VERSION 5.7 ;
BUSBITCHARS "[]" ;
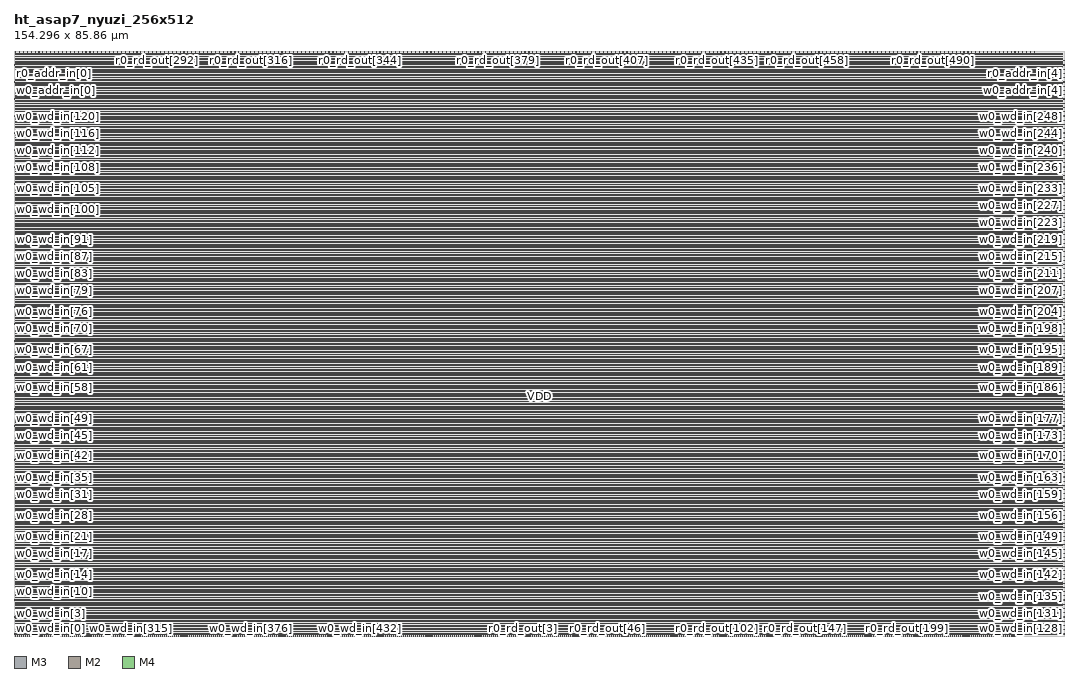
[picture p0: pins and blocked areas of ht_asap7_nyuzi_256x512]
MACRO ht_asap7_nyuzi_256x512
  FOREIGN ht_asap7_nyuzi_256x512 0 0 ;
  SYMMETRY X Y R90 ;
  SIZE 154.296 BY 85.860 ;
  CLASS BLOCK ;
  PIN w0_wd_in[0]
    DIRECTION INPUT ;
    USE SIGNAL ;
    SHAPE ABUTMENT ;
    PORT
      LAYER M3 ;
      RECT 0.000 0.276 0.072 0.300 ;
    END
  END w0_wd_in[0]
  PIN w0_wd_in[1]
    DIRECTION INPUT ;
    USE SIGNAL ;
    SHAPE ABUTMENT ;
    PORT
      LAYER M3 ;
      RECT 0.000 0.900 0.072 0.924 ;
    END
  END w0_wd_in[1]
  PIN w0_wd_in[2]
    DIRECTION INPUT ;
    USE SIGNAL ;
    SHAPE ABUTMENT ;
    PORT
      LAYER M3 ;
      RECT 0.000 1.524 0.072 1.548 ;
    END
  END w0_wd_in[2]
  PIN w0_wd_in[3]
    DIRECTION INPUT ;
    USE SIGNAL ;
    SHAPE ABUTMENT ;
    PORT
      LAYER M3 ;
      RECT 0.000 2.148 0.072 2.172 ;
    END
  END w0_wd_in[3]
  PIN w0_wd_in[4]
    DIRECTION INPUT ;
    USE SIGNAL ;
    SHAPE ABUTMENT ;
    PORT
      LAYER M3 ;
      RECT 0.000 2.772 0.072 2.796 ;
    END
  END w0_wd_in[4]
  PIN w0_wd_in[5]
    DIRECTION INPUT ;
    USE SIGNAL ;
    SHAPE ABUTMENT ;
    PORT
      LAYER M3 ;
      RECT 0.000 3.396 0.072 3.420 ;
    END
  END w0_wd_in[5]
  PIN w0_wd_in[6]
    DIRECTION INPUT ;
    USE SIGNAL ;
    SHAPE ABUTMENT ;
    PORT
      LAYER M3 ;
      RECT 0.000 4.020 0.072 4.044 ;
    END
  END w0_wd_in[6]
  PIN w0_wd_in[7]
    DIRECTION INPUT ;
    USE SIGNAL ;
    SHAPE ABUTMENT ;
    PORT
      LAYER M3 ;
      RECT 0.000 4.644 0.072 4.668 ;
    END
  END w0_wd_in[7]
  PIN w0_wd_in[8]
    DIRECTION INPUT ;
    USE SIGNAL ;
    SHAPE ABUTMENT ;
    PORT
      LAYER M3 ;
      RECT 0.000 5.268 0.072 5.292 ;
    END
  END w0_wd_in[8]
  PIN w0_wd_in[9]
    DIRECTION INPUT ;
    USE SIGNAL ;
    SHAPE ABUTMENT ;
    PORT
      LAYER M3 ;
      RECT 0.000 5.892 0.072 5.916 ;
    END
  END w0_wd_in[9]
  PIN w0_wd_in[10]
    DIRECTION INPUT ;
    USE SIGNAL ;
    SHAPE ABUTMENT ;
    PORT
      LAYER M3 ;
      RECT 0.000 6.516 0.072 6.540 ;
    END
  END w0_wd_in[10]
  PIN w0_wd_in[11]
    DIRECTION INPUT ;
    USE SIGNAL ;
    SHAPE ABUTMENT ;
    PORT
      LAYER M3 ;
      RECT 0.000 7.140 0.072 7.164 ;
    END
  END w0_wd_in[11]
  PIN w0_wd_in[12]
    DIRECTION INPUT ;
    USE SIGNAL ;
    SHAPE ABUTMENT ;
    PORT
      LAYER M3 ;
      RECT 0.000 7.764 0.072 7.788 ;
    END
  END w0_wd_in[12]
  PIN w0_wd_in[13]
    DIRECTION INPUT ;
    USE SIGNAL ;
    SHAPE ABUTMENT ;
    PORT
      LAYER M3 ;
      RECT 0.000 8.388 0.072 8.412 ;
    END
  END w0_wd_in[13]
  PIN w0_wd_in[14]
    DIRECTION INPUT ;
    USE SIGNAL ;
    SHAPE ABUTMENT ;
    PORT
      LAYER M3 ;
      RECT 0.000 9.012 0.072 9.036 ;
    END
  END w0_wd_in[14]
  PIN w0_wd_in[15]
    DIRECTION INPUT ;
    USE SIGNAL ;
    SHAPE ABUTMENT ;
    PORT
      LAYER M3 ;
      RECT 0.000 9.636 0.072 9.660 ;
    END
  END w0_wd_in[15]
  PIN w0_wd_in[16]
    DIRECTION INPUT ;
    USE SIGNAL ;
    SHAPE ABUTMENT ;
    PORT
      LAYER M3 ;
      RECT 0.000 10.260 0.072 10.284 ;
    END
  END w0_wd_in[16]
  PIN w0_wd_in[17]
    DIRECTION INPUT ;
    USE SIGNAL ;
    SHAPE ABUTMENT ;
    PORT
      LAYER M3 ;
      RECT 0.000 10.884 0.072 10.908 ;
    END
  END w0_wd_in[17]
  PIN w0_wd_in[18]
    DIRECTION INPUT ;
    USE SIGNAL ;
    SHAPE ABUTMENT ;
    PORT
      LAYER M3 ;
      RECT 0.000 11.508 0.072 11.532 ;
    END
  END w0_wd_in[18]
  PIN w0_wd_in[19]
    DIRECTION INPUT ;
    USE SIGNAL ;
    SHAPE ABUTMENT ;
    PORT
      LAYER M3 ;
      RECT 0.000 12.132 0.072 12.156 ;
    END
  END w0_wd_in[19]
  PIN w0_wd_in[20]
    DIRECTION INPUT ;
    USE SIGNAL ;
    SHAPE ABUTMENT ;
    PORT
      LAYER M3 ;
      RECT 0.000 12.756 0.072 12.780 ;
    END
  END w0_wd_in[20]
  PIN w0_wd_in[21]
    DIRECTION INPUT ;
    USE SIGNAL ;
    SHAPE ABUTMENT ;
    PORT
      LAYER M3 ;
      RECT 0.000 13.380 0.072 13.404 ;
    END
  END w0_wd_in[21]
  PIN w0_wd_in[22]
    DIRECTION INPUT ;
    USE SIGNAL ;
    SHAPE ABUTMENT ;
    PORT
      LAYER M3 ;
      RECT 0.000 14.004 0.072 14.028 ;
    END
  END w0_wd_in[22]
  PIN w0_wd_in[23]
    DIRECTION INPUT ;
    USE SIGNAL ;
    SHAPE ABUTMENT ;
    PORT
      LAYER M3 ;
      RECT 0.000 14.628 0.072 14.652 ;
    END
  END w0_wd_in[23]
  PIN w0_wd_in[24]
    DIRECTION INPUT ;
    USE SIGNAL ;
    SHAPE ABUTMENT ;
    PORT
      LAYER M3 ;
      RECT 0.000 15.252 0.072 15.276 ;
    END
  END w0_wd_in[24]
  PIN w0_wd_in[25]
    DIRECTION INPUT ;
    USE SIGNAL ;
    SHAPE ABUTMENT ;
    PORT
      LAYER M3 ;
      RECT 0.000 15.876 0.072 15.900 ;
    END
  END w0_wd_in[25]
  PIN w0_wd_in[26]
    DIRECTION INPUT ;
    USE SIGNAL ;
    SHAPE ABUTMENT ;
    PORT
      LAYER M3 ;
      RECT 0.000 16.500 0.072 16.524 ;
    END
  END w0_wd_in[26]
  PIN w0_wd_in[27]
    DIRECTION INPUT ;
    USE SIGNAL ;
    SHAPE ABUTMENT ;
    PORT
      LAYER M3 ;
      RECT 0.000 17.124 0.072 17.148 ;
    END
  END w0_wd_in[27]
  PIN w0_wd_in[28]
    DIRECTION INPUT ;
    USE SIGNAL ;
    SHAPE ABUTMENT ;
    PORT
      LAYER M3 ;
      RECT 0.000 17.748 0.072 17.772 ;
    END
  END w0_wd_in[28]
  PIN w0_wd_in[29]
    DIRECTION INPUT ;
    USE SIGNAL ;
    SHAPE ABUTMENT ;
    PORT
      LAYER M3 ;
      RECT 0.000 18.372 0.072 18.396 ;
    END
  END w0_wd_in[29]
  PIN w0_wd_in[30]
    DIRECTION INPUT ;
    USE SIGNAL ;
    SHAPE ABUTMENT ;
    PORT
      LAYER M3 ;
      RECT 0.000 18.996 0.072 19.020 ;
    END
  END w0_wd_in[30]
  PIN w0_wd_in[31]
    DIRECTION INPUT ;
    USE SIGNAL ;
    SHAPE ABUTMENT ;
    PORT
      LAYER M3 ;
      RECT 0.000 19.620 0.072 19.644 ;
    END
  END w0_wd_in[31]
  PIN w0_wd_in[32]
    DIRECTION INPUT ;
    USE SIGNAL ;
    SHAPE ABUTMENT ;
    PORT
      LAYER M3 ;
      RECT 0.000 20.244 0.072 20.268 ;
    END
  END w0_wd_in[32]
  PIN w0_wd_in[33]
    DIRECTION INPUT ;
    USE SIGNAL ;
    SHAPE ABUTMENT ;
    PORT
      LAYER M3 ;
      RECT 0.000 20.868 0.072 20.892 ;
    END
  END w0_wd_in[33]
  PIN w0_wd_in[34]
    DIRECTION INPUT ;
    USE SIGNAL ;
    SHAPE ABUTMENT ;
    PORT
      LAYER M3 ;
      RECT 0.000 21.492 0.072 21.516 ;
    END
  END w0_wd_in[34]
  PIN w0_wd_in[35]
    DIRECTION INPUT ;
    USE SIGNAL ;
    SHAPE ABUTMENT ;
    PORT
      LAYER M3 ;
      RECT 0.000 22.116 0.072 22.140 ;
    END
  END w0_wd_in[35]
  PIN w0_wd_in[36]
    DIRECTION INPUT ;
    USE SIGNAL ;
    SHAPE ABUTMENT ;
    PORT
      LAYER M3 ;
      RECT 0.000 22.740 0.072 22.764 ;
    END
  END w0_wd_in[36]
  PIN w0_wd_in[37]
    DIRECTION INPUT ;
    USE SIGNAL ;
    SHAPE ABUTMENT ;
    PORT
      LAYER M3 ;
      RECT 0.000 23.364 0.072 23.388 ;
    END
  END w0_wd_in[37]
  PIN w0_wd_in[38]
    DIRECTION INPUT ;
    USE SIGNAL ;
    SHAPE ABUTMENT ;
    PORT
      LAYER M3 ;
      RECT 0.000 23.988 0.072 24.012 ;
    END
  END w0_wd_in[38]
  PIN w0_wd_in[39]
    DIRECTION INPUT ;
    USE SIGNAL ;
    SHAPE ABUTMENT ;
    PORT
      LAYER M3 ;
      RECT 0.000 24.612 0.072 24.636 ;
    END
  END w0_wd_in[39]
  PIN w0_wd_in[40]
    DIRECTION INPUT ;
    USE SIGNAL ;
    SHAPE ABUTMENT ;
    PORT
      LAYER M3 ;
      RECT 0.000 25.236 0.072 25.260 ;
    END
  END w0_wd_in[40]
  PIN w0_wd_in[41]
    DIRECTION INPUT ;
    USE SIGNAL ;
    SHAPE ABUTMENT ;
    PORT
      LAYER M3 ;
      RECT 0.000 25.860 0.072 25.884 ;
    END
  END w0_wd_in[41]
  PIN w0_wd_in[42]
    DIRECTION INPUT ;
    USE SIGNAL ;
    SHAPE ABUTMENT ;
    PORT
      LAYER M3 ;
      RECT 0.000 26.484 0.072 26.508 ;
    END
  END w0_wd_in[42]
  PIN w0_wd_in[43]
    DIRECTION INPUT ;
    USE SIGNAL ;
    SHAPE ABUTMENT ;
    PORT
      LAYER M3 ;
      RECT 0.000 27.108 0.072 27.132 ;
    END
  END w0_wd_in[43]
  PIN w0_wd_in[44]
    DIRECTION INPUT ;
    USE SIGNAL ;
    SHAPE ABUTMENT ;
    PORT
      LAYER M3 ;
      RECT 0.000 27.732 0.072 27.756 ;
    END
  END w0_wd_in[44]
  PIN w0_wd_in[45]
    DIRECTION INPUT ;
    USE SIGNAL ;
    SHAPE ABUTMENT ;
    PORT
      LAYER M3 ;
      RECT 0.000 28.356 0.072 28.380 ;
    END
  END w0_wd_in[45]
  PIN w0_wd_in[46]
    DIRECTION INPUT ;
    USE SIGNAL ;
    SHAPE ABUTMENT ;
    PORT
      LAYER M3 ;
      RECT 0.000 28.980 0.072 29.004 ;
    END
  END w0_wd_in[46]
  PIN w0_wd_in[47]
    DIRECTION INPUT ;
    USE SIGNAL ;
    SHAPE ABUTMENT ;
    PORT
      LAYER M3 ;
      RECT 0.000 29.604 0.072 29.628 ;
    END
  END w0_wd_in[47]
  PIN w0_wd_in[48]
    DIRECTION INPUT ;
    USE SIGNAL ;
    SHAPE ABUTMENT ;
    PORT
      LAYER M3 ;
      RECT 0.000 30.228 0.072 30.252 ;
    END
  END w0_wd_in[48]
  PIN w0_wd_in[49]
    DIRECTION INPUT ;
    USE SIGNAL ;
    SHAPE ABUTMENT ;
    PORT
      LAYER M3 ;
      RECT 0.000 30.852 0.072 30.876 ;
    END
  END w0_wd_in[49]
  PIN w0_wd_in[50]
    DIRECTION INPUT ;
    USE SIGNAL ;
    SHAPE ABUTMENT ;
    PORT
      LAYER M3 ;
      RECT 0.000 31.476 0.072 31.500 ;
    END
  END w0_wd_in[50]
  PIN w0_wd_in[51]
    DIRECTION INPUT ;
    USE SIGNAL ;
    SHAPE ABUTMENT ;
    PORT
      LAYER M3 ;
      RECT 0.000 32.100 0.072 32.124 ;
    END
  END w0_wd_in[51]
  PIN w0_wd_in[52]
    DIRECTION INPUT ;
    USE SIGNAL ;
    SHAPE ABUTMENT ;
    PORT
      LAYER M3 ;
      RECT 0.000 32.724 0.072 32.748 ;
    END
  END w0_wd_in[52]
  PIN w0_wd_in[53]
    DIRECTION INPUT ;
    USE SIGNAL ;
    SHAPE ABUTMENT ;
    PORT
      LAYER M3 ;
      RECT 0.000 33.348 0.072 33.372 ;
    END
  END w0_wd_in[53]
  PIN w0_wd_in[54]
    DIRECTION INPUT ;
    USE SIGNAL ;
    SHAPE ABUTMENT ;
    PORT
      LAYER M3 ;
      RECT 0.000 33.972 0.072 33.996 ;
    END
  END w0_wd_in[54]
  PIN w0_wd_in[55]
    DIRECTION INPUT ;
    USE SIGNAL ;
    SHAPE ABUTMENT ;
    PORT
      LAYER M3 ;
      RECT 0.000 34.596 0.072 34.620 ;
    END
  END w0_wd_in[55]
  PIN w0_wd_in[56]
    DIRECTION INPUT ;
    USE SIGNAL ;
    SHAPE ABUTMENT ;
    PORT
      LAYER M3 ;
      RECT 0.000 35.220 0.072 35.244 ;
    END
  END w0_wd_in[56]
  PIN w0_wd_in[57]
    DIRECTION INPUT ;
    USE SIGNAL ;
    SHAPE ABUTMENT ;
    PORT
      LAYER M3 ;
      RECT 0.000 35.844 0.072 35.868 ;
    END
  END w0_wd_in[57]
  PIN w0_wd_in[58]
    DIRECTION INPUT ;
    USE SIGNAL ;
    SHAPE ABUTMENT ;
    PORT
      LAYER M3 ;
      RECT 0.000 36.468 0.072 36.492 ;
    END
  END w0_wd_in[58]
  PIN w0_wd_in[59]
    DIRECTION INPUT ;
    USE SIGNAL ;
    SHAPE ABUTMENT ;
    PORT
      LAYER M3 ;
      RECT 0.000 37.092 0.072 37.116 ;
    END
  END w0_wd_in[59]
  PIN w0_wd_in[60]
    DIRECTION INPUT ;
    USE SIGNAL ;
    SHAPE ABUTMENT ;
    PORT
      LAYER M3 ;
      RECT 0.000 37.716 0.072 37.740 ;
    END
  END w0_wd_in[60]
  PIN w0_wd_in[61]
    DIRECTION INPUT ;
    USE SIGNAL ;
    SHAPE ABUTMENT ;
    PORT
      LAYER M3 ;
      RECT 0.000 38.340 0.072 38.364 ;
    END
  END w0_wd_in[61]
  PIN w0_wd_in[62]
    DIRECTION INPUT ;
    USE SIGNAL ;
    SHAPE ABUTMENT ;
    PORT
      LAYER M3 ;
      RECT 0.000 38.964 0.072 38.988 ;
    END
  END w0_wd_in[62]
  PIN w0_wd_in[63]
    DIRECTION INPUT ;
    USE SIGNAL ;
    SHAPE ABUTMENT ;
    PORT
      LAYER M3 ;
      RECT 0.000 39.588 0.072 39.612 ;
    END
  END w0_wd_in[63]
  PIN w0_wd_in[64]
    DIRECTION INPUT ;
    USE SIGNAL ;
    SHAPE ABUTMENT ;
    PORT
      LAYER M3 ;
      RECT 0.000 40.212 0.072 40.236 ;
    END
  END w0_wd_in[64]
  PIN w0_wd_in[65]
    DIRECTION INPUT ;
    USE SIGNAL ;
    SHAPE ABUTMENT ;
    PORT
      LAYER M3 ;
      RECT 0.000 40.836 0.072 40.860 ;
    END
  END w0_wd_in[65]
  PIN w0_wd_in[66]
    DIRECTION INPUT ;
    USE SIGNAL ;
    SHAPE ABUTMENT ;
    PORT
      LAYER M3 ;
      RECT 0.000 41.460 0.072 41.484 ;
    END
  END w0_wd_in[66]
  PIN w0_wd_in[67]
    DIRECTION INPUT ;
    USE SIGNAL ;
    SHAPE ABUTMENT ;
    PORT
      LAYER M3 ;
      RECT 0.000 42.084 0.072 42.108 ;
    END
  END w0_wd_in[67]
  PIN w0_wd_in[68]
    DIRECTION INPUT ;
    USE SIGNAL ;
    SHAPE ABUTMENT ;
    PORT
      LAYER M3 ;
      RECT 0.000 42.708 0.072 42.732 ;
    END
  END w0_wd_in[68]
  PIN w0_wd_in[69]
    DIRECTION INPUT ;
    USE SIGNAL ;
    SHAPE ABUTMENT ;
    PORT
      LAYER M3 ;
      RECT 0.000 43.332 0.072 43.356 ;
    END
  END w0_wd_in[69]
  PIN w0_wd_in[70]
    DIRECTION INPUT ;
    USE SIGNAL ;
    SHAPE ABUTMENT ;
    PORT
      LAYER M3 ;
      RECT 0.000 43.956 0.072 43.980 ;
    END
  END w0_wd_in[70]
  PIN w0_wd_in[71]
    DIRECTION INPUT ;
    USE SIGNAL ;
    SHAPE ABUTMENT ;
    PORT
      LAYER M3 ;
      RECT 0.000 44.580 0.072 44.604 ;
    END
  END w0_wd_in[71]
  PIN w0_wd_in[72]
    DIRECTION INPUT ;
    USE SIGNAL ;
    SHAPE ABUTMENT ;
    PORT
      LAYER M3 ;
      RECT 0.000 45.204 0.072 45.228 ;
    END
  END w0_wd_in[72]
  PIN w0_wd_in[73]
    DIRECTION INPUT ;
    USE SIGNAL ;
    SHAPE ABUTMENT ;
    PORT
      LAYER M3 ;
      RECT 0.000 45.828 0.072 45.852 ;
    END
  END w0_wd_in[73]
  PIN w0_wd_in[74]
    DIRECTION INPUT ;
    USE SIGNAL ;
    SHAPE ABUTMENT ;
    PORT
      LAYER M3 ;
      RECT 0.000 46.452 0.072 46.476 ;
    END
  END w0_wd_in[74]
  PIN w0_wd_in[75]
    DIRECTION INPUT ;
    USE SIGNAL ;
    SHAPE ABUTMENT ;
    PORT
      LAYER M3 ;
      RECT 0.000 47.076 0.072 47.100 ;
    END
  END w0_wd_in[75]
  PIN w0_wd_in[76]
    DIRECTION INPUT ;
    USE SIGNAL ;
    SHAPE ABUTMENT ;
    PORT
      LAYER M3 ;
      RECT 0.000 47.700 0.072 47.724 ;
    END
  END w0_wd_in[76]
  PIN w0_wd_in[77]
    DIRECTION INPUT ;
    USE SIGNAL ;
    SHAPE ABUTMENT ;
    PORT
      LAYER M3 ;
      RECT 0.000 48.324 0.072 48.348 ;
    END
  END w0_wd_in[77]
  PIN w0_wd_in[78]
    DIRECTION INPUT ;
    USE SIGNAL ;
    SHAPE ABUTMENT ;
    PORT
      LAYER M3 ;
      RECT 0.000 48.948 0.072 48.972 ;
    END
  END w0_wd_in[78]
  PIN w0_wd_in[79]
    DIRECTION INPUT ;
    USE SIGNAL ;
    SHAPE ABUTMENT ;
    PORT
      LAYER M3 ;
      RECT 0.000 49.572 0.072 49.596 ;
    END
  END w0_wd_in[79]
  PIN w0_wd_in[80]
    DIRECTION INPUT ;
    USE SIGNAL ;
    SHAPE ABUTMENT ;
    PORT
      LAYER M3 ;
      RECT 0.000 50.196 0.072 50.220 ;
    END
  END w0_wd_in[80]
  PIN w0_wd_in[81]
    DIRECTION INPUT ;
    USE SIGNAL ;
    SHAPE ABUTMENT ;
    PORT
      LAYER M3 ;
      RECT 0.000 50.820 0.072 50.844 ;
    END
  END w0_wd_in[81]
  PIN w0_wd_in[82]
    DIRECTION INPUT ;
    USE SIGNAL ;
    SHAPE ABUTMENT ;
    PORT
      LAYER M3 ;
      RECT 0.000 51.444 0.072 51.468 ;
    END
  END w0_wd_in[82]
  PIN w0_wd_in[83]
    DIRECTION INPUT ;
    USE SIGNAL ;
    SHAPE ABUTMENT ;
    PORT
      LAYER M3 ;
      RECT 0.000 52.068 0.072 52.092 ;
    END
  END w0_wd_in[83]
  PIN w0_wd_in[84]
    DIRECTION INPUT ;
    USE SIGNAL ;
    SHAPE ABUTMENT ;
    PORT
      LAYER M3 ;
      RECT 0.000 52.692 0.072 52.716 ;
    END
  END w0_wd_in[84]
  PIN w0_wd_in[85]
    DIRECTION INPUT ;
    USE SIGNAL ;
    SHAPE ABUTMENT ;
    PORT
      LAYER M3 ;
      RECT 0.000 53.316 0.072 53.340 ;
    END
  END w0_wd_in[85]
  PIN w0_wd_in[86]
    DIRECTION INPUT ;
    USE SIGNAL ;
    SHAPE ABUTMENT ;
    PORT
      LAYER M3 ;
      RECT 0.000 53.940 0.072 53.964 ;
    END
  END w0_wd_in[86]
  PIN w0_wd_in[87]
    DIRECTION INPUT ;
    USE SIGNAL ;
    SHAPE ABUTMENT ;
    PORT
      LAYER M3 ;
      RECT 0.000 54.564 0.072 54.588 ;
    END
  END w0_wd_in[87]
  PIN w0_wd_in[88]
    DIRECTION INPUT ;
    USE SIGNAL ;
    SHAPE ABUTMENT ;
    PORT
      LAYER M3 ;
      RECT 0.000 55.188 0.072 55.212 ;
    END
  END w0_wd_in[88]
  PIN w0_wd_in[89]
    DIRECTION INPUT ;
    USE SIGNAL ;
    SHAPE ABUTMENT ;
    PORT
      LAYER M3 ;
      RECT 0.000 55.812 0.072 55.836 ;
    END
  END w0_wd_in[89]
  PIN w0_wd_in[90]
    DIRECTION INPUT ;
    USE SIGNAL ;
    SHAPE ABUTMENT ;
    PORT
      LAYER M3 ;
      RECT 0.000 56.436 0.072 56.460 ;
    END
  END w0_wd_in[90]
  PIN w0_wd_in[91]
    DIRECTION INPUT ;
    USE SIGNAL ;
    SHAPE ABUTMENT ;
    PORT
      LAYER M3 ;
      RECT 0.000 57.060 0.072 57.084 ;
    END
  END w0_wd_in[91]
  PIN w0_wd_in[92]
    DIRECTION INPUT ;
    USE SIGNAL ;
    SHAPE ABUTMENT ;
    PORT
      LAYER M3 ;
      RECT 0.000 57.684 0.072 57.708 ;
    END
  END w0_wd_in[92]
  PIN w0_wd_in[93]
    DIRECTION INPUT ;
    USE SIGNAL ;
    SHAPE ABUTMENT ;
    PORT
      LAYER M3 ;
      RECT 0.000 58.308 0.072 58.332 ;
    END
  END w0_wd_in[93]
  PIN w0_wd_in[94]
    DIRECTION INPUT ;
    USE SIGNAL ;
    SHAPE ABUTMENT ;
    PORT
      LAYER M3 ;
      RECT 0.000 58.932 0.072 58.956 ;
    END
  END w0_wd_in[94]
  PIN w0_wd_in[95]
    DIRECTION INPUT ;
    USE SIGNAL ;
    SHAPE ABUTMENT ;
    PORT
      LAYER M3 ;
      RECT 0.000 59.556 0.072 59.580 ;
    END
  END w0_wd_in[95]
  PIN w0_wd_in[96]
    DIRECTION INPUT ;
    USE SIGNAL ;
    SHAPE ABUTMENT ;
    PORT
      LAYER M3 ;
      RECT 0.000 60.180 0.072 60.204 ;
    END
  END w0_wd_in[96]
  PIN w0_wd_in[97]
    DIRECTION INPUT ;
    USE SIGNAL ;
    SHAPE ABUTMENT ;
    PORT
      LAYER M3 ;
      RECT 0.000 60.804 0.072 60.828 ;
    END
  END w0_wd_in[97]
  PIN w0_wd_in[98]
    DIRECTION INPUT ;
    USE SIGNAL ;
    SHAPE ABUTMENT ;
    PORT
      LAYER M3 ;
      RECT 0.000 61.428 0.072 61.452 ;
    END
  END w0_wd_in[98]
  PIN w0_wd_in[99]
    DIRECTION INPUT ;
    USE SIGNAL ;
    SHAPE ABUTMENT ;
    PORT
      LAYER M3 ;
      RECT 0.000 62.052 0.072 62.076 ;
    END
  END w0_wd_in[99]
  PIN w0_wd_in[100]
    DIRECTION INPUT ;
    USE SIGNAL ;
    SHAPE ABUTMENT ;
    PORT
      LAYER M3 ;
      RECT 0.000 62.676 0.072 62.700 ;
    END
  END w0_wd_in[100]
  PIN w0_wd_in[101]
    DIRECTION INPUT ;
    USE SIGNAL ;
    SHAPE ABUTMENT ;
    PORT
      LAYER M3 ;
      RECT 0.000 63.300 0.072 63.324 ;
    END
  END w0_wd_in[101]
  PIN w0_wd_in[102]
    DIRECTION INPUT ;
    USE SIGNAL ;
    SHAPE ABUTMENT ;
    PORT
      LAYER M3 ;
      RECT 0.000 63.924 0.072 63.948 ;
    END
  END w0_wd_in[102]
  PIN w0_wd_in[103]
    DIRECTION INPUT ;
    USE SIGNAL ;
    SHAPE ABUTMENT ;
    PORT
      LAYER M3 ;
      RECT 0.000 64.548 0.072 64.572 ;
    END
  END w0_wd_in[103]
  PIN w0_wd_in[104]
    DIRECTION INPUT ;
    USE SIGNAL ;
    SHAPE ABUTMENT ;
    PORT
      LAYER M3 ;
      RECT 0.000 65.172 0.072 65.196 ;
    END
  END w0_wd_in[104]
  PIN w0_wd_in[105]
    DIRECTION INPUT ;
    USE SIGNAL ;
    SHAPE ABUTMENT ;
    PORT
      LAYER M3 ;
      RECT 0.000 65.796 0.072 65.820 ;
    END
  END w0_wd_in[105]
  PIN w0_wd_in[106]
    DIRECTION INPUT ;
    USE SIGNAL ;
    SHAPE ABUTMENT ;
    PORT
      LAYER M3 ;
      RECT 0.000 66.420 0.072 66.444 ;
    END
  END w0_wd_in[106]
  PIN w0_wd_in[107]
    DIRECTION INPUT ;
    USE SIGNAL ;
    SHAPE ABUTMENT ;
    PORT
      LAYER M3 ;
      RECT 0.000 67.044 0.072 67.068 ;
    END
  END w0_wd_in[107]
  PIN w0_wd_in[108]
    DIRECTION INPUT ;
    USE SIGNAL ;
    SHAPE ABUTMENT ;
    PORT
      LAYER M3 ;
      RECT 0.000 67.668 0.072 67.692 ;
    END
  END w0_wd_in[108]
  PIN w0_wd_in[109]
    DIRECTION INPUT ;
    USE SIGNAL ;
    SHAPE ABUTMENT ;
    PORT
      LAYER M3 ;
      RECT 0.000 68.292 0.072 68.316 ;
    END
  END w0_wd_in[109]
  PIN w0_wd_in[110]
    DIRECTION INPUT ;
    USE SIGNAL ;
    SHAPE ABUTMENT ;
    PORT
      LAYER M3 ;
      RECT 0.000 68.916 0.072 68.940 ;
    END
  END w0_wd_in[110]
  PIN w0_wd_in[111]
    DIRECTION INPUT ;
    USE SIGNAL ;
    SHAPE ABUTMENT ;
    PORT
      LAYER M3 ;
      RECT 0.000 69.540 0.072 69.564 ;
    END
  END w0_wd_in[111]
  PIN w0_wd_in[112]
    DIRECTION INPUT ;
    USE SIGNAL ;
    SHAPE ABUTMENT ;
    PORT
      LAYER M3 ;
      RECT 0.000 70.164 0.072 70.188 ;
    END
  END w0_wd_in[112]
  PIN w0_wd_in[113]
    DIRECTION INPUT ;
    USE SIGNAL ;
    SHAPE ABUTMENT ;
    PORT
      LAYER M3 ;
      RECT 0.000 70.788 0.072 70.812 ;
    END
  END w0_wd_in[113]
  PIN w0_wd_in[114]
    DIRECTION INPUT ;
    USE SIGNAL ;
    SHAPE ABUTMENT ;
    PORT
      LAYER M3 ;
      RECT 0.000 71.412 0.072 71.436 ;
    END
  END w0_wd_in[114]
  PIN w0_wd_in[115]
    DIRECTION INPUT ;
    USE SIGNAL ;
    SHAPE ABUTMENT ;
    PORT
      LAYER M3 ;
      RECT 0.000 72.036 0.072 72.060 ;
    END
  END w0_wd_in[115]
  PIN w0_wd_in[116]
    DIRECTION INPUT ;
    USE SIGNAL ;
    SHAPE ABUTMENT ;
    PORT
      LAYER M3 ;
      RECT 0.000 72.660 0.072 72.684 ;
    END
  END w0_wd_in[116]
  PIN w0_wd_in[117]
    DIRECTION INPUT ;
    USE SIGNAL ;
    SHAPE ABUTMENT ;
    PORT
      LAYER M3 ;
      RECT 0.000 73.284 0.072 73.308 ;
    END
  END w0_wd_in[117]
  PIN w0_wd_in[118]
    DIRECTION INPUT ;
    USE SIGNAL ;
    SHAPE ABUTMENT ;
    PORT
      LAYER M3 ;
      RECT 0.000 73.908 0.072 73.932 ;
    END
  END w0_wd_in[118]
  PIN w0_wd_in[119]
    DIRECTION INPUT ;
    USE SIGNAL ;
    SHAPE ABUTMENT ;
    PORT
      LAYER M3 ;
      RECT 0.000 74.532 0.072 74.556 ;
    END
  END w0_wd_in[119]
  PIN w0_wd_in[120]
    DIRECTION INPUT ;
    USE SIGNAL ;
    SHAPE ABUTMENT ;
    PORT
      LAYER M3 ;
      RECT 0.000 75.156 0.072 75.180 ;
    END
  END w0_wd_in[120]
  PIN w0_wd_in[121]
    DIRECTION INPUT ;
    USE SIGNAL ;
    SHAPE ABUTMENT ;
    PORT
      LAYER M3 ;
      RECT 0.000 75.780 0.072 75.804 ;
    END
  END w0_wd_in[121]
  PIN w0_wd_in[122]
    DIRECTION INPUT ;
    USE SIGNAL ;
    SHAPE ABUTMENT ;
    PORT
      LAYER M3 ;
      RECT 0.000 76.404 0.072 76.428 ;
    END
  END w0_wd_in[122]
  PIN w0_wd_in[123]
    DIRECTION INPUT ;
    USE SIGNAL ;
    SHAPE ABUTMENT ;
    PORT
      LAYER M3 ;
      RECT 0.000 77.028 0.072 77.052 ;
    END
  END w0_wd_in[123]
  PIN w0_wd_in[124]
    DIRECTION INPUT ;
    USE SIGNAL ;
    SHAPE ABUTMENT ;
    PORT
      LAYER M3 ;
      RECT 0.000 77.652 0.072 77.676 ;
    END
  END w0_wd_in[124]
  PIN w0_wd_in[125]
    DIRECTION INPUT ;
    USE SIGNAL ;
    SHAPE ABUTMENT ;
    PORT
      LAYER M3 ;
      RECT 0.000 78.276 0.072 78.300 ;
    END
  END w0_wd_in[125]
  PIN w0_wd_in[126]
    DIRECTION INPUT ;
    USE SIGNAL ;
    SHAPE ABUTMENT ;
    PORT
      LAYER M3 ;
      RECT 0.000 78.900 0.072 78.924 ;
    END
  END w0_wd_in[126]
  PIN w0_wd_in[127]
    DIRECTION INPUT ;
    USE SIGNAL ;
    SHAPE ABUTMENT ;
    PORT
      LAYER M3 ;
      RECT 0.000 79.524 0.072 79.548 ;
    END
  END w0_wd_in[127]
  PIN w0_wd_in[128]
    DIRECTION INPUT ;
    USE SIGNAL ;
    SHAPE ABUTMENT ;
    PORT
      LAYER M3 ;
      RECT 154.224 0.276 154.296 0.300 ;
    END
  END w0_wd_in[128]
  PIN w0_wd_in[129]
    DIRECTION INPUT ;
    USE SIGNAL ;
    SHAPE ABUTMENT ;
    PORT
      LAYER M3 ;
      RECT 154.224 0.900 154.296 0.924 ;
    END
  END w0_wd_in[129]
  PIN w0_wd_in[130]
    DIRECTION INPUT ;
    USE SIGNAL ;
    SHAPE ABUTMENT ;
    PORT
      LAYER M3 ;
      RECT 154.224 1.524 154.296 1.548 ;
    END
  END w0_wd_in[130]
  PIN w0_wd_in[131]
    DIRECTION INPUT ;
    USE SIGNAL ;
    SHAPE ABUTMENT ;
    PORT
      LAYER M3 ;
      RECT 154.224 2.148 154.296 2.172 ;
    END
  END w0_wd_in[131]
  PIN w0_wd_in[132]
    DIRECTION INPUT ;
    USE SIGNAL ;
    SHAPE ABUTMENT ;
    PORT
      LAYER M3 ;
      RECT 154.224 2.772 154.296 2.796 ;
    END
  END w0_wd_in[132]
  PIN w0_wd_in[133]
    DIRECTION INPUT ;
    USE SIGNAL ;
    SHAPE ABUTMENT ;
    PORT
      LAYER M3 ;
      RECT 154.224 3.396 154.296 3.420 ;
    END
  END w0_wd_in[133]
  PIN w0_wd_in[134]
    DIRECTION INPUT ;
    USE SIGNAL ;
    SHAPE ABUTMENT ;
    PORT
      LAYER M3 ;
      RECT 154.224 4.020 154.296 4.044 ;
    END
  END w0_wd_in[134]
  PIN w0_wd_in[135]
    DIRECTION INPUT ;
    USE SIGNAL ;
    SHAPE ABUTMENT ;
    PORT
      LAYER M3 ;
      RECT 154.224 4.644 154.296 4.668 ;
    END
  END w0_wd_in[135]
  PIN w0_wd_in[136]
    DIRECTION INPUT ;
    USE SIGNAL ;
    SHAPE ABUTMENT ;
    PORT
      LAYER M3 ;
      RECT 154.224 5.268 154.296 5.292 ;
    END
  END w0_wd_in[136]
  PIN w0_wd_in[137]
    DIRECTION INPUT ;
    USE SIGNAL ;
    SHAPE ABUTMENT ;
    PORT
      LAYER M3 ;
      RECT 154.224 5.892 154.296 5.916 ;
    END
  END w0_wd_in[137]
  PIN w0_wd_in[138]
    DIRECTION INPUT ;
    USE SIGNAL ;
    SHAPE ABUTMENT ;
    PORT
      LAYER M3 ;
      RECT 154.224 6.516 154.296 6.540 ;
    END
  END w0_wd_in[138]
  PIN w0_wd_in[139]
    DIRECTION INPUT ;
    USE SIGNAL ;
    SHAPE ABUTMENT ;
    PORT
      LAYER M3 ;
      RECT 154.224 7.140 154.296 7.164 ;
    END
  END w0_wd_in[139]
  PIN w0_wd_in[140]
    DIRECTION INPUT ;
    USE SIGNAL ;
    SHAPE ABUTMENT ;
    PORT
      LAYER M3 ;
      RECT 154.224 7.764 154.296 7.788 ;
    END
  END w0_wd_in[140]
  PIN w0_wd_in[141]
    DIRECTION INPUT ;
    USE SIGNAL ;
    SHAPE ABUTMENT ;
    PORT
      LAYER M3 ;
      RECT 154.224 8.388 154.296 8.412 ;
    END
  END w0_wd_in[141]
  PIN w0_wd_in[142]
    DIRECTION INPUT ;
    USE SIGNAL ;
    SHAPE ABUTMENT ;
    PORT
      LAYER M3 ;
      RECT 154.224 9.012 154.296 9.036 ;
    END
  END w0_wd_in[142]
  PIN w0_wd_in[143]
    DIRECTION INPUT ;
    USE SIGNAL ;
    SHAPE ABUTMENT ;
    PORT
      LAYER M3 ;
      RECT 154.224 9.636 154.296 9.660 ;
    END
  END w0_wd_in[143]
  PIN w0_wd_in[144]
    DIRECTION INPUT ;
    USE SIGNAL ;
    SHAPE ABUTMENT ;
    PORT
      LAYER M3 ;
      RECT 154.224 10.260 154.296 10.284 ;
    END
  END w0_wd_in[144]
  PIN w0_wd_in[145]
    DIRECTION INPUT ;
    USE SIGNAL ;
    SHAPE ABUTMENT ;
    PORT
      LAYER M3 ;
      RECT 154.224 10.884 154.296 10.908 ;
    END
  END w0_wd_in[145]
  PIN w0_wd_in[146]
    DIRECTION INPUT ;
    USE SIGNAL ;
    SHAPE ABUTMENT ;
    PORT
      LAYER M3 ;
      RECT 154.224 11.508 154.296 11.532 ;
    END
  END w0_wd_in[146]
  PIN w0_wd_in[147]
    DIRECTION INPUT ;
    USE SIGNAL ;
    SHAPE ABUTMENT ;
    PORT
      LAYER M3 ;
      RECT 154.224 12.132 154.296 12.156 ;
    END
  END w0_wd_in[147]
  PIN w0_wd_in[148]
    DIRECTION INPUT ;
    USE SIGNAL ;
    SHAPE ABUTMENT ;
    PORT
      LAYER M3 ;
      RECT 154.224 12.756 154.296 12.780 ;
    END
  END w0_wd_in[148]
  PIN w0_wd_in[149]
    DIRECTION INPUT ;
    USE SIGNAL ;
    SHAPE ABUTMENT ;
    PORT
      LAYER M3 ;
      RECT 154.224 13.380 154.296 13.404 ;
    END
  END w0_wd_in[149]
  PIN w0_wd_in[150]
    DIRECTION INPUT ;
    USE SIGNAL ;
    SHAPE ABUTMENT ;
    PORT
      LAYER M3 ;
      RECT 154.224 14.004 154.296 14.028 ;
    END
  END w0_wd_in[150]
  PIN w0_wd_in[151]
    DIRECTION INPUT ;
    USE SIGNAL ;
    SHAPE ABUTMENT ;
    PORT
      LAYER M3 ;
      RECT 154.224 14.628 154.296 14.652 ;
    END
  END w0_wd_in[151]
  PIN w0_wd_in[152]
    DIRECTION INPUT ;
    USE SIGNAL ;
    SHAPE ABUTMENT ;
    PORT
      LAYER M3 ;
      RECT 154.224 15.252 154.296 15.276 ;
    END
  END w0_wd_in[152]
  PIN w0_wd_in[153]
    DIRECTION INPUT ;
    USE SIGNAL ;
    SHAPE ABUTMENT ;
    PORT
      LAYER M3 ;
      RECT 154.224 15.876 154.296 15.900 ;
    END
  END w0_wd_in[153]
  PIN w0_wd_in[154]
    DIRECTION INPUT ;
    USE SIGNAL ;
    SHAPE ABUTMENT ;
    PORT
      LAYER M3 ;
      RECT 154.224 16.500 154.296 16.524 ;
    END
  END w0_wd_in[154]
  PIN w0_wd_in[155]
    DIRECTION INPUT ;
    USE SIGNAL ;
    SHAPE ABUTMENT ;
    PORT
      LAYER M3 ;
      RECT 154.224 17.124 154.296 17.148 ;
    END
  END w0_wd_in[155]
  PIN w0_wd_in[156]
    DIRECTION INPUT ;
    USE SIGNAL ;
    SHAPE ABUTMENT ;
    PORT
      LAYER M3 ;
      RECT 154.224 17.748 154.296 17.772 ;
    END
  END w0_wd_in[156]
  PIN w0_wd_in[157]
    DIRECTION INPUT ;
    USE SIGNAL ;
    SHAPE ABUTMENT ;
    PORT
      LAYER M3 ;
      RECT 154.224 18.372 154.296 18.396 ;
    END
  END w0_wd_in[157]
  PIN w0_wd_in[158]
    DIRECTION INPUT ;
    USE SIGNAL ;
    SHAPE ABUTMENT ;
    PORT
      LAYER M3 ;
      RECT 154.224 18.996 154.296 19.020 ;
    END
  END w0_wd_in[158]
  PIN w0_wd_in[159]
    DIRECTION INPUT ;
    USE SIGNAL ;
    SHAPE ABUTMENT ;
    PORT
      LAYER M3 ;
      RECT 154.224 19.620 154.296 19.644 ;
    END
  END w0_wd_in[159]
  PIN w0_wd_in[160]
    DIRECTION INPUT ;
    USE SIGNAL ;
    SHAPE ABUTMENT ;
    PORT
      LAYER M3 ;
      RECT 154.224 20.244 154.296 20.268 ;
    END
  END w0_wd_in[160]
  PIN w0_wd_in[161]
    DIRECTION INPUT ;
    USE SIGNAL ;
    SHAPE ABUTMENT ;
    PORT
      LAYER M3 ;
      RECT 154.224 20.868 154.296 20.892 ;
    END
  END w0_wd_in[161]
  PIN w0_wd_in[162]
    DIRECTION INPUT ;
    USE SIGNAL ;
    SHAPE ABUTMENT ;
    PORT
      LAYER M3 ;
      RECT 154.224 21.492 154.296 21.516 ;
    END
  END w0_wd_in[162]
  PIN w0_wd_in[163]
    DIRECTION INPUT ;
    USE SIGNAL ;
    SHAPE ABUTMENT ;
    PORT
      LAYER M3 ;
      RECT 154.224 22.116 154.296 22.140 ;
    END
  END w0_wd_in[163]
  PIN w0_wd_in[164]
    DIRECTION INPUT ;
    USE SIGNAL ;
    SHAPE ABUTMENT ;
    PORT
      LAYER M3 ;
      RECT 154.224 22.740 154.296 22.764 ;
    END
  END w0_wd_in[164]
  PIN w0_wd_in[165]
    DIRECTION INPUT ;
    USE SIGNAL ;
    SHAPE ABUTMENT ;
    PORT
      LAYER M3 ;
      RECT 154.224 23.364 154.296 23.388 ;
    END
  END w0_wd_in[165]
  PIN w0_wd_in[166]
    DIRECTION INPUT ;
    USE SIGNAL ;
    SHAPE ABUTMENT ;
    PORT
      LAYER M3 ;
      RECT 154.224 23.988 154.296 24.012 ;
    END
  END w0_wd_in[166]
  PIN w0_wd_in[167]
    DIRECTION INPUT ;
    USE SIGNAL ;
    SHAPE ABUTMENT ;
    PORT
      LAYER M3 ;
      RECT 154.224 24.612 154.296 24.636 ;
    END
  END w0_wd_in[167]
  PIN w0_wd_in[168]
    DIRECTION INPUT ;
    USE SIGNAL ;
    SHAPE ABUTMENT ;
    PORT
      LAYER M3 ;
      RECT 154.224 25.236 154.296 25.260 ;
    END
  END w0_wd_in[168]
  PIN w0_wd_in[169]
    DIRECTION INPUT ;
    USE SIGNAL ;
    SHAPE ABUTMENT ;
    PORT
      LAYER M3 ;
      RECT 154.224 25.860 154.296 25.884 ;
    END
  END w0_wd_in[169]
  PIN w0_wd_in[170]
    DIRECTION INPUT ;
    USE SIGNAL ;
    SHAPE ABUTMENT ;
    PORT
      LAYER M3 ;
      RECT 154.224 26.484 154.296 26.508 ;
    END
  END w0_wd_in[170]
  PIN w0_wd_in[171]
    DIRECTION INPUT ;
    USE SIGNAL ;
    SHAPE ABUTMENT ;
    PORT
      LAYER M3 ;
      RECT 154.224 27.108 154.296 27.132 ;
    END
  END w0_wd_in[171]
  PIN w0_wd_in[172]
    DIRECTION INPUT ;
    USE SIGNAL ;
    SHAPE ABUTMENT ;
    PORT
      LAYER M3 ;
      RECT 154.224 27.732 154.296 27.756 ;
    END
  END w0_wd_in[172]
  PIN w0_wd_in[173]
    DIRECTION INPUT ;
    USE SIGNAL ;
    SHAPE ABUTMENT ;
    PORT
      LAYER M3 ;
      RECT 154.224 28.356 154.296 28.380 ;
    END
  END w0_wd_in[173]
  PIN w0_wd_in[174]
    DIRECTION INPUT ;
    USE SIGNAL ;
    SHAPE ABUTMENT ;
    PORT
      LAYER M3 ;
      RECT 154.224 28.980 154.296 29.004 ;
    END
  END w0_wd_in[174]
  PIN w0_wd_in[175]
    DIRECTION INPUT ;
    USE SIGNAL ;
    SHAPE ABUTMENT ;
    PORT
      LAYER M3 ;
      RECT 154.224 29.604 154.296 29.628 ;
    END
  END w0_wd_in[175]
  PIN w0_wd_in[176]
    DIRECTION INPUT ;
    USE SIGNAL ;
    SHAPE ABUTMENT ;
    PORT
      LAYER M3 ;
      RECT 154.224 30.228 154.296 30.252 ;
    END
  END w0_wd_in[176]
  PIN w0_wd_in[177]
    DIRECTION INPUT ;
    USE SIGNAL ;
    SHAPE ABUTMENT ;
    PORT
      LAYER M3 ;
      RECT 154.224 30.852 154.296 30.876 ;
    END
  END w0_wd_in[177]
  PIN w0_wd_in[178]
    DIRECTION INPUT ;
    USE SIGNAL ;
    SHAPE ABUTMENT ;
    PORT
      LAYER M3 ;
      RECT 154.224 31.476 154.296 31.500 ;
    END
  END w0_wd_in[178]
  PIN w0_wd_in[179]
    DIRECTION INPUT ;
    USE SIGNAL ;
    SHAPE ABUTMENT ;
    PORT
      LAYER M3 ;
      RECT 154.224 32.100 154.296 32.124 ;
    END
  END w0_wd_in[179]
  PIN w0_wd_in[180]
    DIRECTION INPUT ;
    USE SIGNAL ;
    SHAPE ABUTMENT ;
    PORT
      LAYER M3 ;
      RECT 154.224 32.724 154.296 32.748 ;
    END
  END w0_wd_in[180]
  PIN w0_wd_in[181]
    DIRECTION INPUT ;
    USE SIGNAL ;
    SHAPE ABUTMENT ;
    PORT
      LAYER M3 ;
      RECT 154.224 33.348 154.296 33.372 ;
    END
  END w0_wd_in[181]
  PIN w0_wd_in[182]
    DIRECTION INPUT ;
    USE SIGNAL ;
    SHAPE ABUTMENT ;
    PORT
      LAYER M3 ;
      RECT 154.224 33.972 154.296 33.996 ;
    END
  END w0_wd_in[182]
  PIN w0_wd_in[183]
    DIRECTION INPUT ;
    USE SIGNAL ;
    SHAPE ABUTMENT ;
    PORT
      LAYER M3 ;
      RECT 154.224 34.596 154.296 34.620 ;
    END
  END w0_wd_in[183]
  PIN w0_wd_in[184]
    DIRECTION INPUT ;
    USE SIGNAL ;
    SHAPE ABUTMENT ;
    PORT
      LAYER M3 ;
      RECT 154.224 35.220 154.296 35.244 ;
    END
  END w0_wd_in[184]
  PIN w0_wd_in[185]
    DIRECTION INPUT ;
    USE SIGNAL ;
    SHAPE ABUTMENT ;
    PORT
      LAYER M3 ;
      RECT 154.224 35.844 154.296 35.868 ;
    END
  END w0_wd_in[185]
  PIN w0_wd_in[186]
    DIRECTION INPUT ;
    USE SIGNAL ;
    SHAPE ABUTMENT ;
    PORT
      LAYER M3 ;
      RECT 154.224 36.468 154.296 36.492 ;
    END
  END w0_wd_in[186]
  PIN w0_wd_in[187]
    DIRECTION INPUT ;
    USE SIGNAL ;
    SHAPE ABUTMENT ;
    PORT
      LAYER M3 ;
      RECT 154.224 37.092 154.296 37.116 ;
    END
  END w0_wd_in[187]
  PIN w0_wd_in[188]
    DIRECTION INPUT ;
    USE SIGNAL ;
    SHAPE ABUTMENT ;
    PORT
      LAYER M3 ;
      RECT 154.224 37.716 154.296 37.740 ;
    END
  END w0_wd_in[188]
  PIN w0_wd_in[189]
    DIRECTION INPUT ;
    USE SIGNAL ;
    SHAPE ABUTMENT ;
    PORT
      LAYER M3 ;
      RECT 154.224 38.340 154.296 38.364 ;
    END
  END w0_wd_in[189]
  PIN w0_wd_in[190]
    DIRECTION INPUT ;
    USE SIGNAL ;
    SHAPE ABUTMENT ;
    PORT
      LAYER M3 ;
      RECT 154.224 38.964 154.296 38.988 ;
    END
  END w0_wd_in[190]
  PIN w0_wd_in[191]
    DIRECTION INPUT ;
    USE SIGNAL ;
    SHAPE ABUTMENT ;
    PORT
      LAYER M3 ;
      RECT 154.224 39.588 154.296 39.612 ;
    END
  END w0_wd_in[191]
  PIN w0_wd_in[192]
    DIRECTION INPUT ;
    USE SIGNAL ;
    SHAPE ABUTMENT ;
    PORT
      LAYER M3 ;
      RECT 154.224 40.212 154.296 40.236 ;
    END
  END w0_wd_in[192]
  PIN w0_wd_in[193]
    DIRECTION INPUT ;
    USE SIGNAL ;
    SHAPE ABUTMENT ;
    PORT
      LAYER M3 ;
      RECT 154.224 40.836 154.296 40.860 ;
    END
  END w0_wd_in[193]
  PIN w0_wd_in[194]
    DIRECTION INPUT ;
    USE SIGNAL ;
    SHAPE ABUTMENT ;
    PORT
      LAYER M3 ;
      RECT 154.224 41.460 154.296 41.484 ;
    END
  END w0_wd_in[194]
  PIN w0_wd_in[195]
    DIRECTION INPUT ;
    USE SIGNAL ;
    SHAPE ABUTMENT ;
    PORT
      LAYER M3 ;
      RECT 154.224 42.084 154.296 42.108 ;
    END
  END w0_wd_in[195]
  PIN w0_wd_in[196]
    DIRECTION INPUT ;
    USE SIGNAL ;
    SHAPE ABUTMENT ;
    PORT
      LAYER M3 ;
      RECT 154.224 42.708 154.296 42.732 ;
    END
  END w0_wd_in[196]
  PIN w0_wd_in[197]
    DIRECTION INPUT ;
    USE SIGNAL ;
    SHAPE ABUTMENT ;
    PORT
      LAYER M3 ;
      RECT 154.224 43.332 154.296 43.356 ;
    END
  END w0_wd_in[197]
  PIN w0_wd_in[198]
    DIRECTION INPUT ;
    USE SIGNAL ;
    SHAPE ABUTMENT ;
    PORT
      LAYER M3 ;
      RECT 154.224 43.956 154.296 43.980 ;
    END
  END w0_wd_in[198]
  PIN w0_wd_in[199]
    DIRECTION INPUT ;
    USE SIGNAL ;
    SHAPE ABUTMENT ;
    PORT
      LAYER M3 ;
      RECT 154.224 44.580 154.296 44.604 ;
    END
  END w0_wd_in[199]
  PIN w0_wd_in[200]
    DIRECTION INPUT ;
    USE SIGNAL ;
    SHAPE ABUTMENT ;
    PORT
      LAYER M3 ;
      RECT 154.224 45.204 154.296 45.228 ;
    END
  END w0_wd_in[200]
  PIN w0_wd_in[201]
    DIRECTION INPUT ;
    USE SIGNAL ;
    SHAPE ABUTMENT ;
    PORT
      LAYER M3 ;
      RECT 154.224 45.828 154.296 45.852 ;
    END
  END w0_wd_in[201]
  PIN w0_wd_in[202]
    DIRECTION INPUT ;
    USE SIGNAL ;
    SHAPE ABUTMENT ;
    PORT
      LAYER M3 ;
      RECT 154.224 46.452 154.296 46.476 ;
    END
  END w0_wd_in[202]
  PIN w0_wd_in[203]
    DIRECTION INPUT ;
    USE SIGNAL ;
    SHAPE ABUTMENT ;
    PORT
      LAYER M3 ;
      RECT 154.224 47.076 154.296 47.100 ;
    END
  END w0_wd_in[203]
  PIN w0_wd_in[204]
    DIRECTION INPUT ;
    USE SIGNAL ;
    SHAPE ABUTMENT ;
    PORT
      LAYER M3 ;
      RECT 154.224 47.700 154.296 47.724 ;
    END
  END w0_wd_in[204]
  PIN w0_wd_in[205]
    DIRECTION INPUT ;
    USE SIGNAL ;
    SHAPE ABUTMENT ;
    PORT
      LAYER M3 ;
      RECT 154.224 48.324 154.296 48.348 ;
    END
  END w0_wd_in[205]
  PIN w0_wd_in[206]
    DIRECTION INPUT ;
    USE SIGNAL ;
    SHAPE ABUTMENT ;
    PORT
      LAYER M3 ;
      RECT 154.224 48.948 154.296 48.972 ;
    END
  END w0_wd_in[206]
  PIN w0_wd_in[207]
    DIRECTION INPUT ;
    USE SIGNAL ;
    SHAPE ABUTMENT ;
    PORT
      LAYER M3 ;
      RECT 154.224 49.572 154.296 49.596 ;
    END
  END w0_wd_in[207]
  PIN w0_wd_in[208]
    DIRECTION INPUT ;
    USE SIGNAL ;
    SHAPE ABUTMENT ;
    PORT
      LAYER M3 ;
      RECT 154.224 50.196 154.296 50.220 ;
    END
  END w0_wd_in[208]
  PIN w0_wd_in[209]
    DIRECTION INPUT ;
    USE SIGNAL ;
    SHAPE ABUTMENT ;
    PORT
      LAYER M3 ;
      RECT 154.224 50.820 154.296 50.844 ;
    END
  END w0_wd_in[209]
  PIN w0_wd_in[210]
    DIRECTION INPUT ;
    USE SIGNAL ;
    SHAPE ABUTMENT ;
    PORT
      LAYER M3 ;
      RECT 154.224 51.444 154.296 51.468 ;
    END
  END w0_wd_in[210]
  PIN w0_wd_in[211]
    DIRECTION INPUT ;
    USE SIGNAL ;
    SHAPE ABUTMENT ;
    PORT
      LAYER M3 ;
      RECT 154.224 52.068 154.296 52.092 ;
    END
  END w0_wd_in[211]
  PIN w0_wd_in[212]
    DIRECTION INPUT ;
    USE SIGNAL ;
    SHAPE ABUTMENT ;
    PORT
      LAYER M3 ;
      RECT 154.224 52.692 154.296 52.716 ;
    END
  END w0_wd_in[212]
  PIN w0_wd_in[213]
    DIRECTION INPUT ;
    USE SIGNAL ;
    SHAPE ABUTMENT ;
    PORT
      LAYER M3 ;
      RECT 154.224 53.316 154.296 53.340 ;
    END
  END w0_wd_in[213]
  PIN w0_wd_in[214]
    DIRECTION INPUT ;
    USE SIGNAL ;
    SHAPE ABUTMENT ;
    PORT
      LAYER M3 ;
      RECT 154.224 53.940 154.296 53.964 ;
    END
  END w0_wd_in[214]
  PIN w0_wd_in[215]
    DIRECTION INPUT ;
    USE SIGNAL ;
    SHAPE ABUTMENT ;
    PORT
      LAYER M3 ;
      RECT 154.224 54.564 154.296 54.588 ;
    END
  END w0_wd_in[215]
  PIN w0_wd_in[216]
    DIRECTION INPUT ;
    USE SIGNAL ;
    SHAPE ABUTMENT ;
    PORT
      LAYER M3 ;
      RECT 154.224 55.188 154.296 55.212 ;
    END
  END w0_wd_in[216]
  PIN w0_wd_in[217]
    DIRECTION INPUT ;
    USE SIGNAL ;
    SHAPE ABUTMENT ;
    PORT
      LAYER M3 ;
      RECT 154.224 55.812 154.296 55.836 ;
    END
  END w0_wd_in[217]
  PIN w0_wd_in[218]
    DIRECTION INPUT ;
    USE SIGNAL ;
    SHAPE ABUTMENT ;
    PORT
      LAYER M3 ;
      RECT 154.224 56.436 154.296 56.460 ;
    END
  END w0_wd_in[218]
  PIN w0_wd_in[219]
    DIRECTION INPUT ;
    USE SIGNAL ;
    SHAPE ABUTMENT ;
    PORT
      LAYER M3 ;
      RECT 154.224 57.060 154.296 57.084 ;
    END
  END w0_wd_in[219]
  PIN w0_wd_in[220]
    DIRECTION INPUT ;
    USE SIGNAL ;
    SHAPE ABUTMENT ;
    PORT
      LAYER M3 ;
      RECT 154.224 57.684 154.296 57.708 ;
    END
  END w0_wd_in[220]
  PIN w0_wd_in[221]
    DIRECTION INPUT ;
    USE SIGNAL ;
    SHAPE ABUTMENT ;
    PORT
      LAYER M3 ;
      RECT 154.224 58.308 154.296 58.332 ;
    END
  END w0_wd_in[221]
  PIN w0_wd_in[222]
    DIRECTION INPUT ;
    USE SIGNAL ;
    SHAPE ABUTMENT ;
    PORT
      LAYER M3 ;
      RECT 154.224 58.932 154.296 58.956 ;
    END
  END w0_wd_in[222]
  PIN w0_wd_in[223]
    DIRECTION INPUT ;
    USE SIGNAL ;
    SHAPE ABUTMENT ;
    PORT
      LAYER M3 ;
      RECT 154.224 59.556 154.296 59.580 ;
    END
  END w0_wd_in[223]
  PIN w0_wd_in[224]
    DIRECTION INPUT ;
    USE SIGNAL ;
    SHAPE ABUTMENT ;
    PORT
      LAYER M3 ;
      RECT 154.224 60.180 154.296 60.204 ;
    END
  END w0_wd_in[224]
  PIN w0_wd_in[225]
    DIRECTION INPUT ;
    USE SIGNAL ;
    SHAPE ABUTMENT ;
    PORT
      LAYER M3 ;
      RECT 154.224 60.804 154.296 60.828 ;
    END
  END w0_wd_in[225]
  PIN w0_wd_in[226]
    DIRECTION INPUT ;
    USE SIGNAL ;
    SHAPE ABUTMENT ;
    PORT
      LAYER M3 ;
      RECT 154.224 61.428 154.296 61.452 ;
    END
  END w0_wd_in[226]
  PIN w0_wd_in[227]
    DIRECTION INPUT ;
    USE SIGNAL ;
    SHAPE ABUTMENT ;
    PORT
      LAYER M3 ;
      RECT 154.224 62.052 154.296 62.076 ;
    END
  END w0_wd_in[227]
  PIN w0_wd_in[228]
    DIRECTION INPUT ;
    USE SIGNAL ;
    SHAPE ABUTMENT ;
    PORT
      LAYER M3 ;
      RECT 154.224 62.676 154.296 62.700 ;
    END
  END w0_wd_in[228]
  PIN w0_wd_in[229]
    DIRECTION INPUT ;
    USE SIGNAL ;
    SHAPE ABUTMENT ;
    PORT
      LAYER M3 ;
      RECT 154.224 63.300 154.296 63.324 ;
    END
  END w0_wd_in[229]
  PIN w0_wd_in[230]
    DIRECTION INPUT ;
    USE SIGNAL ;
    SHAPE ABUTMENT ;
    PORT
      LAYER M3 ;
      RECT 154.224 63.924 154.296 63.948 ;
    END
  END w0_wd_in[230]
  PIN w0_wd_in[231]
    DIRECTION INPUT ;
    USE SIGNAL ;
    SHAPE ABUTMENT ;
    PORT
      LAYER M3 ;
      RECT 154.224 64.548 154.296 64.572 ;
    END
  END w0_wd_in[231]
  PIN w0_wd_in[232]
    DIRECTION INPUT ;
    USE SIGNAL ;
    SHAPE ABUTMENT ;
    PORT
      LAYER M3 ;
      RECT 154.224 65.172 154.296 65.196 ;
    END
  END w0_wd_in[232]
  PIN w0_wd_in[233]
    DIRECTION INPUT ;
    USE SIGNAL ;
    SHAPE ABUTMENT ;
    PORT
      LAYER M3 ;
      RECT 154.224 65.796 154.296 65.820 ;
    END
  END w0_wd_in[233]
  PIN w0_wd_in[234]
    DIRECTION INPUT ;
    USE SIGNAL ;
    SHAPE ABUTMENT ;
    PORT
      LAYER M3 ;
      RECT 154.224 66.420 154.296 66.444 ;
    END
  END w0_wd_in[234]
  PIN w0_wd_in[235]
    DIRECTION INPUT ;
    USE SIGNAL ;
    SHAPE ABUTMENT ;
    PORT
      LAYER M3 ;
      RECT 154.224 67.044 154.296 67.068 ;
    END
  END w0_wd_in[235]
  PIN w0_wd_in[236]
    DIRECTION INPUT ;
    USE SIGNAL ;
    SHAPE ABUTMENT ;
    PORT
      LAYER M3 ;
      RECT 154.224 67.668 154.296 67.692 ;
    END
  END w0_wd_in[236]
  PIN w0_wd_in[237]
    DIRECTION INPUT ;
    USE SIGNAL ;
    SHAPE ABUTMENT ;
    PORT
      LAYER M3 ;
      RECT 154.224 68.292 154.296 68.316 ;
    END
  END w0_wd_in[237]
  PIN w0_wd_in[238]
    DIRECTION INPUT ;
    USE SIGNAL ;
    SHAPE ABUTMENT ;
    PORT
      LAYER M3 ;
      RECT 154.224 68.916 154.296 68.940 ;
    END
  END w0_wd_in[238]
  PIN w0_wd_in[239]
    DIRECTION INPUT ;
    USE SIGNAL ;
    SHAPE ABUTMENT ;
    PORT
      LAYER M3 ;
      RECT 154.224 69.540 154.296 69.564 ;
    END
  END w0_wd_in[239]
  PIN w0_wd_in[240]
    DIRECTION INPUT ;
    USE SIGNAL ;
    SHAPE ABUTMENT ;
    PORT
      LAYER M3 ;
      RECT 154.224 70.164 154.296 70.188 ;
    END
  END w0_wd_in[240]
  PIN w0_wd_in[241]
    DIRECTION INPUT ;
    USE SIGNAL ;
    SHAPE ABUTMENT ;
    PORT
      LAYER M3 ;
      RECT 154.224 70.788 154.296 70.812 ;
    END
  END w0_wd_in[241]
  PIN w0_wd_in[242]
    DIRECTION INPUT ;
    USE SIGNAL ;
    SHAPE ABUTMENT ;
    PORT
      LAYER M3 ;
      RECT 154.224 71.412 154.296 71.436 ;
    END
  END w0_wd_in[242]
  PIN w0_wd_in[243]
    DIRECTION INPUT ;
    USE SIGNAL ;
    SHAPE ABUTMENT ;
    PORT
      LAYER M3 ;
      RECT 154.224 72.036 154.296 72.060 ;
    END
  END w0_wd_in[243]
  PIN w0_wd_in[244]
    DIRECTION INPUT ;
    USE SIGNAL ;
    SHAPE ABUTMENT ;
    PORT
      LAYER M3 ;
      RECT 154.224 72.660 154.296 72.684 ;
    END
  END w0_wd_in[244]
  PIN w0_wd_in[245]
    DIRECTION INPUT ;
    USE SIGNAL ;
    SHAPE ABUTMENT ;
    PORT
      LAYER M3 ;
      RECT 154.224 73.284 154.296 73.308 ;
    END
  END w0_wd_in[245]
  PIN w0_wd_in[246]
    DIRECTION INPUT ;
    USE SIGNAL ;
    SHAPE ABUTMENT ;
    PORT
      LAYER M3 ;
      RECT 154.224 73.908 154.296 73.932 ;
    END
  END w0_wd_in[246]
  PIN w0_wd_in[247]
    DIRECTION INPUT ;
    USE SIGNAL ;
    SHAPE ABUTMENT ;
    PORT
      LAYER M3 ;
      RECT 154.224 74.532 154.296 74.556 ;
    END
  END w0_wd_in[247]
  PIN w0_wd_in[248]
    DIRECTION INPUT ;
    USE SIGNAL ;
    SHAPE ABUTMENT ;
    PORT
      LAYER M3 ;
      RECT 154.224 75.156 154.296 75.180 ;
    END
  END w0_wd_in[248]
  PIN w0_wd_in[249]
    DIRECTION INPUT ;
    USE SIGNAL ;
    SHAPE ABUTMENT ;
    PORT
      LAYER M3 ;
      RECT 154.224 75.780 154.296 75.804 ;
    END
  END w0_wd_in[249]
  PIN w0_wd_in[250]
    DIRECTION INPUT ;
    USE SIGNAL ;
    SHAPE ABUTMENT ;
    PORT
      LAYER M3 ;
      RECT 154.224 76.404 154.296 76.428 ;
    END
  END w0_wd_in[250]
  PIN w0_wd_in[251]
    DIRECTION INPUT ;
    USE SIGNAL ;
    SHAPE ABUTMENT ;
    PORT
      LAYER M3 ;
      RECT 154.224 77.028 154.296 77.052 ;
    END
  END w0_wd_in[251]
  PIN w0_wd_in[252]
    DIRECTION INPUT ;
    USE SIGNAL ;
    SHAPE ABUTMENT ;
    PORT
      LAYER M3 ;
      RECT 154.224 77.652 154.296 77.676 ;
    END
  END w0_wd_in[252]
  PIN w0_wd_in[253]
    DIRECTION INPUT ;
    USE SIGNAL ;
    SHAPE ABUTMENT ;
    PORT
      LAYER M3 ;
      RECT 154.224 78.276 154.296 78.300 ;
    END
  END w0_wd_in[253]
  PIN w0_wd_in[254]
    DIRECTION INPUT ;
    USE SIGNAL ;
    SHAPE ABUTMENT ;
    PORT
      LAYER M3 ;
      RECT 154.224 78.900 154.296 78.924 ;
    END
  END w0_wd_in[254]
  PIN w0_wd_in[255]
    DIRECTION INPUT ;
    USE SIGNAL ;
    SHAPE ABUTMENT ;
    PORT
      LAYER M3 ;
      RECT 154.224 79.524 154.296 79.548 ;
    END
  END w0_wd_in[255]
  PIN w0_wd_in[256]
    DIRECTION INPUT ;
    USE SIGNAL ;
    SHAPE ABUTMENT ;
    PORT
      LAYER M2 ;
      RECT 0.207 0.000 0.225 0.270 ;
    END
  END w0_wd_in[256]
  PIN w0_wd_in[257]
    DIRECTION INPUT ;
    USE SIGNAL ;
    SHAPE ABUTMENT ;
    PORT
      LAYER M2 ;
      RECT 0.495 0.000 0.513 0.270 ;
    END
  END w0_wd_in[257]
  PIN w0_wd_in[258]
    DIRECTION INPUT ;
    USE SIGNAL ;
    SHAPE ABUTMENT ;
    PORT
      LAYER M2 ;
      RECT 0.783 0.000 0.801 0.270 ;
    END
  END w0_wd_in[258]
  PIN w0_wd_in[259]
    DIRECTION INPUT ;
    USE SIGNAL ;
    SHAPE ABUTMENT ;
    PORT
      LAYER M2 ;
      RECT 1.071 0.000 1.089 0.270 ;
    END
  END w0_wd_in[259]
  PIN w0_wd_in[260]
    DIRECTION INPUT ;
    USE SIGNAL ;
    SHAPE ABUTMENT ;
    PORT
      LAYER M2 ;
      RECT 1.359 0.000 1.377 0.270 ;
    END
  END w0_wd_in[260]
  PIN w0_wd_in[261]
    DIRECTION INPUT ;
    USE SIGNAL ;
    SHAPE ABUTMENT ;
    PORT
      LAYER M2 ;
      RECT 1.647 0.000 1.665 0.270 ;
    END
  END w0_wd_in[261]
  PIN w0_wd_in[262]
    DIRECTION INPUT ;
    USE SIGNAL ;
    SHAPE ABUTMENT ;
    PORT
      LAYER M2 ;
      RECT 1.935 0.000 1.953 0.270 ;
    END
  END w0_wd_in[262]
  PIN w0_wd_in[263]
    DIRECTION INPUT ;
    USE SIGNAL ;
    SHAPE ABUTMENT ;
    PORT
      LAYER M2 ;
      RECT 2.223 0.000 2.241 0.270 ;
    END
  END w0_wd_in[263]
  PIN w0_wd_in[264]
    DIRECTION INPUT ;
    USE SIGNAL ;
    SHAPE ABUTMENT ;
    PORT
      LAYER M2 ;
      RECT 2.511 0.000 2.529 0.270 ;
    END
  END w0_wd_in[264]
  PIN w0_wd_in[265]
    DIRECTION INPUT ;
    USE SIGNAL ;
    SHAPE ABUTMENT ;
    PORT
      LAYER M2 ;
      RECT 2.799 0.000 2.817 0.270 ;
    END
  END w0_wd_in[265]
  PIN w0_wd_in[266]
    DIRECTION INPUT ;
    USE SIGNAL ;
    SHAPE ABUTMENT ;
    PORT
      LAYER M2 ;
      RECT 3.087 0.000 3.105 0.270 ;
    END
  END w0_wd_in[266]
  PIN w0_wd_in[267]
    DIRECTION INPUT ;
    USE SIGNAL ;
    SHAPE ABUTMENT ;
    PORT
      LAYER M2 ;
      RECT 3.375 0.000 3.393 0.270 ;
    END
  END w0_wd_in[267]
  PIN w0_wd_in[268]
    DIRECTION INPUT ;
    USE SIGNAL ;
    SHAPE ABUTMENT ;
    PORT
      LAYER M2 ;
      RECT 3.663 0.000 3.681 0.270 ;
    END
  END w0_wd_in[268]
  PIN w0_wd_in[269]
    DIRECTION INPUT ;
    USE SIGNAL ;
    SHAPE ABUTMENT ;
    PORT
      LAYER M2 ;
      RECT 3.951 0.000 3.969 0.270 ;
    END
  END w0_wd_in[269]
  PIN w0_wd_in[270]
    DIRECTION INPUT ;
    USE SIGNAL ;
    SHAPE ABUTMENT ;
    PORT
      LAYER M2 ;
      RECT 4.239 0.000 4.257 0.270 ;
    END
  END w0_wd_in[270]
  PIN w0_wd_in[271]
    DIRECTION INPUT ;
    USE SIGNAL ;
    SHAPE ABUTMENT ;
    PORT
      LAYER M2 ;
      RECT 4.527 0.000 4.545 0.270 ;
    END
  END w0_wd_in[271]
  PIN w0_wd_in[272]
    DIRECTION INPUT ;
    USE SIGNAL ;
    SHAPE ABUTMENT ;
    PORT
      LAYER M2 ;
      RECT 4.815 0.000 4.833 0.270 ;
    END
  END w0_wd_in[272]
  PIN w0_wd_in[273]
    DIRECTION INPUT ;
    USE SIGNAL ;
    SHAPE ABUTMENT ;
    PORT
      LAYER M2 ;
      RECT 5.103 0.000 5.121 0.270 ;
    END
  END w0_wd_in[273]
  PIN w0_wd_in[274]
    DIRECTION INPUT ;
    USE SIGNAL ;
    SHAPE ABUTMENT ;
    PORT
      LAYER M2 ;
      RECT 5.391 0.000 5.409 0.270 ;
    END
  END w0_wd_in[274]
  PIN w0_wd_in[275]
    DIRECTION INPUT ;
    USE SIGNAL ;
    SHAPE ABUTMENT ;
    PORT
      LAYER M2 ;
      RECT 5.679 0.000 5.697 0.270 ;
    END
  END w0_wd_in[275]
  PIN w0_wd_in[276]
    DIRECTION INPUT ;
    USE SIGNAL ;
    SHAPE ABUTMENT ;
    PORT
      LAYER M2 ;
      RECT 5.967 0.000 5.985 0.270 ;
    END
  END w0_wd_in[276]
  PIN w0_wd_in[277]
    DIRECTION INPUT ;
    USE SIGNAL ;
    SHAPE ABUTMENT ;
    PORT
      LAYER M2 ;
      RECT 6.255 0.000 6.273 0.270 ;
    END
  END w0_wd_in[277]
  PIN w0_wd_in[278]
    DIRECTION INPUT ;
    USE SIGNAL ;
    SHAPE ABUTMENT ;
    PORT
      LAYER M2 ;
      RECT 6.543 0.000 6.561 0.270 ;
    END
  END w0_wd_in[278]
  PIN w0_wd_in[279]
    DIRECTION INPUT ;
    USE SIGNAL ;
    SHAPE ABUTMENT ;
    PORT
      LAYER M2 ;
      RECT 6.831 0.000 6.849 0.270 ;
    END
  END w0_wd_in[279]
  PIN w0_wd_in[280]
    DIRECTION INPUT ;
    USE SIGNAL ;
    SHAPE ABUTMENT ;
    PORT
      LAYER M2 ;
      RECT 7.119 0.000 7.137 0.270 ;
    END
  END w0_wd_in[280]
  PIN w0_wd_in[281]
    DIRECTION INPUT ;
    USE SIGNAL ;
    SHAPE ABUTMENT ;
    PORT
      LAYER M2 ;
      RECT 7.407 0.000 7.425 0.270 ;
    END
  END w0_wd_in[281]
  PIN w0_wd_in[282]
    DIRECTION INPUT ;
    USE SIGNAL ;
    SHAPE ABUTMENT ;
    PORT
      LAYER M2 ;
      RECT 7.695 0.000 7.713 0.270 ;
    END
  END w0_wd_in[282]
  PIN w0_wd_in[283]
    DIRECTION INPUT ;
    USE SIGNAL ;
    SHAPE ABUTMENT ;
    PORT
      LAYER M2 ;
      RECT 7.983 0.000 8.001 0.270 ;
    END
  END w0_wd_in[283]
  PIN w0_wd_in[284]
    DIRECTION INPUT ;
    USE SIGNAL ;
    SHAPE ABUTMENT ;
    PORT
      LAYER M2 ;
      RECT 8.271 0.000 8.289 0.270 ;
    END
  END w0_wd_in[284]
  PIN w0_wd_in[285]
    DIRECTION INPUT ;
    USE SIGNAL ;
    SHAPE ABUTMENT ;
    PORT
      LAYER M2 ;
      RECT 8.559 0.000 8.577 0.270 ;
    END
  END w0_wd_in[285]
  PIN w0_wd_in[286]
    DIRECTION INPUT ;
    USE SIGNAL ;
    SHAPE ABUTMENT ;
    PORT
      LAYER M2 ;
      RECT 8.847 0.000 8.865 0.270 ;
    END
  END w0_wd_in[286]
  PIN w0_wd_in[287]
    DIRECTION INPUT ;
    USE SIGNAL ;
    SHAPE ABUTMENT ;
    PORT
      LAYER M2 ;
      RECT 9.135 0.000 9.153 0.270 ;
    END
  END w0_wd_in[287]
  PIN w0_wd_in[288]
    DIRECTION INPUT ;
    USE SIGNAL ;
    SHAPE ABUTMENT ;
    PORT
      LAYER M2 ;
      RECT 9.423 0.000 9.441 0.270 ;
    END
  END w0_wd_in[288]
  PIN w0_wd_in[289]
    DIRECTION INPUT ;
    USE SIGNAL ;
    SHAPE ABUTMENT ;
    PORT
      LAYER M2 ;
      RECT 9.711 0.000 9.729 0.270 ;
    END
  END w0_wd_in[289]
  PIN w0_wd_in[290]
    DIRECTION INPUT ;
    USE SIGNAL ;
    SHAPE ABUTMENT ;
    PORT
      LAYER M2 ;
      RECT 9.999 0.000 10.017 0.270 ;
    END
  END w0_wd_in[290]
  PIN w0_wd_in[291]
    DIRECTION INPUT ;
    USE SIGNAL ;
    SHAPE ABUTMENT ;
    PORT
      LAYER M2 ;
      RECT 10.287 0.000 10.305 0.270 ;
    END
  END w0_wd_in[291]
  PIN w0_wd_in[292]
    DIRECTION INPUT ;
    USE SIGNAL ;
    SHAPE ABUTMENT ;
    PORT
      LAYER M2 ;
      RECT 10.575 0.000 10.593 0.270 ;
    END
  END w0_wd_in[292]
  PIN w0_wd_in[293]
    DIRECTION INPUT ;
    USE SIGNAL ;
    SHAPE ABUTMENT ;
    PORT
      LAYER M2 ;
      RECT 10.863 0.000 10.881 0.270 ;
    END
  END w0_wd_in[293]
  PIN w0_wd_in[294]
    DIRECTION INPUT ;
    USE SIGNAL ;
    SHAPE ABUTMENT ;
    PORT
      LAYER M2 ;
      RECT 11.151 0.000 11.169 0.270 ;
    END
  END w0_wd_in[294]
  PIN w0_wd_in[295]
    DIRECTION INPUT ;
    USE SIGNAL ;
    SHAPE ABUTMENT ;
    PORT
      LAYER M2 ;
      RECT 11.439 0.000 11.457 0.270 ;
    END
  END w0_wd_in[295]
  PIN w0_wd_in[296]
    DIRECTION INPUT ;
    USE SIGNAL ;
    SHAPE ABUTMENT ;
    PORT
      LAYER M2 ;
      RECT 11.727 0.000 11.745 0.270 ;
    END
  END w0_wd_in[296]
  PIN w0_wd_in[297]
    DIRECTION INPUT ;
    USE SIGNAL ;
    SHAPE ABUTMENT ;
    PORT
      LAYER M2 ;
      RECT 12.015 0.000 12.033 0.270 ;
    END
  END w0_wd_in[297]
  PIN w0_wd_in[298]
    DIRECTION INPUT ;
    USE SIGNAL ;
    SHAPE ABUTMENT ;
    PORT
      LAYER M2 ;
      RECT 12.303 0.000 12.321 0.270 ;
    END
  END w0_wd_in[298]
  PIN w0_wd_in[299]
    DIRECTION INPUT ;
    USE SIGNAL ;
    SHAPE ABUTMENT ;
    PORT
      LAYER M2 ;
      RECT 12.591 0.000 12.609 0.270 ;
    END
  END w0_wd_in[299]
  PIN w0_wd_in[300]
    DIRECTION INPUT ;
    USE SIGNAL ;
    SHAPE ABUTMENT ;
    PORT
      LAYER M2 ;
      RECT 12.879 0.000 12.897 0.270 ;
    END
  END w0_wd_in[300]
  PIN w0_wd_in[301]
    DIRECTION INPUT ;
    USE SIGNAL ;
    SHAPE ABUTMENT ;
    PORT
      LAYER M2 ;
      RECT 13.167 0.000 13.185 0.270 ;
    END
  END w0_wd_in[301]
  PIN w0_wd_in[302]
    DIRECTION INPUT ;
    USE SIGNAL ;
    SHAPE ABUTMENT ;
    PORT
      LAYER M2 ;
      RECT 13.455 0.000 13.473 0.270 ;
    END
  END w0_wd_in[302]
  PIN w0_wd_in[303]
    DIRECTION INPUT ;
    USE SIGNAL ;
    SHAPE ABUTMENT ;
    PORT
      LAYER M2 ;
      RECT 13.743 0.000 13.761 0.270 ;
    END
  END w0_wd_in[303]
  PIN w0_wd_in[304]
    DIRECTION INPUT ;
    USE SIGNAL ;
    SHAPE ABUTMENT ;
    PORT
      LAYER M2 ;
      RECT 14.031 0.000 14.049 0.270 ;
    END
  END w0_wd_in[304]
  PIN w0_wd_in[305]
    DIRECTION INPUT ;
    USE SIGNAL ;
    SHAPE ABUTMENT ;
    PORT
      LAYER M2 ;
      RECT 14.319 0.000 14.337 0.270 ;
    END
  END w0_wd_in[305]
  PIN w0_wd_in[306]
    DIRECTION INPUT ;
    USE SIGNAL ;
    SHAPE ABUTMENT ;
    PORT
      LAYER M2 ;
      RECT 14.607 0.000 14.625 0.270 ;
    END
  END w0_wd_in[306]
  PIN w0_wd_in[307]
    DIRECTION INPUT ;
    USE SIGNAL ;
    SHAPE ABUTMENT ;
    PORT
      LAYER M2 ;
      RECT 14.895 0.000 14.913 0.270 ;
    END
  END w0_wd_in[307]
  PIN w0_wd_in[308]
    DIRECTION INPUT ;
    USE SIGNAL ;
    SHAPE ABUTMENT ;
    PORT
      LAYER M2 ;
      RECT 15.183 0.000 15.201 0.270 ;
    END
  END w0_wd_in[308]
  PIN w0_wd_in[309]
    DIRECTION INPUT ;
    USE SIGNAL ;
    SHAPE ABUTMENT ;
    PORT
      LAYER M2 ;
      RECT 15.471 0.000 15.489 0.270 ;
    END
  END w0_wd_in[309]
  PIN w0_wd_in[310]
    DIRECTION INPUT ;
    USE SIGNAL ;
    SHAPE ABUTMENT ;
    PORT
      LAYER M2 ;
      RECT 15.759 0.000 15.777 0.270 ;
    END
  END w0_wd_in[310]
  PIN w0_wd_in[311]
    DIRECTION INPUT ;
    USE SIGNAL ;
    SHAPE ABUTMENT ;
    PORT
      LAYER M2 ;
      RECT 16.047 0.000 16.065 0.270 ;
    END
  END w0_wd_in[311]
  PIN w0_wd_in[312]
    DIRECTION INPUT ;
    USE SIGNAL ;
    SHAPE ABUTMENT ;
    PORT
      LAYER M2 ;
      RECT 16.335 0.000 16.353 0.270 ;
    END
  END w0_wd_in[312]
  PIN w0_wd_in[313]
    DIRECTION INPUT ;
    USE SIGNAL ;
    SHAPE ABUTMENT ;
    PORT
      LAYER M2 ;
      RECT 16.623 0.000 16.641 0.270 ;
    END
  END w0_wd_in[313]
  PIN w0_wd_in[314]
    DIRECTION INPUT ;
    USE SIGNAL ;
    SHAPE ABUTMENT ;
    PORT
      LAYER M2 ;
      RECT 16.911 0.000 16.929 0.270 ;
    END
  END w0_wd_in[314]
  PIN w0_wd_in[315]
    DIRECTION INPUT ;
    USE SIGNAL ;
    SHAPE ABUTMENT ;
    PORT
      LAYER M2 ;
      RECT 17.199 0.000 17.217 0.270 ;
    END
  END w0_wd_in[315]
  PIN w0_wd_in[316]
    DIRECTION INPUT ;
    USE SIGNAL ;
    SHAPE ABUTMENT ;
    PORT
      LAYER M2 ;
      RECT 17.487 0.000 17.505 0.270 ;
    END
  END w0_wd_in[316]
  PIN w0_wd_in[317]
    DIRECTION INPUT ;
    USE SIGNAL ;
    SHAPE ABUTMENT ;
    PORT
      LAYER M2 ;
      RECT 17.775 0.000 17.793 0.270 ;
    END
  END w0_wd_in[317]
  PIN w0_wd_in[318]
    DIRECTION INPUT ;
    USE SIGNAL ;
    SHAPE ABUTMENT ;
    PORT
      LAYER M2 ;
      RECT 18.063 0.000 18.081 0.270 ;
    END
  END w0_wd_in[318]
  PIN w0_wd_in[319]
    DIRECTION INPUT ;
    USE SIGNAL ;
    SHAPE ABUTMENT ;
    PORT
      LAYER M2 ;
      RECT 18.351 0.000 18.369 0.270 ;
    END
  END w0_wd_in[319]
  PIN w0_wd_in[320]
    DIRECTION INPUT ;
    USE SIGNAL ;
    SHAPE ABUTMENT ;
    PORT
      LAYER M2 ;
      RECT 18.639 0.000 18.657 0.270 ;
    END
  END w0_wd_in[320]
  PIN w0_wd_in[321]
    DIRECTION INPUT ;
    USE SIGNAL ;
    SHAPE ABUTMENT ;
    PORT
      LAYER M2 ;
      RECT 18.927 0.000 18.945 0.270 ;
    END
  END w0_wd_in[321]
  PIN w0_wd_in[322]
    DIRECTION INPUT ;
    USE SIGNAL ;
    SHAPE ABUTMENT ;
    PORT
      LAYER M2 ;
      RECT 19.215 0.000 19.233 0.270 ;
    END
  END w0_wd_in[322]
  PIN w0_wd_in[323]
    DIRECTION INPUT ;
    USE SIGNAL ;
    SHAPE ABUTMENT ;
    PORT
      LAYER M2 ;
      RECT 19.503 0.000 19.521 0.270 ;
    END
  END w0_wd_in[323]
  PIN w0_wd_in[324]
    DIRECTION INPUT ;
    USE SIGNAL ;
    SHAPE ABUTMENT ;
    PORT
      LAYER M2 ;
      RECT 19.791 0.000 19.809 0.270 ;
    END
  END w0_wd_in[324]
  PIN w0_wd_in[325]
    DIRECTION INPUT ;
    USE SIGNAL ;
    SHAPE ABUTMENT ;
    PORT
      LAYER M2 ;
      RECT 20.079 0.000 20.097 0.270 ;
    END
  END w0_wd_in[325]
  PIN w0_wd_in[326]
    DIRECTION INPUT ;
    USE SIGNAL ;
    SHAPE ABUTMENT ;
    PORT
      LAYER M2 ;
      RECT 20.367 0.000 20.385 0.270 ;
    END
  END w0_wd_in[326]
  PIN w0_wd_in[327]
    DIRECTION INPUT ;
    USE SIGNAL ;
    SHAPE ABUTMENT ;
    PORT
      LAYER M2 ;
      RECT 20.655 0.000 20.673 0.270 ;
    END
  END w0_wd_in[327]
  PIN w0_wd_in[328]
    DIRECTION INPUT ;
    USE SIGNAL ;
    SHAPE ABUTMENT ;
    PORT
      LAYER M2 ;
      RECT 20.943 0.000 20.961 0.270 ;
    END
  END w0_wd_in[328]
  PIN w0_wd_in[329]
    DIRECTION INPUT ;
    USE SIGNAL ;
    SHAPE ABUTMENT ;
    PORT
      LAYER M2 ;
      RECT 21.231 0.000 21.249 0.270 ;
    END
  END w0_wd_in[329]
  PIN w0_wd_in[330]
    DIRECTION INPUT ;
    USE SIGNAL ;
    SHAPE ABUTMENT ;
    PORT
      LAYER M2 ;
      RECT 21.519 0.000 21.537 0.270 ;
    END
  END w0_wd_in[330]
  PIN w0_wd_in[331]
    DIRECTION INPUT ;
    USE SIGNAL ;
    SHAPE ABUTMENT ;
    PORT
      LAYER M2 ;
      RECT 21.807 0.000 21.825 0.270 ;
    END
  END w0_wd_in[331]
  PIN w0_wd_in[332]
    DIRECTION INPUT ;
    USE SIGNAL ;
    SHAPE ABUTMENT ;
    PORT
      LAYER M2 ;
      RECT 22.095 0.000 22.113 0.270 ;
    END
  END w0_wd_in[332]
  PIN w0_wd_in[333]
    DIRECTION INPUT ;
    USE SIGNAL ;
    SHAPE ABUTMENT ;
    PORT
      LAYER M2 ;
      RECT 22.383 0.000 22.401 0.270 ;
    END
  END w0_wd_in[333]
  PIN w0_wd_in[334]
    DIRECTION INPUT ;
    USE SIGNAL ;
    SHAPE ABUTMENT ;
    PORT
      LAYER M2 ;
      RECT 22.671 0.000 22.689 0.270 ;
    END
  END w0_wd_in[334]
  PIN w0_wd_in[335]
    DIRECTION INPUT ;
    USE SIGNAL ;
    SHAPE ABUTMENT ;
    PORT
      LAYER M2 ;
      RECT 22.959 0.000 22.977 0.270 ;
    END
  END w0_wd_in[335]
  PIN w0_wd_in[336]
    DIRECTION INPUT ;
    USE SIGNAL ;
    SHAPE ABUTMENT ;
    PORT
      LAYER M2 ;
      RECT 23.247 0.000 23.265 0.270 ;
    END
  END w0_wd_in[336]
  PIN w0_wd_in[337]
    DIRECTION INPUT ;
    USE SIGNAL ;
    SHAPE ABUTMENT ;
    PORT
      LAYER M2 ;
      RECT 23.535 0.000 23.553 0.270 ;
    END
  END w0_wd_in[337]
  PIN w0_wd_in[338]
    DIRECTION INPUT ;
    USE SIGNAL ;
    SHAPE ABUTMENT ;
    PORT
      LAYER M2 ;
      RECT 23.823 0.000 23.841 0.270 ;
    END
  END w0_wd_in[338]
  PIN w0_wd_in[339]
    DIRECTION INPUT ;
    USE SIGNAL ;
    SHAPE ABUTMENT ;
    PORT
      LAYER M2 ;
      RECT 24.111 0.000 24.129 0.270 ;
    END
  END w0_wd_in[339]
  PIN w0_wd_in[340]
    DIRECTION INPUT ;
    USE SIGNAL ;
    SHAPE ABUTMENT ;
    PORT
      LAYER M2 ;
      RECT 24.399 0.000 24.417 0.270 ;
    END
  END w0_wd_in[340]
  PIN w0_wd_in[341]
    DIRECTION INPUT ;
    USE SIGNAL ;
    SHAPE ABUTMENT ;
    PORT
      LAYER M2 ;
      RECT 24.687 0.000 24.705 0.270 ;
    END
  END w0_wd_in[341]
  PIN w0_wd_in[342]
    DIRECTION INPUT ;
    USE SIGNAL ;
    SHAPE ABUTMENT ;
    PORT
      LAYER M2 ;
      RECT 24.975 0.000 24.993 0.270 ;
    END
  END w0_wd_in[342]
  PIN w0_wd_in[343]
    DIRECTION INPUT ;
    USE SIGNAL ;
    SHAPE ABUTMENT ;
    PORT
      LAYER M2 ;
      RECT 25.263 0.000 25.281 0.270 ;
    END
  END w0_wd_in[343]
  PIN w0_wd_in[344]
    DIRECTION INPUT ;
    USE SIGNAL ;
    SHAPE ABUTMENT ;
    PORT
      LAYER M2 ;
      RECT 25.551 0.000 25.569 0.270 ;
    END
  END w0_wd_in[344]
  PIN w0_wd_in[345]
    DIRECTION INPUT ;
    USE SIGNAL ;
    SHAPE ABUTMENT ;
    PORT
      LAYER M2 ;
      RECT 25.839 0.000 25.857 0.270 ;
    END
  END w0_wd_in[345]
  PIN w0_wd_in[346]
    DIRECTION INPUT ;
    USE SIGNAL ;
    SHAPE ABUTMENT ;
    PORT
      LAYER M2 ;
      RECT 26.127 0.000 26.145 0.270 ;
    END
  END w0_wd_in[346]
  PIN w0_wd_in[347]
    DIRECTION INPUT ;
    USE SIGNAL ;
    SHAPE ABUTMENT ;
    PORT
      LAYER M2 ;
      RECT 26.415 0.000 26.433 0.270 ;
    END
  END w0_wd_in[347]
  PIN w0_wd_in[348]
    DIRECTION INPUT ;
    USE SIGNAL ;
    SHAPE ABUTMENT ;
    PORT
      LAYER M2 ;
      RECT 26.703 0.000 26.721 0.270 ;
    END
  END w0_wd_in[348]
  PIN w0_wd_in[349]
    DIRECTION INPUT ;
    USE SIGNAL ;
    SHAPE ABUTMENT ;
    PORT
      LAYER M2 ;
      RECT 26.991 0.000 27.009 0.270 ;
    END
  END w0_wd_in[349]
  PIN w0_wd_in[350]
    DIRECTION INPUT ;
    USE SIGNAL ;
    SHAPE ABUTMENT ;
    PORT
      LAYER M2 ;
      RECT 27.279 0.000 27.297 0.270 ;
    END
  END w0_wd_in[350]
  PIN w0_wd_in[351]
    DIRECTION INPUT ;
    USE SIGNAL ;
    SHAPE ABUTMENT ;
    PORT
      LAYER M2 ;
      RECT 27.567 0.000 27.585 0.270 ;
    END
  END w0_wd_in[351]
  PIN w0_wd_in[352]
    DIRECTION INPUT ;
    USE SIGNAL ;
    SHAPE ABUTMENT ;
    PORT
      LAYER M2 ;
      RECT 27.855 0.000 27.873 0.270 ;
    END
  END w0_wd_in[352]
  PIN w0_wd_in[353]
    DIRECTION INPUT ;
    USE SIGNAL ;
    SHAPE ABUTMENT ;
    PORT
      LAYER M2 ;
      RECT 28.143 0.000 28.161 0.270 ;
    END
  END w0_wd_in[353]
  PIN w0_wd_in[354]
    DIRECTION INPUT ;
    USE SIGNAL ;
    SHAPE ABUTMENT ;
    PORT
      LAYER M2 ;
      RECT 28.431 0.000 28.449 0.270 ;
    END
  END w0_wd_in[354]
  PIN w0_wd_in[355]
    DIRECTION INPUT ;
    USE SIGNAL ;
    SHAPE ABUTMENT ;
    PORT
      LAYER M2 ;
      RECT 28.719 0.000 28.737 0.270 ;
    END
  END w0_wd_in[355]
  PIN w0_wd_in[356]
    DIRECTION INPUT ;
    USE SIGNAL ;
    SHAPE ABUTMENT ;
    PORT
      LAYER M2 ;
      RECT 29.007 0.000 29.025 0.270 ;
    END
  END w0_wd_in[356]
  PIN w0_wd_in[357]
    DIRECTION INPUT ;
    USE SIGNAL ;
    SHAPE ABUTMENT ;
    PORT
      LAYER M2 ;
      RECT 29.295 0.000 29.313 0.270 ;
    END
  END w0_wd_in[357]
  PIN w0_wd_in[358]
    DIRECTION INPUT ;
    USE SIGNAL ;
    SHAPE ABUTMENT ;
    PORT
      LAYER M2 ;
      RECT 29.583 0.000 29.601 0.270 ;
    END
  END w0_wd_in[358]
  PIN w0_wd_in[359]
    DIRECTION INPUT ;
    USE SIGNAL ;
    SHAPE ABUTMENT ;
    PORT
      LAYER M2 ;
      RECT 29.871 0.000 29.889 0.270 ;
    END
  END w0_wd_in[359]
  PIN w0_wd_in[360]
    DIRECTION INPUT ;
    USE SIGNAL ;
    SHAPE ABUTMENT ;
    PORT
      LAYER M2 ;
      RECT 30.159 0.000 30.177 0.270 ;
    END
  END w0_wd_in[360]
  PIN w0_wd_in[361]
    DIRECTION INPUT ;
    USE SIGNAL ;
    SHAPE ABUTMENT ;
    PORT
      LAYER M2 ;
      RECT 30.447 0.000 30.465 0.270 ;
    END
  END w0_wd_in[361]
  PIN w0_wd_in[362]
    DIRECTION INPUT ;
    USE SIGNAL ;
    SHAPE ABUTMENT ;
    PORT
      LAYER M2 ;
      RECT 30.735 0.000 30.753 0.270 ;
    END
  END w0_wd_in[362]
  PIN w0_wd_in[363]
    DIRECTION INPUT ;
    USE SIGNAL ;
    SHAPE ABUTMENT ;
    PORT
      LAYER M2 ;
      RECT 31.023 0.000 31.041 0.270 ;
    END
  END w0_wd_in[363]
  PIN w0_wd_in[364]
    DIRECTION INPUT ;
    USE SIGNAL ;
    SHAPE ABUTMENT ;
    PORT
      LAYER M2 ;
      RECT 31.311 0.000 31.329 0.270 ;
    END
  END w0_wd_in[364]
  PIN w0_wd_in[365]
    DIRECTION INPUT ;
    USE SIGNAL ;
    SHAPE ABUTMENT ;
    PORT
      LAYER M2 ;
      RECT 31.599 0.000 31.617 0.270 ;
    END
  END w0_wd_in[365]
  PIN w0_wd_in[366]
    DIRECTION INPUT ;
    USE SIGNAL ;
    SHAPE ABUTMENT ;
    PORT
      LAYER M2 ;
      RECT 31.887 0.000 31.905 0.270 ;
    END
  END w0_wd_in[366]
  PIN w0_wd_in[367]
    DIRECTION INPUT ;
    USE SIGNAL ;
    SHAPE ABUTMENT ;
    PORT
      LAYER M2 ;
      RECT 32.175 0.000 32.193 0.270 ;
    END
  END w0_wd_in[367]
  PIN w0_wd_in[368]
    DIRECTION INPUT ;
    USE SIGNAL ;
    SHAPE ABUTMENT ;
    PORT
      LAYER M2 ;
      RECT 32.463 0.000 32.481 0.270 ;
    END
  END w0_wd_in[368]
  PIN w0_wd_in[369]
    DIRECTION INPUT ;
    USE SIGNAL ;
    SHAPE ABUTMENT ;
    PORT
      LAYER M2 ;
      RECT 32.751 0.000 32.769 0.270 ;
    END
  END w0_wd_in[369]
  PIN w0_wd_in[370]
    DIRECTION INPUT ;
    USE SIGNAL ;
    SHAPE ABUTMENT ;
    PORT
      LAYER M2 ;
      RECT 33.039 0.000 33.057 0.270 ;
    END
  END w0_wd_in[370]
  PIN w0_wd_in[371]
    DIRECTION INPUT ;
    USE SIGNAL ;
    SHAPE ABUTMENT ;
    PORT
      LAYER M2 ;
      RECT 33.327 0.000 33.345 0.270 ;
    END
  END w0_wd_in[371]
  PIN w0_wd_in[372]
    DIRECTION INPUT ;
    USE SIGNAL ;
    SHAPE ABUTMENT ;
    PORT
      LAYER M2 ;
      RECT 33.615 0.000 33.633 0.270 ;
    END
  END w0_wd_in[372]
  PIN w0_wd_in[373]
    DIRECTION INPUT ;
    USE SIGNAL ;
    SHAPE ABUTMENT ;
    PORT
      LAYER M2 ;
      RECT 33.903 0.000 33.921 0.270 ;
    END
  END w0_wd_in[373]
  PIN w0_wd_in[374]
    DIRECTION INPUT ;
    USE SIGNAL ;
    SHAPE ABUTMENT ;
    PORT
      LAYER M2 ;
      RECT 34.191 0.000 34.209 0.270 ;
    END
  END w0_wd_in[374]
  PIN w0_wd_in[375]
    DIRECTION INPUT ;
    USE SIGNAL ;
    SHAPE ABUTMENT ;
    PORT
      LAYER M2 ;
      RECT 34.479 0.000 34.497 0.270 ;
    END
  END w0_wd_in[375]
  PIN w0_wd_in[376]
    DIRECTION INPUT ;
    USE SIGNAL ;
    SHAPE ABUTMENT ;
    PORT
      LAYER M2 ;
      RECT 34.767 0.000 34.785 0.270 ;
    END
  END w0_wd_in[376]
  PIN w0_wd_in[377]
    DIRECTION INPUT ;
    USE SIGNAL ;
    SHAPE ABUTMENT ;
    PORT
      LAYER M2 ;
      RECT 35.055 0.000 35.073 0.270 ;
    END
  END w0_wd_in[377]
  PIN w0_wd_in[378]
    DIRECTION INPUT ;
    USE SIGNAL ;
    SHAPE ABUTMENT ;
    PORT
      LAYER M2 ;
      RECT 35.343 0.000 35.361 0.270 ;
    END
  END w0_wd_in[378]
  PIN w0_wd_in[379]
    DIRECTION INPUT ;
    USE SIGNAL ;
    SHAPE ABUTMENT ;
    PORT
      LAYER M2 ;
      RECT 35.631 0.000 35.649 0.270 ;
    END
  END w0_wd_in[379]
  PIN w0_wd_in[380]
    DIRECTION INPUT ;
    USE SIGNAL ;
    SHAPE ABUTMENT ;
    PORT
      LAYER M2 ;
      RECT 35.919 0.000 35.937 0.270 ;
    END
  END w0_wd_in[380]
  PIN w0_wd_in[381]
    DIRECTION INPUT ;
    USE SIGNAL ;
    SHAPE ABUTMENT ;
    PORT
      LAYER M2 ;
      RECT 36.207 0.000 36.225 0.270 ;
    END
  END w0_wd_in[381]
  PIN w0_wd_in[382]
    DIRECTION INPUT ;
    USE SIGNAL ;
    SHAPE ABUTMENT ;
    PORT
      LAYER M2 ;
      RECT 36.495 0.000 36.513 0.270 ;
    END
  END w0_wd_in[382]
  PIN w0_wd_in[383]
    DIRECTION INPUT ;
    USE SIGNAL ;
    SHAPE ABUTMENT ;
    PORT
      LAYER M2 ;
      RECT 36.783 0.000 36.801 0.270 ;
    END
  END w0_wd_in[383]
  PIN w0_wd_in[384]
    DIRECTION INPUT ;
    USE SIGNAL ;
    SHAPE ABUTMENT ;
    PORT
      LAYER M2 ;
      RECT 37.071 0.000 37.089 0.270 ;
    END
  END w0_wd_in[384]
  PIN w0_wd_in[385]
    DIRECTION INPUT ;
    USE SIGNAL ;
    SHAPE ABUTMENT ;
    PORT
      LAYER M2 ;
      RECT 37.359 0.000 37.377 0.270 ;
    END
  END w0_wd_in[385]
  PIN w0_wd_in[386]
    DIRECTION INPUT ;
    USE SIGNAL ;
    SHAPE ABUTMENT ;
    PORT
      LAYER M2 ;
      RECT 37.647 0.000 37.665 0.270 ;
    END
  END w0_wd_in[386]
  PIN w0_wd_in[387]
    DIRECTION INPUT ;
    USE SIGNAL ;
    SHAPE ABUTMENT ;
    PORT
      LAYER M2 ;
      RECT 37.935 0.000 37.953 0.270 ;
    END
  END w0_wd_in[387]
  PIN w0_wd_in[388]
    DIRECTION INPUT ;
    USE SIGNAL ;
    SHAPE ABUTMENT ;
    PORT
      LAYER M2 ;
      RECT 38.223 0.000 38.241 0.270 ;
    END
  END w0_wd_in[388]
  PIN w0_wd_in[389]
    DIRECTION INPUT ;
    USE SIGNAL ;
    SHAPE ABUTMENT ;
    PORT
      LAYER M2 ;
      RECT 38.511 0.000 38.529 0.270 ;
    END
  END w0_wd_in[389]
  PIN w0_wd_in[390]
    DIRECTION INPUT ;
    USE SIGNAL ;
    SHAPE ABUTMENT ;
    PORT
      LAYER M2 ;
      RECT 38.799 0.000 38.817 0.270 ;
    END
  END w0_wd_in[390]
  PIN w0_wd_in[391]
    DIRECTION INPUT ;
    USE SIGNAL ;
    SHAPE ABUTMENT ;
    PORT
      LAYER M2 ;
      RECT 39.087 0.000 39.105 0.270 ;
    END
  END w0_wd_in[391]
  PIN w0_wd_in[392]
    DIRECTION INPUT ;
    USE SIGNAL ;
    SHAPE ABUTMENT ;
    PORT
      LAYER M2 ;
      RECT 39.375 0.000 39.393 0.270 ;
    END
  END w0_wd_in[392]
  PIN w0_wd_in[393]
    DIRECTION INPUT ;
    USE SIGNAL ;
    SHAPE ABUTMENT ;
    PORT
      LAYER M2 ;
      RECT 39.663 0.000 39.681 0.270 ;
    END
  END w0_wd_in[393]
  PIN w0_wd_in[394]
    DIRECTION INPUT ;
    USE SIGNAL ;
    SHAPE ABUTMENT ;
    PORT
      LAYER M2 ;
      RECT 39.951 0.000 39.969 0.270 ;
    END
  END w0_wd_in[394]
  PIN w0_wd_in[395]
    DIRECTION INPUT ;
    USE SIGNAL ;
    SHAPE ABUTMENT ;
    PORT
      LAYER M2 ;
      RECT 40.239 0.000 40.257 0.270 ;
    END
  END w0_wd_in[395]
  PIN w0_wd_in[396]
    DIRECTION INPUT ;
    USE SIGNAL ;
    SHAPE ABUTMENT ;
    PORT
      LAYER M2 ;
      RECT 40.527 0.000 40.545 0.270 ;
    END
  END w0_wd_in[396]
  PIN w0_wd_in[397]
    DIRECTION INPUT ;
    USE SIGNAL ;
    SHAPE ABUTMENT ;
    PORT
      LAYER M2 ;
      RECT 40.815 0.000 40.833 0.270 ;
    END
  END w0_wd_in[397]
  PIN w0_wd_in[398]
    DIRECTION INPUT ;
    USE SIGNAL ;
    SHAPE ABUTMENT ;
    PORT
      LAYER M2 ;
      RECT 41.103 0.000 41.121 0.270 ;
    END
  END w0_wd_in[398]
  PIN w0_wd_in[399]
    DIRECTION INPUT ;
    USE SIGNAL ;
    SHAPE ABUTMENT ;
    PORT
      LAYER M2 ;
      RECT 41.391 0.000 41.409 0.270 ;
    END
  END w0_wd_in[399]
  PIN w0_wd_in[400]
    DIRECTION INPUT ;
    USE SIGNAL ;
    SHAPE ABUTMENT ;
    PORT
      LAYER M2 ;
      RECT 41.679 0.000 41.697 0.270 ;
    END
  END w0_wd_in[400]
  PIN w0_wd_in[401]
    DIRECTION INPUT ;
    USE SIGNAL ;
    SHAPE ABUTMENT ;
    PORT
      LAYER M2 ;
      RECT 41.967 0.000 41.985 0.270 ;
    END
  END w0_wd_in[401]
  PIN w0_wd_in[402]
    DIRECTION INPUT ;
    USE SIGNAL ;
    SHAPE ABUTMENT ;
    PORT
      LAYER M2 ;
      RECT 42.255 0.000 42.273 0.270 ;
    END
  END w0_wd_in[402]
  PIN w0_wd_in[403]
    DIRECTION INPUT ;
    USE SIGNAL ;
    SHAPE ABUTMENT ;
    PORT
      LAYER M2 ;
      RECT 42.543 0.000 42.561 0.270 ;
    END
  END w0_wd_in[403]
  PIN w0_wd_in[404]
    DIRECTION INPUT ;
    USE SIGNAL ;
    SHAPE ABUTMENT ;
    PORT
      LAYER M2 ;
      RECT 42.831 0.000 42.849 0.270 ;
    END
  END w0_wd_in[404]
  PIN w0_wd_in[405]
    DIRECTION INPUT ;
    USE SIGNAL ;
    SHAPE ABUTMENT ;
    PORT
      LAYER M2 ;
      RECT 43.119 0.000 43.137 0.270 ;
    END
  END w0_wd_in[405]
  PIN w0_wd_in[406]
    DIRECTION INPUT ;
    USE SIGNAL ;
    SHAPE ABUTMENT ;
    PORT
      LAYER M2 ;
      RECT 43.407 0.000 43.425 0.270 ;
    END
  END w0_wd_in[406]
  PIN w0_wd_in[407]
    DIRECTION INPUT ;
    USE SIGNAL ;
    SHAPE ABUTMENT ;
    PORT
      LAYER M2 ;
      RECT 43.695 0.000 43.713 0.270 ;
    END
  END w0_wd_in[407]
  PIN w0_wd_in[408]
    DIRECTION INPUT ;
    USE SIGNAL ;
    SHAPE ABUTMENT ;
    PORT
      LAYER M2 ;
      RECT 43.983 0.000 44.001 0.270 ;
    END
  END w0_wd_in[408]
  PIN w0_wd_in[409]
    DIRECTION INPUT ;
    USE SIGNAL ;
    SHAPE ABUTMENT ;
    PORT
      LAYER M2 ;
      RECT 44.271 0.000 44.289 0.270 ;
    END
  END w0_wd_in[409]
  PIN w0_wd_in[410]
    DIRECTION INPUT ;
    USE SIGNAL ;
    SHAPE ABUTMENT ;
    PORT
      LAYER M2 ;
      RECT 44.559 0.000 44.577 0.270 ;
    END
  END w0_wd_in[410]
  PIN w0_wd_in[411]
    DIRECTION INPUT ;
    USE SIGNAL ;
    SHAPE ABUTMENT ;
    PORT
      LAYER M2 ;
      RECT 44.847 0.000 44.865 0.270 ;
    END
  END w0_wd_in[411]
  PIN w0_wd_in[412]
    DIRECTION INPUT ;
    USE SIGNAL ;
    SHAPE ABUTMENT ;
    PORT
      LAYER M2 ;
      RECT 45.135 0.000 45.153 0.270 ;
    END
  END w0_wd_in[412]
  PIN w0_wd_in[413]
    DIRECTION INPUT ;
    USE SIGNAL ;
    SHAPE ABUTMENT ;
    PORT
      LAYER M2 ;
      RECT 45.423 0.000 45.441 0.270 ;
    END
  END w0_wd_in[413]
  PIN w0_wd_in[414]
    DIRECTION INPUT ;
    USE SIGNAL ;
    SHAPE ABUTMENT ;
    PORT
      LAYER M2 ;
      RECT 45.711 0.000 45.729 0.270 ;
    END
  END w0_wd_in[414]
  PIN w0_wd_in[415]
    DIRECTION INPUT ;
    USE SIGNAL ;
    SHAPE ABUTMENT ;
    PORT
      LAYER M2 ;
      RECT 45.999 0.000 46.017 0.270 ;
    END
  END w0_wd_in[415]
  PIN w0_wd_in[416]
    DIRECTION INPUT ;
    USE SIGNAL ;
    SHAPE ABUTMENT ;
    PORT
      LAYER M2 ;
      RECT 46.287 0.000 46.305 0.270 ;
    END
  END w0_wd_in[416]
  PIN w0_wd_in[417]
    DIRECTION INPUT ;
    USE SIGNAL ;
    SHAPE ABUTMENT ;
    PORT
      LAYER M2 ;
      RECT 46.575 0.000 46.593 0.270 ;
    END
  END w0_wd_in[417]
  PIN w0_wd_in[418]
    DIRECTION INPUT ;
    USE SIGNAL ;
    SHAPE ABUTMENT ;
    PORT
      LAYER M2 ;
      RECT 46.863 0.000 46.881 0.270 ;
    END
  END w0_wd_in[418]
  PIN w0_wd_in[419]
    DIRECTION INPUT ;
    USE SIGNAL ;
    SHAPE ABUTMENT ;
    PORT
      LAYER M2 ;
      RECT 47.151 0.000 47.169 0.270 ;
    END
  END w0_wd_in[419]
  PIN w0_wd_in[420]
    DIRECTION INPUT ;
    USE SIGNAL ;
    SHAPE ABUTMENT ;
    PORT
      LAYER M2 ;
      RECT 47.439 0.000 47.457 0.270 ;
    END
  END w0_wd_in[420]
  PIN w0_wd_in[421]
    DIRECTION INPUT ;
    USE SIGNAL ;
    SHAPE ABUTMENT ;
    PORT
      LAYER M2 ;
      RECT 47.727 0.000 47.745 0.270 ;
    END
  END w0_wd_in[421]
  PIN w0_wd_in[422]
    DIRECTION INPUT ;
    USE SIGNAL ;
    SHAPE ABUTMENT ;
    PORT
      LAYER M2 ;
      RECT 48.015 0.000 48.033 0.270 ;
    END
  END w0_wd_in[422]
  PIN w0_wd_in[423]
    DIRECTION INPUT ;
    USE SIGNAL ;
    SHAPE ABUTMENT ;
    PORT
      LAYER M2 ;
      RECT 48.303 0.000 48.321 0.270 ;
    END
  END w0_wd_in[423]
  PIN w0_wd_in[424]
    DIRECTION INPUT ;
    USE SIGNAL ;
    SHAPE ABUTMENT ;
    PORT
      LAYER M2 ;
      RECT 48.591 0.000 48.609 0.270 ;
    END
  END w0_wd_in[424]
  PIN w0_wd_in[425]
    DIRECTION INPUT ;
    USE SIGNAL ;
    SHAPE ABUTMENT ;
    PORT
      LAYER M2 ;
      RECT 48.879 0.000 48.897 0.270 ;
    END
  END w0_wd_in[425]
  PIN w0_wd_in[426]
    DIRECTION INPUT ;
    USE SIGNAL ;
    SHAPE ABUTMENT ;
    PORT
      LAYER M2 ;
      RECT 49.167 0.000 49.185 0.270 ;
    END
  END w0_wd_in[426]
  PIN w0_wd_in[427]
    DIRECTION INPUT ;
    USE SIGNAL ;
    SHAPE ABUTMENT ;
    PORT
      LAYER M2 ;
      RECT 49.455 0.000 49.473 0.270 ;
    END
  END w0_wd_in[427]
  PIN w0_wd_in[428]
    DIRECTION INPUT ;
    USE SIGNAL ;
    SHAPE ABUTMENT ;
    PORT
      LAYER M2 ;
      RECT 49.743 0.000 49.761 0.270 ;
    END
  END w0_wd_in[428]
  PIN w0_wd_in[429]
    DIRECTION INPUT ;
    USE SIGNAL ;
    SHAPE ABUTMENT ;
    PORT
      LAYER M2 ;
      RECT 50.031 0.000 50.049 0.270 ;
    END
  END w0_wd_in[429]
  PIN w0_wd_in[430]
    DIRECTION INPUT ;
    USE SIGNAL ;
    SHAPE ABUTMENT ;
    PORT
      LAYER M2 ;
      RECT 50.319 0.000 50.337 0.270 ;
    END
  END w0_wd_in[430]
  PIN w0_wd_in[431]
    DIRECTION INPUT ;
    USE SIGNAL ;
    SHAPE ABUTMENT ;
    PORT
      LAYER M2 ;
      RECT 50.607 0.000 50.625 0.270 ;
    END
  END w0_wd_in[431]
  PIN w0_wd_in[432]
    DIRECTION INPUT ;
    USE SIGNAL ;
    SHAPE ABUTMENT ;
    PORT
      LAYER M2 ;
      RECT 50.895 0.000 50.913 0.270 ;
    END
  END w0_wd_in[432]
  PIN w0_wd_in[433]
    DIRECTION INPUT ;
    USE SIGNAL ;
    SHAPE ABUTMENT ;
    PORT
      LAYER M2 ;
      RECT 51.183 0.000 51.201 0.270 ;
    END
  END w0_wd_in[433]
  PIN w0_wd_in[434]
    DIRECTION INPUT ;
    USE SIGNAL ;
    SHAPE ABUTMENT ;
    PORT
      LAYER M2 ;
      RECT 51.471 0.000 51.489 0.270 ;
    END
  END w0_wd_in[434]
  PIN w0_wd_in[435]
    DIRECTION INPUT ;
    USE SIGNAL ;
    SHAPE ABUTMENT ;
    PORT
      LAYER M2 ;
      RECT 51.759 0.000 51.777 0.270 ;
    END
  END w0_wd_in[435]
  PIN w0_wd_in[436]
    DIRECTION INPUT ;
    USE SIGNAL ;
    SHAPE ABUTMENT ;
    PORT
      LAYER M2 ;
      RECT 52.047 0.000 52.065 0.270 ;
    END
  END w0_wd_in[436]
  PIN w0_wd_in[437]
    DIRECTION INPUT ;
    USE SIGNAL ;
    SHAPE ABUTMENT ;
    PORT
      LAYER M2 ;
      RECT 52.335 0.000 52.353 0.270 ;
    END
  END w0_wd_in[437]
  PIN w0_wd_in[438]
    DIRECTION INPUT ;
    USE SIGNAL ;
    SHAPE ABUTMENT ;
    PORT
      LAYER M2 ;
      RECT 52.623 0.000 52.641 0.270 ;
    END
  END w0_wd_in[438]
  PIN w0_wd_in[439]
    DIRECTION INPUT ;
    USE SIGNAL ;
    SHAPE ABUTMENT ;
    PORT
      LAYER M2 ;
      RECT 52.911 0.000 52.929 0.270 ;
    END
  END w0_wd_in[439]
  PIN w0_wd_in[440]
    DIRECTION INPUT ;
    USE SIGNAL ;
    SHAPE ABUTMENT ;
    PORT
      LAYER M2 ;
      RECT 53.199 0.000 53.217 0.270 ;
    END
  END w0_wd_in[440]
  PIN w0_wd_in[441]
    DIRECTION INPUT ;
    USE SIGNAL ;
    SHAPE ABUTMENT ;
    PORT
      LAYER M2 ;
      RECT 53.487 0.000 53.505 0.270 ;
    END
  END w0_wd_in[441]
  PIN w0_wd_in[442]
    DIRECTION INPUT ;
    USE SIGNAL ;
    SHAPE ABUTMENT ;
    PORT
      LAYER M2 ;
      RECT 53.775 0.000 53.793 0.270 ;
    END
  END w0_wd_in[442]
  PIN w0_wd_in[443]
    DIRECTION INPUT ;
    USE SIGNAL ;
    SHAPE ABUTMENT ;
    PORT
      LAYER M2 ;
      RECT 54.063 0.000 54.081 0.270 ;
    END
  END w0_wd_in[443]
  PIN w0_wd_in[444]
    DIRECTION INPUT ;
    USE SIGNAL ;
    SHAPE ABUTMENT ;
    PORT
      LAYER M2 ;
      RECT 54.351 0.000 54.369 0.270 ;
    END
  END w0_wd_in[444]
  PIN w0_wd_in[445]
    DIRECTION INPUT ;
    USE SIGNAL ;
    SHAPE ABUTMENT ;
    PORT
      LAYER M2 ;
      RECT 54.639 0.000 54.657 0.270 ;
    END
  END w0_wd_in[445]
  PIN w0_wd_in[446]
    DIRECTION INPUT ;
    USE SIGNAL ;
    SHAPE ABUTMENT ;
    PORT
      LAYER M2 ;
      RECT 54.927 0.000 54.945 0.270 ;
    END
  END w0_wd_in[446]
  PIN w0_wd_in[447]
    DIRECTION INPUT ;
    USE SIGNAL ;
    SHAPE ABUTMENT ;
    PORT
      LAYER M2 ;
      RECT 55.215 0.000 55.233 0.270 ;
    END
  END w0_wd_in[447]
  PIN w0_wd_in[448]
    DIRECTION INPUT ;
    USE SIGNAL ;
    SHAPE ABUTMENT ;
    PORT
      LAYER M2 ;
      RECT 55.503 0.000 55.521 0.270 ;
    END
  END w0_wd_in[448]
  PIN w0_wd_in[449]
    DIRECTION INPUT ;
    USE SIGNAL ;
    SHAPE ABUTMENT ;
    PORT
      LAYER M2 ;
      RECT 55.791 0.000 55.809 0.270 ;
    END
  END w0_wd_in[449]
  PIN w0_wd_in[450]
    DIRECTION INPUT ;
    USE SIGNAL ;
    SHAPE ABUTMENT ;
    PORT
      LAYER M2 ;
      RECT 56.079 0.000 56.097 0.270 ;
    END
  END w0_wd_in[450]
  PIN w0_wd_in[451]
    DIRECTION INPUT ;
    USE SIGNAL ;
    SHAPE ABUTMENT ;
    PORT
      LAYER M2 ;
      RECT 56.367 0.000 56.385 0.270 ;
    END
  END w0_wd_in[451]
  PIN w0_wd_in[452]
    DIRECTION INPUT ;
    USE SIGNAL ;
    SHAPE ABUTMENT ;
    PORT
      LAYER M2 ;
      RECT 56.655 0.000 56.673 0.270 ;
    END
  END w0_wd_in[452]
  PIN w0_wd_in[453]
    DIRECTION INPUT ;
    USE SIGNAL ;
    SHAPE ABUTMENT ;
    PORT
      LAYER M2 ;
      RECT 56.943 0.000 56.961 0.270 ;
    END
  END w0_wd_in[453]
  PIN w0_wd_in[454]
    DIRECTION INPUT ;
    USE SIGNAL ;
    SHAPE ABUTMENT ;
    PORT
      LAYER M2 ;
      RECT 57.231 0.000 57.249 0.270 ;
    END
  END w0_wd_in[454]
  PIN w0_wd_in[455]
    DIRECTION INPUT ;
    USE SIGNAL ;
    SHAPE ABUTMENT ;
    PORT
      LAYER M2 ;
      RECT 57.519 0.000 57.537 0.270 ;
    END
  END w0_wd_in[455]
  PIN w0_wd_in[456]
    DIRECTION INPUT ;
    USE SIGNAL ;
    SHAPE ABUTMENT ;
    PORT
      LAYER M2 ;
      RECT 57.807 0.000 57.825 0.270 ;
    END
  END w0_wd_in[456]
  PIN w0_wd_in[457]
    DIRECTION INPUT ;
    USE SIGNAL ;
    SHAPE ABUTMENT ;
    PORT
      LAYER M2 ;
      RECT 58.095 0.000 58.113 0.270 ;
    END
  END w0_wd_in[457]
  PIN w0_wd_in[458]
    DIRECTION INPUT ;
    USE SIGNAL ;
    SHAPE ABUTMENT ;
    PORT
      LAYER M2 ;
      RECT 58.383 0.000 58.401 0.270 ;
    END
  END w0_wd_in[458]
  PIN w0_wd_in[459]
    DIRECTION INPUT ;
    USE SIGNAL ;
    SHAPE ABUTMENT ;
    PORT
      LAYER M2 ;
      RECT 58.671 0.000 58.689 0.270 ;
    END
  END w0_wd_in[459]
  PIN w0_wd_in[460]
    DIRECTION INPUT ;
    USE SIGNAL ;
    SHAPE ABUTMENT ;
    PORT
      LAYER M2 ;
      RECT 58.959 0.000 58.977 0.270 ;
    END
  END w0_wd_in[460]
  PIN w0_wd_in[461]
    DIRECTION INPUT ;
    USE SIGNAL ;
    SHAPE ABUTMENT ;
    PORT
      LAYER M2 ;
      RECT 59.247 0.000 59.265 0.270 ;
    END
  END w0_wd_in[461]
  PIN w0_wd_in[462]
    DIRECTION INPUT ;
    USE SIGNAL ;
    SHAPE ABUTMENT ;
    PORT
      LAYER M2 ;
      RECT 59.535 0.000 59.553 0.270 ;
    END
  END w0_wd_in[462]
  PIN w0_wd_in[463]
    DIRECTION INPUT ;
    USE SIGNAL ;
    SHAPE ABUTMENT ;
    PORT
      LAYER M2 ;
      RECT 59.823 0.000 59.841 0.270 ;
    END
  END w0_wd_in[463]
  PIN w0_wd_in[464]
    DIRECTION INPUT ;
    USE SIGNAL ;
    SHAPE ABUTMENT ;
    PORT
      LAYER M2 ;
      RECT 60.111 0.000 60.129 0.270 ;
    END
  END w0_wd_in[464]
  PIN w0_wd_in[465]
    DIRECTION INPUT ;
    USE SIGNAL ;
    SHAPE ABUTMENT ;
    PORT
      LAYER M2 ;
      RECT 60.399 0.000 60.417 0.270 ;
    END
  END w0_wd_in[465]
  PIN w0_wd_in[466]
    DIRECTION INPUT ;
    USE SIGNAL ;
    SHAPE ABUTMENT ;
    PORT
      LAYER M2 ;
      RECT 60.687 0.000 60.705 0.270 ;
    END
  END w0_wd_in[466]
  PIN w0_wd_in[467]
    DIRECTION INPUT ;
    USE SIGNAL ;
    SHAPE ABUTMENT ;
    PORT
      LAYER M2 ;
      RECT 60.975 0.000 60.993 0.270 ;
    END
  END w0_wd_in[467]
  PIN w0_wd_in[468]
    DIRECTION INPUT ;
    USE SIGNAL ;
    SHAPE ABUTMENT ;
    PORT
      LAYER M2 ;
      RECT 61.263 0.000 61.281 0.270 ;
    END
  END w0_wd_in[468]
  PIN w0_wd_in[469]
    DIRECTION INPUT ;
    USE SIGNAL ;
    SHAPE ABUTMENT ;
    PORT
      LAYER M2 ;
      RECT 61.551 0.000 61.569 0.270 ;
    END
  END w0_wd_in[469]
  PIN w0_wd_in[470]
    DIRECTION INPUT ;
    USE SIGNAL ;
    SHAPE ABUTMENT ;
    PORT
      LAYER M2 ;
      RECT 61.839 0.000 61.857 0.270 ;
    END
  END w0_wd_in[470]
  PIN w0_wd_in[471]
    DIRECTION INPUT ;
    USE SIGNAL ;
    SHAPE ABUTMENT ;
    PORT
      LAYER M2 ;
      RECT 62.127 0.000 62.145 0.270 ;
    END
  END w0_wd_in[471]
  PIN w0_wd_in[472]
    DIRECTION INPUT ;
    USE SIGNAL ;
    SHAPE ABUTMENT ;
    PORT
      LAYER M2 ;
      RECT 62.415 0.000 62.433 0.270 ;
    END
  END w0_wd_in[472]
  PIN w0_wd_in[473]
    DIRECTION INPUT ;
    USE SIGNAL ;
    SHAPE ABUTMENT ;
    PORT
      LAYER M2 ;
      RECT 62.703 0.000 62.721 0.270 ;
    END
  END w0_wd_in[473]
  PIN w0_wd_in[474]
    DIRECTION INPUT ;
    USE SIGNAL ;
    SHAPE ABUTMENT ;
    PORT
      LAYER M2 ;
      RECT 62.991 0.000 63.009 0.270 ;
    END
  END w0_wd_in[474]
  PIN w0_wd_in[475]
    DIRECTION INPUT ;
    USE SIGNAL ;
    SHAPE ABUTMENT ;
    PORT
      LAYER M2 ;
      RECT 63.279 0.000 63.297 0.270 ;
    END
  END w0_wd_in[475]
  PIN w0_wd_in[476]
    DIRECTION INPUT ;
    USE SIGNAL ;
    SHAPE ABUTMENT ;
    PORT
      LAYER M2 ;
      RECT 63.567 0.000 63.585 0.270 ;
    END
  END w0_wd_in[476]
  PIN w0_wd_in[477]
    DIRECTION INPUT ;
    USE SIGNAL ;
    SHAPE ABUTMENT ;
    PORT
      LAYER M2 ;
      RECT 63.855 0.000 63.873 0.270 ;
    END
  END w0_wd_in[477]
  PIN w0_wd_in[478]
    DIRECTION INPUT ;
    USE SIGNAL ;
    SHAPE ABUTMENT ;
    PORT
      LAYER M2 ;
      RECT 64.143 0.000 64.161 0.270 ;
    END
  END w0_wd_in[478]
  PIN w0_wd_in[479]
    DIRECTION INPUT ;
    USE SIGNAL ;
    SHAPE ABUTMENT ;
    PORT
      LAYER M2 ;
      RECT 64.431 0.000 64.449 0.270 ;
    END
  END w0_wd_in[479]
  PIN w0_wd_in[480]
    DIRECTION INPUT ;
    USE SIGNAL ;
    SHAPE ABUTMENT ;
    PORT
      LAYER M2 ;
      RECT 64.719 0.000 64.737 0.270 ;
    END
  END w0_wd_in[480]
  PIN w0_wd_in[481]
    DIRECTION INPUT ;
    USE SIGNAL ;
    SHAPE ABUTMENT ;
    PORT
      LAYER M2 ;
      RECT 65.007 0.000 65.025 0.270 ;
    END
  END w0_wd_in[481]
  PIN w0_wd_in[482]
    DIRECTION INPUT ;
    USE SIGNAL ;
    SHAPE ABUTMENT ;
    PORT
      LAYER M2 ;
      RECT 65.295 0.000 65.313 0.270 ;
    END
  END w0_wd_in[482]
  PIN w0_wd_in[483]
    DIRECTION INPUT ;
    USE SIGNAL ;
    SHAPE ABUTMENT ;
    PORT
      LAYER M2 ;
      RECT 65.583 0.000 65.601 0.270 ;
    END
  END w0_wd_in[483]
  PIN w0_wd_in[484]
    DIRECTION INPUT ;
    USE SIGNAL ;
    SHAPE ABUTMENT ;
    PORT
      LAYER M2 ;
      RECT 65.871 0.000 65.889 0.270 ;
    END
  END w0_wd_in[484]
  PIN w0_wd_in[485]
    DIRECTION INPUT ;
    USE SIGNAL ;
    SHAPE ABUTMENT ;
    PORT
      LAYER M2 ;
      RECT 66.159 0.000 66.177 0.270 ;
    END
  END w0_wd_in[485]
  PIN w0_wd_in[486]
    DIRECTION INPUT ;
    USE SIGNAL ;
    SHAPE ABUTMENT ;
    PORT
      LAYER M2 ;
      RECT 66.447 0.000 66.465 0.270 ;
    END
  END w0_wd_in[486]
  PIN w0_wd_in[487]
    DIRECTION INPUT ;
    USE SIGNAL ;
    SHAPE ABUTMENT ;
    PORT
      LAYER M2 ;
      RECT 66.735 0.000 66.753 0.270 ;
    END
  END w0_wd_in[487]
  PIN w0_wd_in[488]
    DIRECTION INPUT ;
    USE SIGNAL ;
    SHAPE ABUTMENT ;
    PORT
      LAYER M2 ;
      RECT 67.023 0.000 67.041 0.270 ;
    END
  END w0_wd_in[488]
  PIN w0_wd_in[489]
    DIRECTION INPUT ;
    USE SIGNAL ;
    SHAPE ABUTMENT ;
    PORT
      LAYER M2 ;
      RECT 67.311 0.000 67.329 0.270 ;
    END
  END w0_wd_in[489]
  PIN w0_wd_in[490]
    DIRECTION INPUT ;
    USE SIGNAL ;
    SHAPE ABUTMENT ;
    PORT
      LAYER M2 ;
      RECT 67.599 0.000 67.617 0.270 ;
    END
  END w0_wd_in[490]
  PIN w0_wd_in[491]
    DIRECTION INPUT ;
    USE SIGNAL ;
    SHAPE ABUTMENT ;
    PORT
      LAYER M2 ;
      RECT 67.887 0.000 67.905 0.270 ;
    END
  END w0_wd_in[491]
  PIN w0_wd_in[492]
    DIRECTION INPUT ;
    USE SIGNAL ;
    SHAPE ABUTMENT ;
    PORT
      LAYER M2 ;
      RECT 68.175 0.000 68.193 0.270 ;
    END
  END w0_wd_in[492]
  PIN w0_wd_in[493]
    DIRECTION INPUT ;
    USE SIGNAL ;
    SHAPE ABUTMENT ;
    PORT
      LAYER M2 ;
      RECT 68.463 0.000 68.481 0.270 ;
    END
  END w0_wd_in[493]
  PIN w0_wd_in[494]
    DIRECTION INPUT ;
    USE SIGNAL ;
    SHAPE ABUTMENT ;
    PORT
      LAYER M2 ;
      RECT 68.751 0.000 68.769 0.270 ;
    END
  END w0_wd_in[494]
  PIN w0_wd_in[495]
    DIRECTION INPUT ;
    USE SIGNAL ;
    SHAPE ABUTMENT ;
    PORT
      LAYER M2 ;
      RECT 69.039 0.000 69.057 0.270 ;
    END
  END w0_wd_in[495]
  PIN w0_wd_in[496]
    DIRECTION INPUT ;
    USE SIGNAL ;
    SHAPE ABUTMENT ;
    PORT
      LAYER M2 ;
      RECT 69.327 0.000 69.345 0.270 ;
    END
  END w0_wd_in[496]
  PIN w0_wd_in[497]
    DIRECTION INPUT ;
    USE SIGNAL ;
    SHAPE ABUTMENT ;
    PORT
      LAYER M2 ;
      RECT 69.615 0.000 69.633 0.270 ;
    END
  END w0_wd_in[497]
  PIN w0_wd_in[498]
    DIRECTION INPUT ;
    USE SIGNAL ;
    SHAPE ABUTMENT ;
    PORT
      LAYER M2 ;
      RECT 69.903 0.000 69.921 0.270 ;
    END
  END w0_wd_in[498]
  PIN w0_wd_in[499]
    DIRECTION INPUT ;
    USE SIGNAL ;
    SHAPE ABUTMENT ;
    PORT
      LAYER M2 ;
      RECT 70.191 0.000 70.209 0.270 ;
    END
  END w0_wd_in[499]
  PIN w0_wd_in[500]
    DIRECTION INPUT ;
    USE SIGNAL ;
    SHAPE ABUTMENT ;
    PORT
      LAYER M2 ;
      RECT 70.479 0.000 70.497 0.270 ;
    END
  END w0_wd_in[500]
  PIN w0_wd_in[501]
    DIRECTION INPUT ;
    USE SIGNAL ;
    SHAPE ABUTMENT ;
    PORT
      LAYER M2 ;
      RECT 70.767 0.000 70.785 0.270 ;
    END
  END w0_wd_in[501]
  PIN w0_wd_in[502]
    DIRECTION INPUT ;
    USE SIGNAL ;
    SHAPE ABUTMENT ;
    PORT
      LAYER M2 ;
      RECT 71.055 0.000 71.073 0.270 ;
    END
  END w0_wd_in[502]
  PIN w0_wd_in[503]
    DIRECTION INPUT ;
    USE SIGNAL ;
    SHAPE ABUTMENT ;
    PORT
      LAYER M2 ;
      RECT 71.343 0.000 71.361 0.270 ;
    END
  END w0_wd_in[503]
  PIN w0_wd_in[504]
    DIRECTION INPUT ;
    USE SIGNAL ;
    SHAPE ABUTMENT ;
    PORT
      LAYER M2 ;
      RECT 71.631 0.000 71.649 0.270 ;
    END
  END w0_wd_in[504]
  PIN w0_wd_in[505]
    DIRECTION INPUT ;
    USE SIGNAL ;
    SHAPE ABUTMENT ;
    PORT
      LAYER M2 ;
      RECT 71.919 0.000 71.937 0.270 ;
    END
  END w0_wd_in[505]
  PIN w0_wd_in[506]
    DIRECTION INPUT ;
    USE SIGNAL ;
    SHAPE ABUTMENT ;
    PORT
      LAYER M2 ;
      RECT 72.207 0.000 72.225 0.270 ;
    END
  END w0_wd_in[506]
  PIN w0_wd_in[507]
    DIRECTION INPUT ;
    USE SIGNAL ;
    SHAPE ABUTMENT ;
    PORT
      LAYER M2 ;
      RECT 72.495 0.000 72.513 0.270 ;
    END
  END w0_wd_in[507]
  PIN w0_wd_in[508]
    DIRECTION INPUT ;
    USE SIGNAL ;
    SHAPE ABUTMENT ;
    PORT
      LAYER M2 ;
      RECT 72.783 0.000 72.801 0.270 ;
    END
  END w0_wd_in[508]
  PIN w0_wd_in[509]
    DIRECTION INPUT ;
    USE SIGNAL ;
    SHAPE ABUTMENT ;
    PORT
      LAYER M2 ;
      RECT 73.071 0.000 73.089 0.270 ;
    END
  END w0_wd_in[509]
  PIN w0_wd_in[510]
    DIRECTION INPUT ;
    USE SIGNAL ;
    SHAPE ABUTMENT ;
    PORT
      LAYER M2 ;
      RECT 73.359 0.000 73.377 0.270 ;
    END
  END w0_wd_in[510]
  PIN w0_wd_in[511]
    DIRECTION INPUT ;
    USE SIGNAL ;
    SHAPE ABUTMENT ;
    PORT
      LAYER M2 ;
      RECT 73.647 0.000 73.665 0.270 ;
    END
  END w0_wd_in[511]
  PIN r0_rd_out[0]
    DIRECTION OUTPUT ;
    USE SIGNAL ;
    SHAPE ABUTMENT ;
    PORT
      LAYER M2 ;
      RECT 73.935 0.000 73.953 0.270 ;
    END
  END r0_rd_out[0]
  PIN r0_rd_out[1]
    DIRECTION OUTPUT ;
    USE SIGNAL ;
    SHAPE ABUTMENT ;
    PORT
      LAYER M2 ;
      RECT 74.223 0.000 74.241 0.270 ;
    END
  END r0_rd_out[1]
  PIN r0_rd_out[2]
    DIRECTION OUTPUT ;
    USE SIGNAL ;
    SHAPE ABUTMENT ;
    PORT
      LAYER M2 ;
      RECT 74.511 0.000 74.529 0.270 ;
    END
  END r0_rd_out[2]
  PIN r0_rd_out[3]
    DIRECTION OUTPUT ;
    USE SIGNAL ;
    SHAPE ABUTMENT ;
    PORT
      LAYER M2 ;
      RECT 74.799 0.000 74.817 0.270 ;
    END
  END r0_rd_out[3]
  PIN r0_rd_out[4]
    DIRECTION OUTPUT ;
    USE SIGNAL ;
    SHAPE ABUTMENT ;
    PORT
      LAYER M2 ;
      RECT 75.087 0.000 75.105 0.270 ;
    END
  END r0_rd_out[4]
  PIN r0_rd_out[5]
    DIRECTION OUTPUT ;
    USE SIGNAL ;
    SHAPE ABUTMENT ;
    PORT
      LAYER M2 ;
      RECT 75.375 0.000 75.393 0.270 ;
    END
  END r0_rd_out[5]
  PIN r0_rd_out[6]
    DIRECTION OUTPUT ;
    USE SIGNAL ;
    SHAPE ABUTMENT ;
    PORT
      LAYER M2 ;
      RECT 75.663 0.000 75.681 0.270 ;
    END
  END r0_rd_out[6]
  PIN r0_rd_out[7]
    DIRECTION OUTPUT ;
    USE SIGNAL ;
    SHAPE ABUTMENT ;
    PORT
      LAYER M2 ;
      RECT 75.951 0.000 75.969 0.270 ;
    END
  END r0_rd_out[7]
  PIN r0_rd_out[8]
    DIRECTION OUTPUT ;
    USE SIGNAL ;
    SHAPE ABUTMENT ;
    PORT
      LAYER M2 ;
      RECT 76.239 0.000 76.257 0.270 ;
    END
  END r0_rd_out[8]
  PIN r0_rd_out[9]
    DIRECTION OUTPUT ;
    USE SIGNAL ;
    SHAPE ABUTMENT ;
    PORT
      LAYER M2 ;
      RECT 76.527 0.000 76.545 0.270 ;
    END
  END r0_rd_out[9]
  PIN r0_rd_out[10]
    DIRECTION OUTPUT ;
    USE SIGNAL ;
    SHAPE ABUTMENT ;
    PORT
      LAYER M2 ;
      RECT 76.815 0.000 76.833 0.270 ;
    END
  END r0_rd_out[10]
  PIN r0_rd_out[11]
    DIRECTION OUTPUT ;
    USE SIGNAL ;
    SHAPE ABUTMENT ;
    PORT
      LAYER M2 ;
      RECT 77.103 0.000 77.121 0.270 ;
    END
  END r0_rd_out[11]
  PIN r0_rd_out[12]
    DIRECTION OUTPUT ;
    USE SIGNAL ;
    SHAPE ABUTMENT ;
    PORT
      LAYER M2 ;
      RECT 77.391 0.000 77.409 0.270 ;
    END
  END r0_rd_out[12]
  PIN r0_rd_out[13]
    DIRECTION OUTPUT ;
    USE SIGNAL ;
    SHAPE ABUTMENT ;
    PORT
      LAYER M2 ;
      RECT 77.679 0.000 77.697 0.270 ;
    END
  END r0_rd_out[13]
  PIN r0_rd_out[14]
    DIRECTION OUTPUT ;
    USE SIGNAL ;
    SHAPE ABUTMENT ;
    PORT
      LAYER M2 ;
      RECT 77.967 0.000 77.985 0.270 ;
    END
  END r0_rd_out[14]
  PIN r0_rd_out[15]
    DIRECTION OUTPUT ;
    USE SIGNAL ;
    SHAPE ABUTMENT ;
    PORT
      LAYER M2 ;
      RECT 78.255 0.000 78.273 0.270 ;
    END
  END r0_rd_out[15]
  PIN r0_rd_out[16]
    DIRECTION OUTPUT ;
    USE SIGNAL ;
    SHAPE ABUTMENT ;
    PORT
      LAYER M2 ;
      RECT 78.543 0.000 78.561 0.270 ;
    END
  END r0_rd_out[16]
  PIN r0_rd_out[17]
    DIRECTION OUTPUT ;
    USE SIGNAL ;
    SHAPE ABUTMENT ;
    PORT
      LAYER M2 ;
      RECT 78.831 0.000 78.849 0.270 ;
    END
  END r0_rd_out[17]
  PIN r0_rd_out[18]
    DIRECTION OUTPUT ;
    USE SIGNAL ;
    SHAPE ABUTMENT ;
    PORT
      LAYER M2 ;
      RECT 79.119 0.000 79.137 0.270 ;
    END
  END r0_rd_out[18]
  PIN r0_rd_out[19]
    DIRECTION OUTPUT ;
    USE SIGNAL ;
    SHAPE ABUTMENT ;
    PORT
      LAYER M2 ;
      RECT 79.407 0.000 79.425 0.270 ;
    END
  END r0_rd_out[19]
  PIN r0_rd_out[20]
    DIRECTION OUTPUT ;
    USE SIGNAL ;
    SHAPE ABUTMENT ;
    PORT
      LAYER M2 ;
      RECT 79.695 0.000 79.713 0.270 ;
    END
  END r0_rd_out[20]
  PIN r0_rd_out[21]
    DIRECTION OUTPUT ;
    USE SIGNAL ;
    SHAPE ABUTMENT ;
    PORT
      LAYER M2 ;
      RECT 79.983 0.000 80.001 0.270 ;
    END
  END r0_rd_out[21]
  PIN r0_rd_out[22]
    DIRECTION OUTPUT ;
    USE SIGNAL ;
    SHAPE ABUTMENT ;
    PORT
      LAYER M2 ;
      RECT 80.271 0.000 80.289 0.270 ;
    END
  END r0_rd_out[22]
  PIN r0_rd_out[23]
    DIRECTION OUTPUT ;
    USE SIGNAL ;
    SHAPE ABUTMENT ;
    PORT
      LAYER M2 ;
      RECT 80.559 0.000 80.577 0.270 ;
    END
  END r0_rd_out[23]
  PIN r0_rd_out[24]
    DIRECTION OUTPUT ;
    USE SIGNAL ;
    SHAPE ABUTMENT ;
    PORT
      LAYER M2 ;
      RECT 80.847 0.000 80.865 0.270 ;
    END
  END r0_rd_out[24]
  PIN r0_rd_out[25]
    DIRECTION OUTPUT ;
    USE SIGNAL ;
    SHAPE ABUTMENT ;
    PORT
      LAYER M2 ;
      RECT 81.135 0.000 81.153 0.270 ;
    END
  END r0_rd_out[25]
  PIN r0_rd_out[26]
    DIRECTION OUTPUT ;
    USE SIGNAL ;
    SHAPE ABUTMENT ;
    PORT
      LAYER M2 ;
      RECT 81.423 0.000 81.441 0.270 ;
    END
  END r0_rd_out[26]
  PIN r0_rd_out[27]
    DIRECTION OUTPUT ;
    USE SIGNAL ;
    SHAPE ABUTMENT ;
    PORT
      LAYER M2 ;
      RECT 81.711 0.000 81.729 0.270 ;
    END
  END r0_rd_out[27]
  PIN r0_rd_out[28]
    DIRECTION OUTPUT ;
    USE SIGNAL ;
    SHAPE ABUTMENT ;
    PORT
      LAYER M2 ;
      RECT 81.999 0.000 82.017 0.270 ;
    END
  END r0_rd_out[28]
  PIN r0_rd_out[29]
    DIRECTION OUTPUT ;
    USE SIGNAL ;
    SHAPE ABUTMENT ;
    PORT
      LAYER M2 ;
      RECT 82.287 0.000 82.305 0.270 ;
    END
  END r0_rd_out[29]
  PIN r0_rd_out[30]
    DIRECTION OUTPUT ;
    USE SIGNAL ;
    SHAPE ABUTMENT ;
    PORT
      LAYER M2 ;
      RECT 82.575 0.000 82.593 0.270 ;
    END
  END r0_rd_out[30]
  PIN r0_rd_out[31]
    DIRECTION OUTPUT ;
    USE SIGNAL ;
    SHAPE ABUTMENT ;
    PORT
      LAYER M2 ;
      RECT 82.863 0.000 82.881 0.270 ;
    END
  END r0_rd_out[31]
  PIN r0_rd_out[32]
    DIRECTION OUTPUT ;
    USE SIGNAL ;
    SHAPE ABUTMENT ;
    PORT
      LAYER M2 ;
      RECT 83.151 0.000 83.169 0.270 ;
    END
  END r0_rd_out[32]
  PIN r0_rd_out[33]
    DIRECTION OUTPUT ;
    USE SIGNAL ;
    SHAPE ABUTMENT ;
    PORT
      LAYER M2 ;
      RECT 83.439 0.000 83.457 0.270 ;
    END
  END r0_rd_out[33]
  PIN r0_rd_out[34]
    DIRECTION OUTPUT ;
    USE SIGNAL ;
    SHAPE ABUTMENT ;
    PORT
      LAYER M2 ;
      RECT 83.727 0.000 83.745 0.270 ;
    END
  END r0_rd_out[34]
  PIN r0_rd_out[35]
    DIRECTION OUTPUT ;
    USE SIGNAL ;
    SHAPE ABUTMENT ;
    PORT
      LAYER M2 ;
      RECT 84.015 0.000 84.033 0.270 ;
    END
  END r0_rd_out[35]
  PIN r0_rd_out[36]
    DIRECTION OUTPUT ;
    USE SIGNAL ;
    SHAPE ABUTMENT ;
    PORT
      LAYER M2 ;
      RECT 84.303 0.000 84.321 0.270 ;
    END
  END r0_rd_out[36]
  PIN r0_rd_out[37]
    DIRECTION OUTPUT ;
    USE SIGNAL ;
    SHAPE ABUTMENT ;
    PORT
      LAYER M2 ;
      RECT 84.591 0.000 84.609 0.270 ;
    END
  END r0_rd_out[37]
  PIN r0_rd_out[38]
    DIRECTION OUTPUT ;
    USE SIGNAL ;
    SHAPE ABUTMENT ;
    PORT
      LAYER M2 ;
      RECT 84.879 0.000 84.897 0.270 ;
    END
  END r0_rd_out[38]
  PIN r0_rd_out[39]
    DIRECTION OUTPUT ;
    USE SIGNAL ;
    SHAPE ABUTMENT ;
    PORT
      LAYER M2 ;
      RECT 85.167 0.000 85.185 0.270 ;
    END
  END r0_rd_out[39]
  PIN r0_rd_out[40]
    DIRECTION OUTPUT ;
    USE SIGNAL ;
    SHAPE ABUTMENT ;
    PORT
      LAYER M2 ;
      RECT 85.455 0.000 85.473 0.270 ;
    END
  END r0_rd_out[40]
  PIN r0_rd_out[41]
    DIRECTION OUTPUT ;
    USE SIGNAL ;
    SHAPE ABUTMENT ;
    PORT
      LAYER M2 ;
      RECT 85.743 0.000 85.761 0.270 ;
    END
  END r0_rd_out[41]
  PIN r0_rd_out[42]
    DIRECTION OUTPUT ;
    USE SIGNAL ;
    SHAPE ABUTMENT ;
    PORT
      LAYER M2 ;
      RECT 86.031 0.000 86.049 0.270 ;
    END
  END r0_rd_out[42]
  PIN r0_rd_out[43]
    DIRECTION OUTPUT ;
    USE SIGNAL ;
    SHAPE ABUTMENT ;
    PORT
      LAYER M2 ;
      RECT 86.319 0.000 86.337 0.270 ;
    END
  END r0_rd_out[43]
  PIN r0_rd_out[44]
    DIRECTION OUTPUT ;
    USE SIGNAL ;
    SHAPE ABUTMENT ;
    PORT
      LAYER M2 ;
      RECT 86.607 0.000 86.625 0.270 ;
    END
  END r0_rd_out[44]
  PIN r0_rd_out[45]
    DIRECTION OUTPUT ;
    USE SIGNAL ;
    SHAPE ABUTMENT ;
    PORT
      LAYER M2 ;
      RECT 86.895 0.000 86.913 0.270 ;
    END
  END r0_rd_out[45]
  PIN r0_rd_out[46]
    DIRECTION OUTPUT ;
    USE SIGNAL ;
    SHAPE ABUTMENT ;
    PORT
      LAYER M2 ;
      RECT 87.183 0.000 87.201 0.270 ;
    END
  END r0_rd_out[46]
  PIN r0_rd_out[47]
    DIRECTION OUTPUT ;
    USE SIGNAL ;
    SHAPE ABUTMENT ;
    PORT
      LAYER M2 ;
      RECT 87.471 0.000 87.489 0.270 ;
    END
  END r0_rd_out[47]
  PIN r0_rd_out[48]
    DIRECTION OUTPUT ;
    USE SIGNAL ;
    SHAPE ABUTMENT ;
    PORT
      LAYER M2 ;
      RECT 87.759 0.000 87.777 0.270 ;
    END
  END r0_rd_out[48]
  PIN r0_rd_out[49]
    DIRECTION OUTPUT ;
    USE SIGNAL ;
    SHAPE ABUTMENT ;
    PORT
      LAYER M2 ;
      RECT 88.047 0.000 88.065 0.270 ;
    END
  END r0_rd_out[49]
  PIN r0_rd_out[50]
    DIRECTION OUTPUT ;
    USE SIGNAL ;
    SHAPE ABUTMENT ;
    PORT
      LAYER M2 ;
      RECT 88.335 0.000 88.353 0.270 ;
    END
  END r0_rd_out[50]
  PIN r0_rd_out[51]
    DIRECTION OUTPUT ;
    USE SIGNAL ;
    SHAPE ABUTMENT ;
    PORT
      LAYER M2 ;
      RECT 88.623 0.000 88.641 0.270 ;
    END
  END r0_rd_out[51]
  PIN r0_rd_out[52]
    DIRECTION OUTPUT ;
    USE SIGNAL ;
    SHAPE ABUTMENT ;
    PORT
      LAYER M2 ;
      RECT 88.911 0.000 88.929 0.270 ;
    END
  END r0_rd_out[52]
  PIN r0_rd_out[53]
    DIRECTION OUTPUT ;
    USE SIGNAL ;
    SHAPE ABUTMENT ;
    PORT
      LAYER M2 ;
      RECT 89.199 0.000 89.217 0.270 ;
    END
  END r0_rd_out[53]
  PIN r0_rd_out[54]
    DIRECTION OUTPUT ;
    USE SIGNAL ;
    SHAPE ABUTMENT ;
    PORT
      LAYER M2 ;
      RECT 89.487 0.000 89.505 0.270 ;
    END
  END r0_rd_out[54]
  PIN r0_rd_out[55]
    DIRECTION OUTPUT ;
    USE SIGNAL ;
    SHAPE ABUTMENT ;
    PORT
      LAYER M2 ;
      RECT 89.775 0.000 89.793 0.270 ;
    END
  END r0_rd_out[55]
  PIN r0_rd_out[56]
    DIRECTION OUTPUT ;
    USE SIGNAL ;
    SHAPE ABUTMENT ;
    PORT
      LAYER M2 ;
      RECT 90.063 0.000 90.081 0.270 ;
    END
  END r0_rd_out[56]
  PIN r0_rd_out[57]
    DIRECTION OUTPUT ;
    USE SIGNAL ;
    SHAPE ABUTMENT ;
    PORT
      LAYER M2 ;
      RECT 90.351 0.000 90.369 0.270 ;
    END
  END r0_rd_out[57]
  PIN r0_rd_out[58]
    DIRECTION OUTPUT ;
    USE SIGNAL ;
    SHAPE ABUTMENT ;
    PORT
      LAYER M2 ;
      RECT 90.639 0.000 90.657 0.270 ;
    END
  END r0_rd_out[58]
  PIN r0_rd_out[59]
    DIRECTION OUTPUT ;
    USE SIGNAL ;
    SHAPE ABUTMENT ;
    PORT
      LAYER M2 ;
      RECT 90.927 0.000 90.945 0.270 ;
    END
  END r0_rd_out[59]
  PIN r0_rd_out[60]
    DIRECTION OUTPUT ;
    USE SIGNAL ;
    SHAPE ABUTMENT ;
    PORT
      LAYER M2 ;
      RECT 91.215 0.000 91.233 0.270 ;
    END
  END r0_rd_out[60]
  PIN r0_rd_out[61]
    DIRECTION OUTPUT ;
    USE SIGNAL ;
    SHAPE ABUTMENT ;
    PORT
      LAYER M2 ;
      RECT 91.503 0.000 91.521 0.270 ;
    END
  END r0_rd_out[61]
  PIN r0_rd_out[62]
    DIRECTION OUTPUT ;
    USE SIGNAL ;
    SHAPE ABUTMENT ;
    PORT
      LAYER M2 ;
      RECT 91.791 0.000 91.809 0.270 ;
    END
  END r0_rd_out[62]
  PIN r0_rd_out[63]
    DIRECTION OUTPUT ;
    USE SIGNAL ;
    SHAPE ABUTMENT ;
    PORT
      LAYER M2 ;
      RECT 92.079 0.000 92.097 0.270 ;
    END
  END r0_rd_out[63]
  PIN r0_rd_out[64]
    DIRECTION OUTPUT ;
    USE SIGNAL ;
    SHAPE ABUTMENT ;
    PORT
      LAYER M2 ;
      RECT 92.367 0.000 92.385 0.270 ;
    END
  END r0_rd_out[64]
  PIN r0_rd_out[65]
    DIRECTION OUTPUT ;
    USE SIGNAL ;
    SHAPE ABUTMENT ;
    PORT
      LAYER M2 ;
      RECT 92.655 0.000 92.673 0.270 ;
    END
  END r0_rd_out[65]
  PIN r0_rd_out[66]
    DIRECTION OUTPUT ;
    USE SIGNAL ;
    SHAPE ABUTMENT ;
    PORT
      LAYER M2 ;
      RECT 92.943 0.000 92.961 0.270 ;
    END
  END r0_rd_out[66]
  PIN r0_rd_out[67]
    DIRECTION OUTPUT ;
    USE SIGNAL ;
    SHAPE ABUTMENT ;
    PORT
      LAYER M2 ;
      RECT 93.231 0.000 93.249 0.270 ;
    END
  END r0_rd_out[67]
  PIN r0_rd_out[68]
    DIRECTION OUTPUT ;
    USE SIGNAL ;
    SHAPE ABUTMENT ;
    PORT
      LAYER M2 ;
      RECT 93.519 0.000 93.537 0.270 ;
    END
  END r0_rd_out[68]
  PIN r0_rd_out[69]
    DIRECTION OUTPUT ;
    USE SIGNAL ;
    SHAPE ABUTMENT ;
    PORT
      LAYER M2 ;
      RECT 93.807 0.000 93.825 0.270 ;
    END
  END r0_rd_out[69]
  PIN r0_rd_out[70]
    DIRECTION OUTPUT ;
    USE SIGNAL ;
    SHAPE ABUTMENT ;
    PORT
      LAYER M2 ;
      RECT 94.095 0.000 94.113 0.270 ;
    END
  END r0_rd_out[70]
  PIN r0_rd_out[71]
    DIRECTION OUTPUT ;
    USE SIGNAL ;
    SHAPE ABUTMENT ;
    PORT
      LAYER M2 ;
      RECT 94.383 0.000 94.401 0.270 ;
    END
  END r0_rd_out[71]
  PIN r0_rd_out[72]
    DIRECTION OUTPUT ;
    USE SIGNAL ;
    SHAPE ABUTMENT ;
    PORT
      LAYER M2 ;
      RECT 94.671 0.000 94.689 0.270 ;
    END
  END r0_rd_out[72]
  PIN r0_rd_out[73]
    DIRECTION OUTPUT ;
    USE SIGNAL ;
    SHAPE ABUTMENT ;
    PORT
      LAYER M2 ;
      RECT 94.959 0.000 94.977 0.270 ;
    END
  END r0_rd_out[73]
  PIN r0_rd_out[74]
    DIRECTION OUTPUT ;
    USE SIGNAL ;
    SHAPE ABUTMENT ;
    PORT
      LAYER M2 ;
      RECT 95.247 0.000 95.265 0.270 ;
    END
  END r0_rd_out[74]
  PIN r0_rd_out[75]
    DIRECTION OUTPUT ;
    USE SIGNAL ;
    SHAPE ABUTMENT ;
    PORT
      LAYER M2 ;
      RECT 95.535 0.000 95.553 0.270 ;
    END
  END r0_rd_out[75]
  PIN r0_rd_out[76]
    DIRECTION OUTPUT ;
    USE SIGNAL ;
    SHAPE ABUTMENT ;
    PORT
      LAYER M2 ;
      RECT 95.823 0.000 95.841 0.270 ;
    END
  END r0_rd_out[76]
  PIN r0_rd_out[77]
    DIRECTION OUTPUT ;
    USE SIGNAL ;
    SHAPE ABUTMENT ;
    PORT
      LAYER M2 ;
      RECT 96.111 0.000 96.129 0.270 ;
    END
  END r0_rd_out[77]
  PIN r0_rd_out[78]
    DIRECTION OUTPUT ;
    USE SIGNAL ;
    SHAPE ABUTMENT ;
    PORT
      LAYER M2 ;
      RECT 96.399 0.000 96.417 0.270 ;
    END
  END r0_rd_out[78]
  PIN r0_rd_out[79]
    DIRECTION OUTPUT ;
    USE SIGNAL ;
    SHAPE ABUTMENT ;
    PORT
      LAYER M2 ;
      RECT 96.687 0.000 96.705 0.270 ;
    END
  END r0_rd_out[79]
  PIN r0_rd_out[80]
    DIRECTION OUTPUT ;
    USE SIGNAL ;
    SHAPE ABUTMENT ;
    PORT
      LAYER M2 ;
      RECT 96.975 0.000 96.993 0.270 ;
    END
  END r0_rd_out[80]
  PIN r0_rd_out[81]
    DIRECTION OUTPUT ;
    USE SIGNAL ;
    SHAPE ABUTMENT ;
    PORT
      LAYER M2 ;
      RECT 97.263 0.000 97.281 0.270 ;
    END
  END r0_rd_out[81]
  PIN r0_rd_out[82]
    DIRECTION OUTPUT ;
    USE SIGNAL ;
    SHAPE ABUTMENT ;
    PORT
      LAYER M2 ;
      RECT 97.551 0.000 97.569 0.270 ;
    END
  END r0_rd_out[82]
  PIN r0_rd_out[83]
    DIRECTION OUTPUT ;
    USE SIGNAL ;
    SHAPE ABUTMENT ;
    PORT
      LAYER M2 ;
      RECT 97.839 0.000 97.857 0.270 ;
    END
  END r0_rd_out[83]
  PIN r0_rd_out[84]
    DIRECTION OUTPUT ;
    USE SIGNAL ;
    SHAPE ABUTMENT ;
    PORT
      LAYER M2 ;
      RECT 98.127 0.000 98.145 0.270 ;
    END
  END r0_rd_out[84]
  PIN r0_rd_out[85]
    DIRECTION OUTPUT ;
    USE SIGNAL ;
    SHAPE ABUTMENT ;
    PORT
      LAYER M2 ;
      RECT 98.415 0.000 98.433 0.270 ;
    END
  END r0_rd_out[85]
  PIN r0_rd_out[86]
    DIRECTION OUTPUT ;
    USE SIGNAL ;
    SHAPE ABUTMENT ;
    PORT
      LAYER M2 ;
      RECT 98.703 0.000 98.721 0.270 ;
    END
  END r0_rd_out[86]
  PIN r0_rd_out[87]
    DIRECTION OUTPUT ;
    USE SIGNAL ;
    SHAPE ABUTMENT ;
    PORT
      LAYER M2 ;
      RECT 98.991 0.000 99.009 0.270 ;
    END
  END r0_rd_out[87]
  PIN r0_rd_out[88]
    DIRECTION OUTPUT ;
    USE SIGNAL ;
    SHAPE ABUTMENT ;
    PORT
      LAYER M2 ;
      RECT 99.279 0.000 99.297 0.270 ;
    END
  END r0_rd_out[88]
  PIN r0_rd_out[89]
    DIRECTION OUTPUT ;
    USE SIGNAL ;
    SHAPE ABUTMENT ;
    PORT
      LAYER M2 ;
      RECT 99.567 0.000 99.585 0.270 ;
    END
  END r0_rd_out[89]
  PIN r0_rd_out[90]
    DIRECTION OUTPUT ;
    USE SIGNAL ;
    SHAPE ABUTMENT ;
    PORT
      LAYER M2 ;
      RECT 99.855 0.000 99.873 0.270 ;
    END
  END r0_rd_out[90]
  PIN r0_rd_out[91]
    DIRECTION OUTPUT ;
    USE SIGNAL ;
    SHAPE ABUTMENT ;
    PORT
      LAYER M2 ;
      RECT 100.143 0.000 100.161 0.270 ;
    END
  END r0_rd_out[91]
  PIN r0_rd_out[92]
    DIRECTION OUTPUT ;
    USE SIGNAL ;
    SHAPE ABUTMENT ;
    PORT
      LAYER M2 ;
      RECT 100.431 0.000 100.449 0.270 ;
    END
  END r0_rd_out[92]
  PIN r0_rd_out[93]
    DIRECTION OUTPUT ;
    USE SIGNAL ;
    SHAPE ABUTMENT ;
    PORT
      LAYER M2 ;
      RECT 100.719 0.000 100.737 0.270 ;
    END
  END r0_rd_out[93]
  PIN r0_rd_out[94]
    DIRECTION OUTPUT ;
    USE SIGNAL ;
    SHAPE ABUTMENT ;
    PORT
      LAYER M2 ;
      RECT 101.007 0.000 101.025 0.270 ;
    END
  END r0_rd_out[94]
  PIN r0_rd_out[95]
    DIRECTION OUTPUT ;
    USE SIGNAL ;
    SHAPE ABUTMENT ;
    PORT
      LAYER M2 ;
      RECT 101.295 0.000 101.313 0.270 ;
    END
  END r0_rd_out[95]
  PIN r0_rd_out[96]
    DIRECTION OUTPUT ;
    USE SIGNAL ;
    SHAPE ABUTMENT ;
    PORT
      LAYER M2 ;
      RECT 101.583 0.000 101.601 0.270 ;
    END
  END r0_rd_out[96]
  PIN r0_rd_out[97]
    DIRECTION OUTPUT ;
    USE SIGNAL ;
    SHAPE ABUTMENT ;
    PORT
      LAYER M2 ;
      RECT 101.871 0.000 101.889 0.270 ;
    END
  END r0_rd_out[97]
  PIN r0_rd_out[98]
    DIRECTION OUTPUT ;
    USE SIGNAL ;
    SHAPE ABUTMENT ;
    PORT
      LAYER M2 ;
      RECT 102.159 0.000 102.177 0.270 ;
    END
  END r0_rd_out[98]
  PIN r0_rd_out[99]
    DIRECTION OUTPUT ;
    USE SIGNAL ;
    SHAPE ABUTMENT ;
    PORT
      LAYER M2 ;
      RECT 102.447 0.000 102.465 0.270 ;
    END
  END r0_rd_out[99]
  PIN r0_rd_out[100]
    DIRECTION OUTPUT ;
    USE SIGNAL ;
    SHAPE ABUTMENT ;
    PORT
      LAYER M2 ;
      RECT 102.735 0.000 102.753 0.270 ;
    END
  END r0_rd_out[100]
  PIN r0_rd_out[101]
    DIRECTION OUTPUT ;
    USE SIGNAL ;
    SHAPE ABUTMENT ;
    PORT
      LAYER M2 ;
      RECT 103.023 0.000 103.041 0.270 ;
    END
  END r0_rd_out[101]
  PIN r0_rd_out[102]
    DIRECTION OUTPUT ;
    USE SIGNAL ;
    SHAPE ABUTMENT ;
    PORT
      LAYER M2 ;
      RECT 103.311 0.000 103.329 0.270 ;
    END
  END r0_rd_out[102]
  PIN r0_rd_out[103]
    DIRECTION OUTPUT ;
    USE SIGNAL ;
    SHAPE ABUTMENT ;
    PORT
      LAYER M2 ;
      RECT 103.599 0.000 103.617 0.270 ;
    END
  END r0_rd_out[103]
  PIN r0_rd_out[104]
    DIRECTION OUTPUT ;
    USE SIGNAL ;
    SHAPE ABUTMENT ;
    PORT
      LAYER M2 ;
      RECT 103.887 0.000 103.905 0.270 ;
    END
  END r0_rd_out[104]
  PIN r0_rd_out[105]
    DIRECTION OUTPUT ;
    USE SIGNAL ;
    SHAPE ABUTMENT ;
    PORT
      LAYER M2 ;
      RECT 104.175 0.000 104.193 0.270 ;
    END
  END r0_rd_out[105]
  PIN r0_rd_out[106]
    DIRECTION OUTPUT ;
    USE SIGNAL ;
    SHAPE ABUTMENT ;
    PORT
      LAYER M2 ;
      RECT 104.463 0.000 104.481 0.270 ;
    END
  END r0_rd_out[106]
  PIN r0_rd_out[107]
    DIRECTION OUTPUT ;
    USE SIGNAL ;
    SHAPE ABUTMENT ;
    PORT
      LAYER M2 ;
      RECT 104.751 0.000 104.769 0.270 ;
    END
  END r0_rd_out[107]
  PIN r0_rd_out[108]
    DIRECTION OUTPUT ;
    USE SIGNAL ;
    SHAPE ABUTMENT ;
    PORT
      LAYER M2 ;
      RECT 105.039 0.000 105.057 0.270 ;
    END
  END r0_rd_out[108]
  PIN r0_rd_out[109]
    DIRECTION OUTPUT ;
    USE SIGNAL ;
    SHAPE ABUTMENT ;
    PORT
      LAYER M2 ;
      RECT 105.327 0.000 105.345 0.270 ;
    END
  END r0_rd_out[109]
  PIN r0_rd_out[110]
    DIRECTION OUTPUT ;
    USE SIGNAL ;
    SHAPE ABUTMENT ;
    PORT
      LAYER M2 ;
      RECT 105.615 0.000 105.633 0.270 ;
    END
  END r0_rd_out[110]
  PIN r0_rd_out[111]
    DIRECTION OUTPUT ;
    USE SIGNAL ;
    SHAPE ABUTMENT ;
    PORT
      LAYER M2 ;
      RECT 105.903 0.000 105.921 0.270 ;
    END
  END r0_rd_out[111]
  PIN r0_rd_out[112]
    DIRECTION OUTPUT ;
    USE SIGNAL ;
    SHAPE ABUTMENT ;
    PORT
      LAYER M2 ;
      RECT 106.191 0.000 106.209 0.270 ;
    END
  END r0_rd_out[112]
  PIN r0_rd_out[113]
    DIRECTION OUTPUT ;
    USE SIGNAL ;
    SHAPE ABUTMENT ;
    PORT
      LAYER M2 ;
      RECT 106.479 0.000 106.497 0.270 ;
    END
  END r0_rd_out[113]
  PIN r0_rd_out[114]
    DIRECTION OUTPUT ;
    USE SIGNAL ;
    SHAPE ABUTMENT ;
    PORT
      LAYER M2 ;
      RECT 106.767 0.000 106.785 0.270 ;
    END
  END r0_rd_out[114]
  PIN r0_rd_out[115]
    DIRECTION OUTPUT ;
    USE SIGNAL ;
    SHAPE ABUTMENT ;
    PORT
      LAYER M2 ;
      RECT 107.055 0.000 107.073 0.270 ;
    END
  END r0_rd_out[115]
  PIN r0_rd_out[116]
    DIRECTION OUTPUT ;
    USE SIGNAL ;
    SHAPE ABUTMENT ;
    PORT
      LAYER M2 ;
      RECT 107.343 0.000 107.361 0.270 ;
    END
  END r0_rd_out[116]
  PIN r0_rd_out[117]
    DIRECTION OUTPUT ;
    USE SIGNAL ;
    SHAPE ABUTMENT ;
    PORT
      LAYER M2 ;
      RECT 107.631 0.000 107.649 0.270 ;
    END
  END r0_rd_out[117]
  PIN r0_rd_out[118]
    DIRECTION OUTPUT ;
    USE SIGNAL ;
    SHAPE ABUTMENT ;
    PORT
      LAYER M2 ;
      RECT 107.919 0.000 107.937 0.270 ;
    END
  END r0_rd_out[118]
  PIN r0_rd_out[119]
    DIRECTION OUTPUT ;
    USE SIGNAL ;
    SHAPE ABUTMENT ;
    PORT
      LAYER M2 ;
      RECT 108.207 0.000 108.225 0.270 ;
    END
  END r0_rd_out[119]
  PIN r0_rd_out[120]
    DIRECTION OUTPUT ;
    USE SIGNAL ;
    SHAPE ABUTMENT ;
    PORT
      LAYER M2 ;
      RECT 108.495 0.000 108.513 0.270 ;
    END
  END r0_rd_out[120]
  PIN r0_rd_out[121]
    DIRECTION OUTPUT ;
    USE SIGNAL ;
    SHAPE ABUTMENT ;
    PORT
      LAYER M2 ;
      RECT 108.783 0.000 108.801 0.270 ;
    END
  END r0_rd_out[121]
  PIN r0_rd_out[122]
    DIRECTION OUTPUT ;
    USE SIGNAL ;
    SHAPE ABUTMENT ;
    PORT
      LAYER M2 ;
      RECT 109.071 0.000 109.089 0.270 ;
    END
  END r0_rd_out[122]
  PIN r0_rd_out[123]
    DIRECTION OUTPUT ;
    USE SIGNAL ;
    SHAPE ABUTMENT ;
    PORT
      LAYER M2 ;
      RECT 109.359 0.000 109.377 0.270 ;
    END
  END r0_rd_out[123]
  PIN r0_rd_out[124]
    DIRECTION OUTPUT ;
    USE SIGNAL ;
    SHAPE ABUTMENT ;
    PORT
      LAYER M2 ;
      RECT 109.647 0.000 109.665 0.270 ;
    END
  END r0_rd_out[124]
  PIN r0_rd_out[125]
    DIRECTION OUTPUT ;
    USE SIGNAL ;
    SHAPE ABUTMENT ;
    PORT
      LAYER M2 ;
      RECT 109.935 0.000 109.953 0.270 ;
    END
  END r0_rd_out[125]
  PIN r0_rd_out[126]
    DIRECTION OUTPUT ;
    USE SIGNAL ;
    SHAPE ABUTMENT ;
    PORT
      LAYER M2 ;
      RECT 110.223 0.000 110.241 0.270 ;
    END
  END r0_rd_out[126]
  PIN r0_rd_out[127]
    DIRECTION OUTPUT ;
    USE SIGNAL ;
    SHAPE ABUTMENT ;
    PORT
      LAYER M2 ;
      RECT 110.511 0.000 110.529 0.270 ;
    END
  END r0_rd_out[127]
  PIN r0_rd_out[128]
    DIRECTION OUTPUT ;
    USE SIGNAL ;
    SHAPE ABUTMENT ;
    PORT
      LAYER M2 ;
      RECT 110.799 0.000 110.817 0.270 ;
    END
  END r0_rd_out[128]
  PIN r0_rd_out[129]
    DIRECTION OUTPUT ;
    USE SIGNAL ;
    SHAPE ABUTMENT ;
    PORT
      LAYER M2 ;
      RECT 111.087 0.000 111.105 0.270 ;
    END
  END r0_rd_out[129]
  PIN r0_rd_out[130]
    DIRECTION OUTPUT ;
    USE SIGNAL ;
    SHAPE ABUTMENT ;
    PORT
      LAYER M2 ;
      RECT 111.375 0.000 111.393 0.270 ;
    END
  END r0_rd_out[130]
  PIN r0_rd_out[131]
    DIRECTION OUTPUT ;
    USE SIGNAL ;
    SHAPE ABUTMENT ;
    PORT
      LAYER M2 ;
      RECT 111.663 0.000 111.681 0.270 ;
    END
  END r0_rd_out[131]
  PIN r0_rd_out[132]
    DIRECTION OUTPUT ;
    USE SIGNAL ;
    SHAPE ABUTMENT ;
    PORT
      LAYER M2 ;
      RECT 111.951 0.000 111.969 0.270 ;
    END
  END r0_rd_out[132]
  PIN r0_rd_out[133]
    DIRECTION OUTPUT ;
    USE SIGNAL ;
    SHAPE ABUTMENT ;
    PORT
      LAYER M2 ;
      RECT 112.239 0.000 112.257 0.270 ;
    END
  END r0_rd_out[133]
  PIN r0_rd_out[134]
    DIRECTION OUTPUT ;
    USE SIGNAL ;
    SHAPE ABUTMENT ;
    PORT
      LAYER M2 ;
      RECT 112.527 0.000 112.545 0.270 ;
    END
  END r0_rd_out[134]
  PIN r0_rd_out[135]
    DIRECTION OUTPUT ;
    USE SIGNAL ;
    SHAPE ABUTMENT ;
    PORT
      LAYER M2 ;
      RECT 112.815 0.000 112.833 0.270 ;
    END
  END r0_rd_out[135]
  PIN r0_rd_out[136]
    DIRECTION OUTPUT ;
    USE SIGNAL ;
    SHAPE ABUTMENT ;
    PORT
      LAYER M2 ;
      RECT 113.103 0.000 113.121 0.270 ;
    END
  END r0_rd_out[136]
  PIN r0_rd_out[137]
    DIRECTION OUTPUT ;
    USE SIGNAL ;
    SHAPE ABUTMENT ;
    PORT
      LAYER M2 ;
      RECT 113.391 0.000 113.409 0.270 ;
    END
  END r0_rd_out[137]
  PIN r0_rd_out[138]
    DIRECTION OUTPUT ;
    USE SIGNAL ;
    SHAPE ABUTMENT ;
    PORT
      LAYER M2 ;
      RECT 113.679 0.000 113.697 0.270 ;
    END
  END r0_rd_out[138]
  PIN r0_rd_out[139]
    DIRECTION OUTPUT ;
    USE SIGNAL ;
    SHAPE ABUTMENT ;
    PORT
      LAYER M2 ;
      RECT 113.967 0.000 113.985 0.270 ;
    END
  END r0_rd_out[139]
  PIN r0_rd_out[140]
    DIRECTION OUTPUT ;
    USE SIGNAL ;
    SHAPE ABUTMENT ;
    PORT
      LAYER M2 ;
      RECT 114.255 0.000 114.273 0.270 ;
    END
  END r0_rd_out[140]
  PIN r0_rd_out[141]
    DIRECTION OUTPUT ;
    USE SIGNAL ;
    SHAPE ABUTMENT ;
    PORT
      LAYER M2 ;
      RECT 114.543 0.000 114.561 0.270 ;
    END
  END r0_rd_out[141]
  PIN r0_rd_out[142]
    DIRECTION OUTPUT ;
    USE SIGNAL ;
    SHAPE ABUTMENT ;
    PORT
      LAYER M2 ;
      RECT 114.831 0.000 114.849 0.270 ;
    END
  END r0_rd_out[142]
  PIN r0_rd_out[143]
    DIRECTION OUTPUT ;
    USE SIGNAL ;
    SHAPE ABUTMENT ;
    PORT
      LAYER M2 ;
      RECT 115.119 0.000 115.137 0.270 ;
    END
  END r0_rd_out[143]
  PIN r0_rd_out[144]
    DIRECTION OUTPUT ;
    USE SIGNAL ;
    SHAPE ABUTMENT ;
    PORT
      LAYER M2 ;
      RECT 115.407 0.000 115.425 0.270 ;
    END
  END r0_rd_out[144]
  PIN r0_rd_out[145]
    DIRECTION OUTPUT ;
    USE SIGNAL ;
    SHAPE ABUTMENT ;
    PORT
      LAYER M2 ;
      RECT 115.695 0.000 115.713 0.270 ;
    END
  END r0_rd_out[145]
  PIN r0_rd_out[146]
    DIRECTION OUTPUT ;
    USE SIGNAL ;
    SHAPE ABUTMENT ;
    PORT
      LAYER M2 ;
      RECT 115.983 0.000 116.001 0.270 ;
    END
  END r0_rd_out[146]
  PIN r0_rd_out[147]
    DIRECTION OUTPUT ;
    USE SIGNAL ;
    SHAPE ABUTMENT ;
    PORT
      LAYER M2 ;
      RECT 116.271 0.000 116.289 0.270 ;
    END
  END r0_rd_out[147]
  PIN r0_rd_out[148]
    DIRECTION OUTPUT ;
    USE SIGNAL ;
    SHAPE ABUTMENT ;
    PORT
      LAYER M2 ;
      RECT 116.559 0.000 116.577 0.270 ;
    END
  END r0_rd_out[148]
  PIN r0_rd_out[149]
    DIRECTION OUTPUT ;
    USE SIGNAL ;
    SHAPE ABUTMENT ;
    PORT
      LAYER M2 ;
      RECT 116.847 0.000 116.865 0.270 ;
    END
  END r0_rd_out[149]
  PIN r0_rd_out[150]
    DIRECTION OUTPUT ;
    USE SIGNAL ;
    SHAPE ABUTMENT ;
    PORT
      LAYER M2 ;
      RECT 117.135 0.000 117.153 0.270 ;
    END
  END r0_rd_out[150]
  PIN r0_rd_out[151]
    DIRECTION OUTPUT ;
    USE SIGNAL ;
    SHAPE ABUTMENT ;
    PORT
      LAYER M2 ;
      RECT 117.423 0.000 117.441 0.270 ;
    END
  END r0_rd_out[151]
  PIN r0_rd_out[152]
    DIRECTION OUTPUT ;
    USE SIGNAL ;
    SHAPE ABUTMENT ;
    PORT
      LAYER M2 ;
      RECT 117.711 0.000 117.729 0.270 ;
    END
  END r0_rd_out[152]
  PIN r0_rd_out[153]
    DIRECTION OUTPUT ;
    USE SIGNAL ;
    SHAPE ABUTMENT ;
    PORT
      LAYER M2 ;
      RECT 117.999 0.000 118.017 0.270 ;
    END
  END r0_rd_out[153]
  PIN r0_rd_out[154]
    DIRECTION OUTPUT ;
    USE SIGNAL ;
    SHAPE ABUTMENT ;
    PORT
      LAYER M2 ;
      RECT 118.287 0.000 118.305 0.270 ;
    END
  END r0_rd_out[154]
  PIN r0_rd_out[155]
    DIRECTION OUTPUT ;
    USE SIGNAL ;
    SHAPE ABUTMENT ;
    PORT
      LAYER M2 ;
      RECT 118.575 0.000 118.593 0.270 ;
    END
  END r0_rd_out[155]
  PIN r0_rd_out[156]
    DIRECTION OUTPUT ;
    USE SIGNAL ;
    SHAPE ABUTMENT ;
    PORT
      LAYER M2 ;
      RECT 118.863 0.000 118.881 0.270 ;
    END
  END r0_rd_out[156]
  PIN r0_rd_out[157]
    DIRECTION OUTPUT ;
    USE SIGNAL ;
    SHAPE ABUTMENT ;
    PORT
      LAYER M2 ;
      RECT 119.151 0.000 119.169 0.270 ;
    END
  END r0_rd_out[157]
  PIN r0_rd_out[158]
    DIRECTION OUTPUT ;
    USE SIGNAL ;
    SHAPE ABUTMENT ;
    PORT
      LAYER M2 ;
      RECT 119.439 0.000 119.457 0.270 ;
    END
  END r0_rd_out[158]
  PIN r0_rd_out[159]
    DIRECTION OUTPUT ;
    USE SIGNAL ;
    SHAPE ABUTMENT ;
    PORT
      LAYER M2 ;
      RECT 119.727 0.000 119.745 0.270 ;
    END
  END r0_rd_out[159]
  PIN r0_rd_out[160]
    DIRECTION OUTPUT ;
    USE SIGNAL ;
    SHAPE ABUTMENT ;
    PORT
      LAYER M2 ;
      RECT 120.015 0.000 120.033 0.270 ;
    END
  END r0_rd_out[160]
  PIN r0_rd_out[161]
    DIRECTION OUTPUT ;
    USE SIGNAL ;
    SHAPE ABUTMENT ;
    PORT
      LAYER M2 ;
      RECT 120.303 0.000 120.321 0.270 ;
    END
  END r0_rd_out[161]
  PIN r0_rd_out[162]
    DIRECTION OUTPUT ;
    USE SIGNAL ;
    SHAPE ABUTMENT ;
    PORT
      LAYER M2 ;
      RECT 120.591 0.000 120.609 0.270 ;
    END
  END r0_rd_out[162]
  PIN r0_rd_out[163]
    DIRECTION OUTPUT ;
    USE SIGNAL ;
    SHAPE ABUTMENT ;
    PORT
      LAYER M2 ;
      RECT 120.879 0.000 120.897 0.270 ;
    END
  END r0_rd_out[163]
  PIN r0_rd_out[164]
    DIRECTION OUTPUT ;
    USE SIGNAL ;
    SHAPE ABUTMENT ;
    PORT
      LAYER M2 ;
      RECT 121.167 0.000 121.185 0.270 ;
    END
  END r0_rd_out[164]
  PIN r0_rd_out[165]
    DIRECTION OUTPUT ;
    USE SIGNAL ;
    SHAPE ABUTMENT ;
    PORT
      LAYER M2 ;
      RECT 121.455 0.000 121.473 0.270 ;
    END
  END r0_rd_out[165]
  PIN r0_rd_out[166]
    DIRECTION OUTPUT ;
    USE SIGNAL ;
    SHAPE ABUTMENT ;
    PORT
      LAYER M2 ;
      RECT 121.743 0.000 121.761 0.270 ;
    END
  END r0_rd_out[166]
  PIN r0_rd_out[167]
    DIRECTION OUTPUT ;
    USE SIGNAL ;
    SHAPE ABUTMENT ;
    PORT
      LAYER M2 ;
      RECT 122.031 0.000 122.049 0.270 ;
    END
  END r0_rd_out[167]
  PIN r0_rd_out[168]
    DIRECTION OUTPUT ;
    USE SIGNAL ;
    SHAPE ABUTMENT ;
    PORT
      LAYER M2 ;
      RECT 122.319 0.000 122.337 0.270 ;
    END
  END r0_rd_out[168]
  PIN r0_rd_out[169]
    DIRECTION OUTPUT ;
    USE SIGNAL ;
    SHAPE ABUTMENT ;
    PORT
      LAYER M2 ;
      RECT 122.607 0.000 122.625 0.270 ;
    END
  END r0_rd_out[169]
  PIN r0_rd_out[170]
    DIRECTION OUTPUT ;
    USE SIGNAL ;
    SHAPE ABUTMENT ;
    PORT
      LAYER M2 ;
      RECT 122.895 0.000 122.913 0.270 ;
    END
  END r0_rd_out[170]
  PIN r0_rd_out[171]
    DIRECTION OUTPUT ;
    USE SIGNAL ;
    SHAPE ABUTMENT ;
    PORT
      LAYER M2 ;
      RECT 123.183 0.000 123.201 0.270 ;
    END
  END r0_rd_out[171]
  PIN r0_rd_out[172]
    DIRECTION OUTPUT ;
    USE SIGNAL ;
    SHAPE ABUTMENT ;
    PORT
      LAYER M2 ;
      RECT 123.471 0.000 123.489 0.270 ;
    END
  END r0_rd_out[172]
  PIN r0_rd_out[173]
    DIRECTION OUTPUT ;
    USE SIGNAL ;
    SHAPE ABUTMENT ;
    PORT
      LAYER M2 ;
      RECT 123.759 0.000 123.777 0.270 ;
    END
  END r0_rd_out[173]
  PIN r0_rd_out[174]
    DIRECTION OUTPUT ;
    USE SIGNAL ;
    SHAPE ABUTMENT ;
    PORT
      LAYER M2 ;
      RECT 124.047 0.000 124.065 0.270 ;
    END
  END r0_rd_out[174]
  PIN r0_rd_out[175]
    DIRECTION OUTPUT ;
    USE SIGNAL ;
    SHAPE ABUTMENT ;
    PORT
      LAYER M2 ;
      RECT 124.335 0.000 124.353 0.270 ;
    END
  END r0_rd_out[175]
  PIN r0_rd_out[176]
    DIRECTION OUTPUT ;
    USE SIGNAL ;
    SHAPE ABUTMENT ;
    PORT
      LAYER M2 ;
      RECT 124.623 0.000 124.641 0.270 ;
    END
  END r0_rd_out[176]
  PIN r0_rd_out[177]
    DIRECTION OUTPUT ;
    USE SIGNAL ;
    SHAPE ABUTMENT ;
    PORT
      LAYER M2 ;
      RECT 124.911 0.000 124.929 0.270 ;
    END
  END r0_rd_out[177]
  PIN r0_rd_out[178]
    DIRECTION OUTPUT ;
    USE SIGNAL ;
    SHAPE ABUTMENT ;
    PORT
      LAYER M2 ;
      RECT 125.199 0.000 125.217 0.270 ;
    END
  END r0_rd_out[178]
  PIN r0_rd_out[179]
    DIRECTION OUTPUT ;
    USE SIGNAL ;
    SHAPE ABUTMENT ;
    PORT
      LAYER M2 ;
      RECT 125.487 0.000 125.505 0.270 ;
    END
  END r0_rd_out[179]
  PIN r0_rd_out[180]
    DIRECTION OUTPUT ;
    USE SIGNAL ;
    SHAPE ABUTMENT ;
    PORT
      LAYER M2 ;
      RECT 125.775 0.000 125.793 0.270 ;
    END
  END r0_rd_out[180]
  PIN r0_rd_out[181]
    DIRECTION OUTPUT ;
    USE SIGNAL ;
    SHAPE ABUTMENT ;
    PORT
      LAYER M2 ;
      RECT 126.063 0.000 126.081 0.270 ;
    END
  END r0_rd_out[181]
  PIN r0_rd_out[182]
    DIRECTION OUTPUT ;
    USE SIGNAL ;
    SHAPE ABUTMENT ;
    PORT
      LAYER M2 ;
      RECT 126.351 0.000 126.369 0.270 ;
    END
  END r0_rd_out[182]
  PIN r0_rd_out[183]
    DIRECTION OUTPUT ;
    USE SIGNAL ;
    SHAPE ABUTMENT ;
    PORT
      LAYER M2 ;
      RECT 126.639 0.000 126.657 0.270 ;
    END
  END r0_rd_out[183]
  PIN r0_rd_out[184]
    DIRECTION OUTPUT ;
    USE SIGNAL ;
    SHAPE ABUTMENT ;
    PORT
      LAYER M2 ;
      RECT 126.927 0.000 126.945 0.270 ;
    END
  END r0_rd_out[184]
  PIN r0_rd_out[185]
    DIRECTION OUTPUT ;
    USE SIGNAL ;
    SHAPE ABUTMENT ;
    PORT
      LAYER M2 ;
      RECT 127.215 0.000 127.233 0.270 ;
    END
  END r0_rd_out[185]
  PIN r0_rd_out[186]
    DIRECTION OUTPUT ;
    USE SIGNAL ;
    SHAPE ABUTMENT ;
    PORT
      LAYER M2 ;
      RECT 127.503 0.000 127.521 0.270 ;
    END
  END r0_rd_out[186]
  PIN r0_rd_out[187]
    DIRECTION OUTPUT ;
    USE SIGNAL ;
    SHAPE ABUTMENT ;
    PORT
      LAYER M2 ;
      RECT 127.791 0.000 127.809 0.270 ;
    END
  END r0_rd_out[187]
  PIN r0_rd_out[188]
    DIRECTION OUTPUT ;
    USE SIGNAL ;
    SHAPE ABUTMENT ;
    PORT
      LAYER M2 ;
      RECT 128.079 0.000 128.097 0.270 ;
    END
  END r0_rd_out[188]
  PIN r0_rd_out[189]
    DIRECTION OUTPUT ;
    USE SIGNAL ;
    SHAPE ABUTMENT ;
    PORT
      LAYER M2 ;
      RECT 128.367 0.000 128.385 0.270 ;
    END
  END r0_rd_out[189]
  PIN r0_rd_out[190]
    DIRECTION OUTPUT ;
    USE SIGNAL ;
    SHAPE ABUTMENT ;
    PORT
      LAYER M2 ;
      RECT 128.655 0.000 128.673 0.270 ;
    END
  END r0_rd_out[190]
  PIN r0_rd_out[191]
    DIRECTION OUTPUT ;
    USE SIGNAL ;
    SHAPE ABUTMENT ;
    PORT
      LAYER M2 ;
      RECT 128.943 0.000 128.961 0.270 ;
    END
  END r0_rd_out[191]
  PIN r0_rd_out[192]
    DIRECTION OUTPUT ;
    USE SIGNAL ;
    SHAPE ABUTMENT ;
    PORT
      LAYER M2 ;
      RECT 129.231 0.000 129.249 0.270 ;
    END
  END r0_rd_out[192]
  PIN r0_rd_out[193]
    DIRECTION OUTPUT ;
    USE SIGNAL ;
    SHAPE ABUTMENT ;
    PORT
      LAYER M2 ;
      RECT 129.519 0.000 129.537 0.270 ;
    END
  END r0_rd_out[193]
  PIN r0_rd_out[194]
    DIRECTION OUTPUT ;
    USE SIGNAL ;
    SHAPE ABUTMENT ;
    PORT
      LAYER M2 ;
      RECT 129.807 0.000 129.825 0.270 ;
    END
  END r0_rd_out[194]
  PIN r0_rd_out[195]
    DIRECTION OUTPUT ;
    USE SIGNAL ;
    SHAPE ABUTMENT ;
    PORT
      LAYER M2 ;
      RECT 130.095 0.000 130.113 0.270 ;
    END
  END r0_rd_out[195]
  PIN r0_rd_out[196]
    DIRECTION OUTPUT ;
    USE SIGNAL ;
    SHAPE ABUTMENT ;
    PORT
      LAYER M2 ;
      RECT 130.383 0.000 130.401 0.270 ;
    END
  END r0_rd_out[196]
  PIN r0_rd_out[197]
    DIRECTION OUTPUT ;
    USE SIGNAL ;
    SHAPE ABUTMENT ;
    PORT
      LAYER M2 ;
      RECT 130.671 0.000 130.689 0.270 ;
    END
  END r0_rd_out[197]
  PIN r0_rd_out[198]
    DIRECTION OUTPUT ;
    USE SIGNAL ;
    SHAPE ABUTMENT ;
    PORT
      LAYER M2 ;
      RECT 130.959 0.000 130.977 0.270 ;
    END
  END r0_rd_out[198]
  PIN r0_rd_out[199]
    DIRECTION OUTPUT ;
    USE SIGNAL ;
    SHAPE ABUTMENT ;
    PORT
      LAYER M2 ;
      RECT 131.247 0.000 131.265 0.270 ;
    END
  END r0_rd_out[199]
  PIN r0_rd_out[200]
    DIRECTION OUTPUT ;
    USE SIGNAL ;
    SHAPE ABUTMENT ;
    PORT
      LAYER M2 ;
      RECT 131.535 0.000 131.553 0.270 ;
    END
  END r0_rd_out[200]
  PIN r0_rd_out[201]
    DIRECTION OUTPUT ;
    USE SIGNAL ;
    SHAPE ABUTMENT ;
    PORT
      LAYER M2 ;
      RECT 131.823 0.000 131.841 0.270 ;
    END
  END r0_rd_out[201]
  PIN r0_rd_out[202]
    DIRECTION OUTPUT ;
    USE SIGNAL ;
    SHAPE ABUTMENT ;
    PORT
      LAYER M2 ;
      RECT 132.111 0.000 132.129 0.270 ;
    END
  END r0_rd_out[202]
  PIN r0_rd_out[203]
    DIRECTION OUTPUT ;
    USE SIGNAL ;
    SHAPE ABUTMENT ;
    PORT
      LAYER M2 ;
      RECT 132.399 0.000 132.417 0.270 ;
    END
  END r0_rd_out[203]
  PIN r0_rd_out[204]
    DIRECTION OUTPUT ;
    USE SIGNAL ;
    SHAPE ABUTMENT ;
    PORT
      LAYER M2 ;
      RECT 132.687 0.000 132.705 0.270 ;
    END
  END r0_rd_out[204]
  PIN r0_rd_out[205]
    DIRECTION OUTPUT ;
    USE SIGNAL ;
    SHAPE ABUTMENT ;
    PORT
      LAYER M2 ;
      RECT 132.975 0.000 132.993 0.270 ;
    END
  END r0_rd_out[205]
  PIN r0_rd_out[206]
    DIRECTION OUTPUT ;
    USE SIGNAL ;
    SHAPE ABUTMENT ;
    PORT
      LAYER M2 ;
      RECT 133.263 0.000 133.281 0.270 ;
    END
  END r0_rd_out[206]
  PIN r0_rd_out[207]
    DIRECTION OUTPUT ;
    USE SIGNAL ;
    SHAPE ABUTMENT ;
    PORT
      LAYER M2 ;
      RECT 133.551 0.000 133.569 0.270 ;
    END
  END r0_rd_out[207]
  PIN r0_rd_out[208]
    DIRECTION OUTPUT ;
    USE SIGNAL ;
    SHAPE ABUTMENT ;
    PORT
      LAYER M2 ;
      RECT 133.839 0.000 133.857 0.270 ;
    END
  END r0_rd_out[208]
  PIN r0_rd_out[209]
    DIRECTION OUTPUT ;
    USE SIGNAL ;
    SHAPE ABUTMENT ;
    PORT
      LAYER M2 ;
      RECT 134.127 0.000 134.145 0.270 ;
    END
  END r0_rd_out[209]
  PIN r0_rd_out[210]
    DIRECTION OUTPUT ;
    USE SIGNAL ;
    SHAPE ABUTMENT ;
    PORT
      LAYER M2 ;
      RECT 134.415 0.000 134.433 0.270 ;
    END
  END r0_rd_out[210]
  PIN r0_rd_out[211]
    DIRECTION OUTPUT ;
    USE SIGNAL ;
    SHAPE ABUTMENT ;
    PORT
      LAYER M2 ;
      RECT 134.703 0.000 134.721 0.270 ;
    END
  END r0_rd_out[211]
  PIN r0_rd_out[212]
    DIRECTION OUTPUT ;
    USE SIGNAL ;
    SHAPE ABUTMENT ;
    PORT
      LAYER M2 ;
      RECT 134.991 0.000 135.009 0.270 ;
    END
  END r0_rd_out[212]
  PIN r0_rd_out[213]
    DIRECTION OUTPUT ;
    USE SIGNAL ;
    SHAPE ABUTMENT ;
    PORT
      LAYER M2 ;
      RECT 135.279 0.000 135.297 0.270 ;
    END
  END r0_rd_out[213]
  PIN r0_rd_out[214]
    DIRECTION OUTPUT ;
    USE SIGNAL ;
    SHAPE ABUTMENT ;
    PORT
      LAYER M2 ;
      RECT 135.567 0.000 135.585 0.270 ;
    END
  END r0_rd_out[214]
  PIN r0_rd_out[215]
    DIRECTION OUTPUT ;
    USE SIGNAL ;
    SHAPE ABUTMENT ;
    PORT
      LAYER M2 ;
      RECT 135.855 0.000 135.873 0.270 ;
    END
  END r0_rd_out[215]
  PIN r0_rd_out[216]
    DIRECTION OUTPUT ;
    USE SIGNAL ;
    SHAPE ABUTMENT ;
    PORT
      LAYER M2 ;
      RECT 136.143 0.000 136.161 0.270 ;
    END
  END r0_rd_out[216]
  PIN r0_rd_out[217]
    DIRECTION OUTPUT ;
    USE SIGNAL ;
    SHAPE ABUTMENT ;
    PORT
      LAYER M2 ;
      RECT 136.431 0.000 136.449 0.270 ;
    END
  END r0_rd_out[217]
  PIN r0_rd_out[218]
    DIRECTION OUTPUT ;
    USE SIGNAL ;
    SHAPE ABUTMENT ;
    PORT
      LAYER M2 ;
      RECT 136.719 0.000 136.737 0.270 ;
    END
  END r0_rd_out[218]
  PIN r0_rd_out[219]
    DIRECTION OUTPUT ;
    USE SIGNAL ;
    SHAPE ABUTMENT ;
    PORT
      LAYER M2 ;
      RECT 137.007 0.000 137.025 0.270 ;
    END
  END r0_rd_out[219]
  PIN r0_rd_out[220]
    DIRECTION OUTPUT ;
    USE SIGNAL ;
    SHAPE ABUTMENT ;
    PORT
      LAYER M2 ;
      RECT 137.295 0.000 137.313 0.270 ;
    END
  END r0_rd_out[220]
  PIN r0_rd_out[221]
    DIRECTION OUTPUT ;
    USE SIGNAL ;
    SHAPE ABUTMENT ;
    PORT
      LAYER M2 ;
      RECT 137.583 0.000 137.601 0.270 ;
    END
  END r0_rd_out[221]
  PIN r0_rd_out[222]
    DIRECTION OUTPUT ;
    USE SIGNAL ;
    SHAPE ABUTMENT ;
    PORT
      LAYER M2 ;
      RECT 137.871 0.000 137.889 0.270 ;
    END
  END r0_rd_out[222]
  PIN r0_rd_out[223]
    DIRECTION OUTPUT ;
    USE SIGNAL ;
    SHAPE ABUTMENT ;
    PORT
      LAYER M2 ;
      RECT 138.159 0.000 138.177 0.270 ;
    END
  END r0_rd_out[223]
  PIN r0_rd_out[224]
    DIRECTION OUTPUT ;
    USE SIGNAL ;
    SHAPE ABUTMENT ;
    PORT
      LAYER M2 ;
      RECT 138.447 0.000 138.465 0.270 ;
    END
  END r0_rd_out[224]
  PIN r0_rd_out[225]
    DIRECTION OUTPUT ;
    USE SIGNAL ;
    SHAPE ABUTMENT ;
    PORT
      LAYER M2 ;
      RECT 138.735 0.000 138.753 0.270 ;
    END
  END r0_rd_out[225]
  PIN r0_rd_out[226]
    DIRECTION OUTPUT ;
    USE SIGNAL ;
    SHAPE ABUTMENT ;
    PORT
      LAYER M2 ;
      RECT 139.023 0.000 139.041 0.270 ;
    END
  END r0_rd_out[226]
  PIN r0_rd_out[227]
    DIRECTION OUTPUT ;
    USE SIGNAL ;
    SHAPE ABUTMENT ;
    PORT
      LAYER M2 ;
      RECT 139.311 0.000 139.329 0.270 ;
    END
  END r0_rd_out[227]
  PIN r0_rd_out[228]
    DIRECTION OUTPUT ;
    USE SIGNAL ;
    SHAPE ABUTMENT ;
    PORT
      LAYER M2 ;
      RECT 139.599 0.000 139.617 0.270 ;
    END
  END r0_rd_out[228]
  PIN r0_rd_out[229]
    DIRECTION OUTPUT ;
    USE SIGNAL ;
    SHAPE ABUTMENT ;
    PORT
      LAYER M2 ;
      RECT 139.887 0.000 139.905 0.270 ;
    END
  END r0_rd_out[229]
  PIN r0_rd_out[230]
    DIRECTION OUTPUT ;
    USE SIGNAL ;
    SHAPE ABUTMENT ;
    PORT
      LAYER M2 ;
      RECT 140.175 0.000 140.193 0.270 ;
    END
  END r0_rd_out[230]
  PIN r0_rd_out[231]
    DIRECTION OUTPUT ;
    USE SIGNAL ;
    SHAPE ABUTMENT ;
    PORT
      LAYER M2 ;
      RECT 140.463 0.000 140.481 0.270 ;
    END
  END r0_rd_out[231]
  PIN r0_rd_out[232]
    DIRECTION OUTPUT ;
    USE SIGNAL ;
    SHAPE ABUTMENT ;
    PORT
      LAYER M2 ;
      RECT 140.751 0.000 140.769 0.270 ;
    END
  END r0_rd_out[232]
  PIN r0_rd_out[233]
    DIRECTION OUTPUT ;
    USE SIGNAL ;
    SHAPE ABUTMENT ;
    PORT
      LAYER M2 ;
      RECT 141.039 0.000 141.057 0.270 ;
    END
  END r0_rd_out[233]
  PIN r0_rd_out[234]
    DIRECTION OUTPUT ;
    USE SIGNAL ;
    SHAPE ABUTMENT ;
    PORT
      LAYER M2 ;
      RECT 141.327 0.000 141.345 0.270 ;
    END
  END r0_rd_out[234]
  PIN r0_rd_out[235]
    DIRECTION OUTPUT ;
    USE SIGNAL ;
    SHAPE ABUTMENT ;
    PORT
      LAYER M2 ;
      RECT 141.615 0.000 141.633 0.270 ;
    END
  END r0_rd_out[235]
  PIN r0_rd_out[236]
    DIRECTION OUTPUT ;
    USE SIGNAL ;
    SHAPE ABUTMENT ;
    PORT
      LAYER M2 ;
      RECT 141.903 0.000 141.921 0.270 ;
    END
  END r0_rd_out[236]
  PIN r0_rd_out[237]
    DIRECTION OUTPUT ;
    USE SIGNAL ;
    SHAPE ABUTMENT ;
    PORT
      LAYER M2 ;
      RECT 142.191 0.000 142.209 0.270 ;
    END
  END r0_rd_out[237]
  PIN r0_rd_out[238]
    DIRECTION OUTPUT ;
    USE SIGNAL ;
    SHAPE ABUTMENT ;
    PORT
      LAYER M2 ;
      RECT 142.479 0.000 142.497 0.270 ;
    END
  END r0_rd_out[238]
  PIN r0_rd_out[239]
    DIRECTION OUTPUT ;
    USE SIGNAL ;
    SHAPE ABUTMENT ;
    PORT
      LAYER M2 ;
      RECT 142.767 0.000 142.785 0.270 ;
    END
  END r0_rd_out[239]
  PIN r0_rd_out[240]
    DIRECTION OUTPUT ;
    USE SIGNAL ;
    SHAPE ABUTMENT ;
    PORT
      LAYER M2 ;
      RECT 143.055 0.000 143.073 0.270 ;
    END
  END r0_rd_out[240]
  PIN r0_rd_out[241]
    DIRECTION OUTPUT ;
    USE SIGNAL ;
    SHAPE ABUTMENT ;
    PORT
      LAYER M2 ;
      RECT 143.343 0.000 143.361 0.270 ;
    END
  END r0_rd_out[241]
  PIN r0_rd_out[242]
    DIRECTION OUTPUT ;
    USE SIGNAL ;
    SHAPE ABUTMENT ;
    PORT
      LAYER M2 ;
      RECT 143.631 0.000 143.649 0.270 ;
    END
  END r0_rd_out[242]
  PIN r0_rd_out[243]
    DIRECTION OUTPUT ;
    USE SIGNAL ;
    SHAPE ABUTMENT ;
    PORT
      LAYER M2 ;
      RECT 143.919 0.000 143.937 0.270 ;
    END
  END r0_rd_out[243]
  PIN r0_rd_out[244]
    DIRECTION OUTPUT ;
    USE SIGNAL ;
    SHAPE ABUTMENT ;
    PORT
      LAYER M2 ;
      RECT 144.207 0.000 144.225 0.270 ;
    END
  END r0_rd_out[244]
  PIN r0_rd_out[245]
    DIRECTION OUTPUT ;
    USE SIGNAL ;
    SHAPE ABUTMENT ;
    PORT
      LAYER M2 ;
      RECT 144.495 0.000 144.513 0.270 ;
    END
  END r0_rd_out[245]
  PIN r0_rd_out[246]
    DIRECTION OUTPUT ;
    USE SIGNAL ;
    SHAPE ABUTMENT ;
    PORT
      LAYER M2 ;
      RECT 144.783 0.000 144.801 0.270 ;
    END
  END r0_rd_out[246]
  PIN r0_rd_out[247]
    DIRECTION OUTPUT ;
    USE SIGNAL ;
    SHAPE ABUTMENT ;
    PORT
      LAYER M2 ;
      RECT 145.071 0.000 145.089 0.270 ;
    END
  END r0_rd_out[247]
  PIN r0_rd_out[248]
    DIRECTION OUTPUT ;
    USE SIGNAL ;
    SHAPE ABUTMENT ;
    PORT
      LAYER M2 ;
      RECT 145.359 0.000 145.377 0.270 ;
    END
  END r0_rd_out[248]
  PIN r0_rd_out[249]
    DIRECTION OUTPUT ;
    USE SIGNAL ;
    SHAPE ABUTMENT ;
    PORT
      LAYER M2 ;
      RECT 145.647 0.000 145.665 0.270 ;
    END
  END r0_rd_out[249]
  PIN r0_rd_out[250]
    DIRECTION OUTPUT ;
    USE SIGNAL ;
    SHAPE ABUTMENT ;
    PORT
      LAYER M2 ;
      RECT 145.935 0.000 145.953 0.270 ;
    END
  END r0_rd_out[250]
  PIN r0_rd_out[251]
    DIRECTION OUTPUT ;
    USE SIGNAL ;
    SHAPE ABUTMENT ;
    PORT
      LAYER M2 ;
      RECT 146.223 0.000 146.241 0.270 ;
    END
  END r0_rd_out[251]
  PIN r0_rd_out[252]
    DIRECTION OUTPUT ;
    USE SIGNAL ;
    SHAPE ABUTMENT ;
    PORT
      LAYER M2 ;
      RECT 146.511 0.000 146.529 0.270 ;
    END
  END r0_rd_out[252]
  PIN r0_rd_out[253]
    DIRECTION OUTPUT ;
    USE SIGNAL ;
    SHAPE ABUTMENT ;
    PORT
      LAYER M2 ;
      RECT 146.799 0.000 146.817 0.270 ;
    END
  END r0_rd_out[253]
  PIN r0_rd_out[254]
    DIRECTION OUTPUT ;
    USE SIGNAL ;
    SHAPE ABUTMENT ;
    PORT
      LAYER M2 ;
      RECT 147.087 0.000 147.105 0.270 ;
    END
  END r0_rd_out[254]
  PIN r0_rd_out[255]
    DIRECTION OUTPUT ;
    USE SIGNAL ;
    SHAPE ABUTMENT ;
    PORT
      LAYER M2 ;
      RECT 147.375 0.000 147.393 0.270 ;
    END
  END r0_rd_out[255]
  PIN r0_rd_out[256]
    DIRECTION OUTPUT ;
    USE SIGNAL ;
    SHAPE ABUTMENT ;
    PORT
      LAYER M2 ;
      RECT 0.207 85.590 0.225 85.860 ;
    END
  END r0_rd_out[256]
  PIN r0_rd_out[257]
    DIRECTION OUTPUT ;
    USE SIGNAL ;
    SHAPE ABUTMENT ;
    PORT
      LAYER M2 ;
      RECT 0.783 85.590 0.801 85.860 ;
    END
  END r0_rd_out[257]
  PIN r0_rd_out[258]
    DIRECTION OUTPUT ;
    USE SIGNAL ;
    SHAPE ABUTMENT ;
    PORT
      LAYER M2 ;
      RECT 1.359 85.590 1.377 85.860 ;
    END
  END r0_rd_out[258]
  PIN r0_rd_out[259]
    DIRECTION OUTPUT ;
    USE SIGNAL ;
    SHAPE ABUTMENT ;
    PORT
      LAYER M2 ;
      RECT 1.935 85.590 1.953 85.860 ;
    END
  END r0_rd_out[259]
  PIN r0_rd_out[260]
    DIRECTION OUTPUT ;
    USE SIGNAL ;
    SHAPE ABUTMENT ;
    PORT
      LAYER M2 ;
      RECT 2.511 85.590 2.529 85.860 ;
    END
  END r0_rd_out[260]
  PIN r0_rd_out[261]
    DIRECTION OUTPUT ;
    USE SIGNAL ;
    SHAPE ABUTMENT ;
    PORT
      LAYER M2 ;
      RECT 3.087 85.590 3.105 85.860 ;
    END
  END r0_rd_out[261]
  PIN r0_rd_out[262]
    DIRECTION OUTPUT ;
    USE SIGNAL ;
    SHAPE ABUTMENT ;
    PORT
      LAYER M2 ;
      RECT 3.663 85.590 3.681 85.860 ;
    END
  END r0_rd_out[262]
  PIN r0_rd_out[263]
    DIRECTION OUTPUT ;
    USE SIGNAL ;
    SHAPE ABUTMENT ;
    PORT
      LAYER M2 ;
      RECT 4.239 85.590 4.257 85.860 ;
    END
  END r0_rd_out[263]
  PIN r0_rd_out[264]
    DIRECTION OUTPUT ;
    USE SIGNAL ;
    SHAPE ABUTMENT ;
    PORT
      LAYER M2 ;
      RECT 4.815 85.590 4.833 85.860 ;
    END
  END r0_rd_out[264]
  PIN r0_rd_out[265]
    DIRECTION OUTPUT ;
    USE SIGNAL ;
    SHAPE ABUTMENT ;
    PORT
      LAYER M2 ;
      RECT 5.391 85.590 5.409 85.860 ;
    END
  END r0_rd_out[265]
  PIN r0_rd_out[266]
    DIRECTION OUTPUT ;
    USE SIGNAL ;
    SHAPE ABUTMENT ;
    PORT
      LAYER M2 ;
      RECT 5.967 85.590 5.985 85.860 ;
    END
  END r0_rd_out[266]
  PIN r0_rd_out[267]
    DIRECTION OUTPUT ;
    USE SIGNAL ;
    SHAPE ABUTMENT ;
    PORT
      LAYER M2 ;
      RECT 6.543 85.590 6.561 85.860 ;
    END
  END r0_rd_out[267]
  PIN r0_rd_out[268]
    DIRECTION OUTPUT ;
    USE SIGNAL ;
    SHAPE ABUTMENT ;
    PORT
      LAYER M2 ;
      RECT 7.119 85.590 7.137 85.860 ;
    END
  END r0_rd_out[268]
  PIN r0_rd_out[269]
    DIRECTION OUTPUT ;
    USE SIGNAL ;
    SHAPE ABUTMENT ;
    PORT
      LAYER M2 ;
      RECT 7.695 85.590 7.713 85.860 ;
    END
  END r0_rd_out[269]
  PIN r0_rd_out[270]
    DIRECTION OUTPUT ;
    USE SIGNAL ;
    SHAPE ABUTMENT ;
    PORT
      LAYER M2 ;
      RECT 8.271 85.590 8.289 85.860 ;
    END
  END r0_rd_out[270]
  PIN r0_rd_out[271]
    DIRECTION OUTPUT ;
    USE SIGNAL ;
    SHAPE ABUTMENT ;
    PORT
      LAYER M2 ;
      RECT 8.847 85.590 8.865 85.860 ;
    END
  END r0_rd_out[271]
  PIN r0_rd_out[272]
    DIRECTION OUTPUT ;
    USE SIGNAL ;
    SHAPE ABUTMENT ;
    PORT
      LAYER M2 ;
      RECT 9.423 85.590 9.441 85.860 ;
    END
  END r0_rd_out[272]
  PIN r0_rd_out[273]
    DIRECTION OUTPUT ;
    USE SIGNAL ;
    SHAPE ABUTMENT ;
    PORT
      LAYER M2 ;
      RECT 9.999 85.590 10.017 85.860 ;
    END
  END r0_rd_out[273]
  PIN r0_rd_out[274]
    DIRECTION OUTPUT ;
    USE SIGNAL ;
    SHAPE ABUTMENT ;
    PORT
      LAYER M2 ;
      RECT 10.575 85.590 10.593 85.860 ;
    END
  END r0_rd_out[274]
  PIN r0_rd_out[275]
    DIRECTION OUTPUT ;
    USE SIGNAL ;
    SHAPE ABUTMENT ;
    PORT
      LAYER M2 ;
      RECT 11.151 85.590 11.169 85.860 ;
    END
  END r0_rd_out[275]
  PIN r0_rd_out[276]
    DIRECTION OUTPUT ;
    USE SIGNAL ;
    SHAPE ABUTMENT ;
    PORT
      LAYER M2 ;
      RECT 11.727 85.590 11.745 85.860 ;
    END
  END r0_rd_out[276]
  PIN r0_rd_out[277]
    DIRECTION OUTPUT ;
    USE SIGNAL ;
    SHAPE ABUTMENT ;
    PORT
      LAYER M2 ;
      RECT 12.303 85.590 12.321 85.860 ;
    END
  END r0_rd_out[277]
  PIN r0_rd_out[278]
    DIRECTION OUTPUT ;
    USE SIGNAL ;
    SHAPE ABUTMENT ;
    PORT
      LAYER M2 ;
      RECT 12.879 85.590 12.897 85.860 ;
    END
  END r0_rd_out[278]
  PIN r0_rd_out[279]
    DIRECTION OUTPUT ;
    USE SIGNAL ;
    SHAPE ABUTMENT ;
    PORT
      LAYER M2 ;
      RECT 13.455 85.590 13.473 85.860 ;
    END
  END r0_rd_out[279]
  PIN r0_rd_out[280]
    DIRECTION OUTPUT ;
    USE SIGNAL ;
    SHAPE ABUTMENT ;
    PORT
      LAYER M2 ;
      RECT 14.031 85.590 14.049 85.860 ;
    END
  END r0_rd_out[280]
  PIN r0_rd_out[281]
    DIRECTION OUTPUT ;
    USE SIGNAL ;
    SHAPE ABUTMENT ;
    PORT
      LAYER M2 ;
      RECT 14.607 85.590 14.625 85.860 ;
    END
  END r0_rd_out[281]
  PIN r0_rd_out[282]
    DIRECTION OUTPUT ;
    USE SIGNAL ;
    SHAPE ABUTMENT ;
    PORT
      LAYER M2 ;
      RECT 15.183 85.590 15.201 85.860 ;
    END
  END r0_rd_out[282]
  PIN r0_rd_out[283]
    DIRECTION OUTPUT ;
    USE SIGNAL ;
    SHAPE ABUTMENT ;
    PORT
      LAYER M2 ;
      RECT 15.759 85.590 15.777 85.860 ;
    END
  END r0_rd_out[283]
  PIN r0_rd_out[284]
    DIRECTION OUTPUT ;
    USE SIGNAL ;
    SHAPE ABUTMENT ;
    PORT
      LAYER M2 ;
      RECT 16.335 85.590 16.353 85.860 ;
    END
  END r0_rd_out[284]
  PIN r0_rd_out[285]
    DIRECTION OUTPUT ;
    USE SIGNAL ;
    SHAPE ABUTMENT ;
    PORT
      LAYER M2 ;
      RECT 16.911 85.590 16.929 85.860 ;
    END
  END r0_rd_out[285]
  PIN r0_rd_out[286]
    DIRECTION OUTPUT ;
    USE SIGNAL ;
    SHAPE ABUTMENT ;
    PORT
      LAYER M2 ;
      RECT 17.487 85.590 17.505 85.860 ;
    END
  END r0_rd_out[286]
  PIN r0_rd_out[287]
    DIRECTION OUTPUT ;
    USE SIGNAL ;
    SHAPE ABUTMENT ;
    PORT
      LAYER M2 ;
      RECT 18.063 85.590 18.081 85.860 ;
    END
  END r0_rd_out[287]
  PIN r0_rd_out[288]
    DIRECTION OUTPUT ;
    USE SIGNAL ;
    SHAPE ABUTMENT ;
    PORT
      LAYER M2 ;
      RECT 18.639 85.590 18.657 85.860 ;
    END
  END r0_rd_out[288]
  PIN r0_rd_out[289]
    DIRECTION OUTPUT ;
    USE SIGNAL ;
    SHAPE ABUTMENT ;
    PORT
      LAYER M2 ;
      RECT 19.215 85.590 19.233 85.860 ;
    END
  END r0_rd_out[289]
  PIN r0_rd_out[290]
    DIRECTION OUTPUT ;
    USE SIGNAL ;
    SHAPE ABUTMENT ;
    PORT
      LAYER M2 ;
      RECT 19.791 85.590 19.809 85.860 ;
    END
  END r0_rd_out[290]
  PIN r0_rd_out[291]
    DIRECTION OUTPUT ;
    USE SIGNAL ;
    SHAPE ABUTMENT ;
    PORT
      LAYER M2 ;
      RECT 20.367 85.590 20.385 85.860 ;
    END
  END r0_rd_out[291]
  PIN r0_rd_out[292]
    DIRECTION OUTPUT ;
    USE SIGNAL ;
    SHAPE ABUTMENT ;
    PORT
      LAYER M2 ;
      RECT 20.943 85.590 20.961 85.860 ;
    END
  END r0_rd_out[292]
  PIN r0_rd_out[293]
    DIRECTION OUTPUT ;
    USE SIGNAL ;
    SHAPE ABUTMENT ;
    PORT
      LAYER M2 ;
      RECT 21.519 85.590 21.537 85.860 ;
    END
  END r0_rd_out[293]
  PIN r0_rd_out[294]
    DIRECTION OUTPUT ;
    USE SIGNAL ;
    SHAPE ABUTMENT ;
    PORT
      LAYER M2 ;
      RECT 22.095 85.590 22.113 85.860 ;
    END
  END r0_rd_out[294]
  PIN r0_rd_out[295]
    DIRECTION OUTPUT ;
    USE SIGNAL ;
    SHAPE ABUTMENT ;
    PORT
      LAYER M2 ;
      RECT 22.671 85.590 22.689 85.860 ;
    END
  END r0_rd_out[295]
  PIN r0_rd_out[296]
    DIRECTION OUTPUT ;
    USE SIGNAL ;
    SHAPE ABUTMENT ;
    PORT
      LAYER M2 ;
      RECT 23.247 85.590 23.265 85.860 ;
    END
  END r0_rd_out[296]
  PIN r0_rd_out[297]
    DIRECTION OUTPUT ;
    USE SIGNAL ;
    SHAPE ABUTMENT ;
    PORT
      LAYER M2 ;
      RECT 23.823 85.590 23.841 85.860 ;
    END
  END r0_rd_out[297]
  PIN r0_rd_out[298]
    DIRECTION OUTPUT ;
    USE SIGNAL ;
    SHAPE ABUTMENT ;
    PORT
      LAYER M2 ;
      RECT 24.399 85.590 24.417 85.860 ;
    END
  END r0_rd_out[298]
  PIN r0_rd_out[299]
    DIRECTION OUTPUT ;
    USE SIGNAL ;
    SHAPE ABUTMENT ;
    PORT
      LAYER M2 ;
      RECT 24.975 85.590 24.993 85.860 ;
    END
  END r0_rd_out[299]
  PIN r0_rd_out[300]
    DIRECTION OUTPUT ;
    USE SIGNAL ;
    SHAPE ABUTMENT ;
    PORT
      LAYER M2 ;
      RECT 25.551 85.590 25.569 85.860 ;
    END
  END r0_rd_out[300]
  PIN r0_rd_out[301]
    DIRECTION OUTPUT ;
    USE SIGNAL ;
    SHAPE ABUTMENT ;
    PORT
      LAYER M2 ;
      RECT 26.127 85.590 26.145 85.860 ;
    END
  END r0_rd_out[301]
  PIN r0_rd_out[302]
    DIRECTION OUTPUT ;
    USE SIGNAL ;
    SHAPE ABUTMENT ;
    PORT
      LAYER M2 ;
      RECT 26.703 85.590 26.721 85.860 ;
    END
  END r0_rd_out[302]
  PIN r0_rd_out[303]
    DIRECTION OUTPUT ;
    USE SIGNAL ;
    SHAPE ABUTMENT ;
    PORT
      LAYER M2 ;
      RECT 27.279 85.590 27.297 85.860 ;
    END
  END r0_rd_out[303]
  PIN r0_rd_out[304]
    DIRECTION OUTPUT ;
    USE SIGNAL ;
    SHAPE ABUTMENT ;
    PORT
      LAYER M2 ;
      RECT 27.855 85.590 27.873 85.860 ;
    END
  END r0_rd_out[304]
  PIN r0_rd_out[305]
    DIRECTION OUTPUT ;
    USE SIGNAL ;
    SHAPE ABUTMENT ;
    PORT
      LAYER M2 ;
      RECT 28.431 85.590 28.449 85.860 ;
    END
  END r0_rd_out[305]
  PIN r0_rd_out[306]
    DIRECTION OUTPUT ;
    USE SIGNAL ;
    SHAPE ABUTMENT ;
    PORT
      LAYER M2 ;
      RECT 29.007 85.590 29.025 85.860 ;
    END
  END r0_rd_out[306]
  PIN r0_rd_out[307]
    DIRECTION OUTPUT ;
    USE SIGNAL ;
    SHAPE ABUTMENT ;
    PORT
      LAYER M2 ;
      RECT 29.583 85.590 29.601 85.860 ;
    END
  END r0_rd_out[307]
  PIN r0_rd_out[308]
    DIRECTION OUTPUT ;
    USE SIGNAL ;
    SHAPE ABUTMENT ;
    PORT
      LAYER M2 ;
      RECT 30.159 85.590 30.177 85.860 ;
    END
  END r0_rd_out[308]
  PIN r0_rd_out[309]
    DIRECTION OUTPUT ;
    USE SIGNAL ;
    SHAPE ABUTMENT ;
    PORT
      LAYER M2 ;
      RECT 30.735 85.590 30.753 85.860 ;
    END
  END r0_rd_out[309]
  PIN r0_rd_out[310]
    DIRECTION OUTPUT ;
    USE SIGNAL ;
    SHAPE ABUTMENT ;
    PORT
      LAYER M2 ;
      RECT 31.311 85.590 31.329 85.860 ;
    END
  END r0_rd_out[310]
  PIN r0_rd_out[311]
    DIRECTION OUTPUT ;
    USE SIGNAL ;
    SHAPE ABUTMENT ;
    PORT
      LAYER M2 ;
      RECT 31.887 85.590 31.905 85.860 ;
    END
  END r0_rd_out[311]
  PIN r0_rd_out[312]
    DIRECTION OUTPUT ;
    USE SIGNAL ;
    SHAPE ABUTMENT ;
    PORT
      LAYER M2 ;
      RECT 32.463 85.590 32.481 85.860 ;
    END
  END r0_rd_out[312]
  PIN r0_rd_out[313]
    DIRECTION OUTPUT ;
    USE SIGNAL ;
    SHAPE ABUTMENT ;
    PORT
      LAYER M2 ;
      RECT 33.039 85.590 33.057 85.860 ;
    END
  END r0_rd_out[313]
  PIN r0_rd_out[314]
    DIRECTION OUTPUT ;
    USE SIGNAL ;
    SHAPE ABUTMENT ;
    PORT
      LAYER M2 ;
      RECT 33.615 85.590 33.633 85.860 ;
    END
  END r0_rd_out[314]
  PIN r0_rd_out[315]
    DIRECTION OUTPUT ;
    USE SIGNAL ;
    SHAPE ABUTMENT ;
    PORT
      LAYER M2 ;
      RECT 34.191 85.590 34.209 85.860 ;
    END
  END r0_rd_out[315]
  PIN r0_rd_out[316]
    DIRECTION OUTPUT ;
    USE SIGNAL ;
    SHAPE ABUTMENT ;
    PORT
      LAYER M2 ;
      RECT 34.767 85.590 34.785 85.860 ;
    END
  END r0_rd_out[316]
  PIN r0_rd_out[317]
    DIRECTION OUTPUT ;
    USE SIGNAL ;
    SHAPE ABUTMENT ;
    PORT
      LAYER M2 ;
      RECT 35.343 85.590 35.361 85.860 ;
    END
  END r0_rd_out[317]
  PIN r0_rd_out[318]
    DIRECTION OUTPUT ;
    USE SIGNAL ;
    SHAPE ABUTMENT ;
    PORT
      LAYER M2 ;
      RECT 35.919 85.590 35.937 85.860 ;
    END
  END r0_rd_out[318]
  PIN r0_rd_out[319]
    DIRECTION OUTPUT ;
    USE SIGNAL ;
    SHAPE ABUTMENT ;
    PORT
      LAYER M2 ;
      RECT 36.495 85.590 36.513 85.860 ;
    END
  END r0_rd_out[319]
  PIN r0_rd_out[320]
    DIRECTION OUTPUT ;
    USE SIGNAL ;
    SHAPE ABUTMENT ;
    PORT
      LAYER M2 ;
      RECT 37.071 85.590 37.089 85.860 ;
    END
  END r0_rd_out[320]
  PIN r0_rd_out[321]
    DIRECTION OUTPUT ;
    USE SIGNAL ;
    SHAPE ABUTMENT ;
    PORT
      LAYER M2 ;
      RECT 37.647 85.590 37.665 85.860 ;
    END
  END r0_rd_out[321]
  PIN r0_rd_out[322]
    DIRECTION OUTPUT ;
    USE SIGNAL ;
    SHAPE ABUTMENT ;
    PORT
      LAYER M2 ;
      RECT 38.223 85.590 38.241 85.860 ;
    END
  END r0_rd_out[322]
  PIN r0_rd_out[323]
    DIRECTION OUTPUT ;
    USE SIGNAL ;
    SHAPE ABUTMENT ;
    PORT
      LAYER M2 ;
      RECT 38.799 85.590 38.817 85.860 ;
    END
  END r0_rd_out[323]
  PIN r0_rd_out[324]
    DIRECTION OUTPUT ;
    USE SIGNAL ;
    SHAPE ABUTMENT ;
    PORT
      LAYER M2 ;
      RECT 39.375 85.590 39.393 85.860 ;
    END
  END r0_rd_out[324]
  PIN r0_rd_out[325]
    DIRECTION OUTPUT ;
    USE SIGNAL ;
    SHAPE ABUTMENT ;
    PORT
      LAYER M2 ;
      RECT 39.951 85.590 39.969 85.860 ;
    END
  END r0_rd_out[325]
  PIN r0_rd_out[326]
    DIRECTION OUTPUT ;
    USE SIGNAL ;
    SHAPE ABUTMENT ;
    PORT
      LAYER M2 ;
      RECT 40.527 85.590 40.545 85.860 ;
    END
  END r0_rd_out[326]
  PIN r0_rd_out[327]
    DIRECTION OUTPUT ;
    USE SIGNAL ;
    SHAPE ABUTMENT ;
    PORT
      LAYER M2 ;
      RECT 41.103 85.590 41.121 85.860 ;
    END
  END r0_rd_out[327]
  PIN r0_rd_out[328]
    DIRECTION OUTPUT ;
    USE SIGNAL ;
    SHAPE ABUTMENT ;
    PORT
      LAYER M2 ;
      RECT 41.679 85.590 41.697 85.860 ;
    END
  END r0_rd_out[328]
  PIN r0_rd_out[329]
    DIRECTION OUTPUT ;
    USE SIGNAL ;
    SHAPE ABUTMENT ;
    PORT
      LAYER M2 ;
      RECT 42.255 85.590 42.273 85.860 ;
    END
  END r0_rd_out[329]
  PIN r0_rd_out[330]
    DIRECTION OUTPUT ;
    USE SIGNAL ;
    SHAPE ABUTMENT ;
    PORT
      LAYER M2 ;
      RECT 42.831 85.590 42.849 85.860 ;
    END
  END r0_rd_out[330]
  PIN r0_rd_out[331]
    DIRECTION OUTPUT ;
    USE SIGNAL ;
    SHAPE ABUTMENT ;
    PORT
      LAYER M2 ;
      RECT 43.407 85.590 43.425 85.860 ;
    END
  END r0_rd_out[331]
  PIN r0_rd_out[332]
    DIRECTION OUTPUT ;
    USE SIGNAL ;
    SHAPE ABUTMENT ;
    PORT
      LAYER M2 ;
      RECT 43.983 85.590 44.001 85.860 ;
    END
  END r0_rd_out[332]
  PIN r0_rd_out[333]
    DIRECTION OUTPUT ;
    USE SIGNAL ;
    SHAPE ABUTMENT ;
    PORT
      LAYER M2 ;
      RECT 44.559 85.590 44.577 85.860 ;
    END
  END r0_rd_out[333]
  PIN r0_rd_out[334]
    DIRECTION OUTPUT ;
    USE SIGNAL ;
    SHAPE ABUTMENT ;
    PORT
      LAYER M2 ;
      RECT 45.135 85.590 45.153 85.860 ;
    END
  END r0_rd_out[334]
  PIN r0_rd_out[335]
    DIRECTION OUTPUT ;
    USE SIGNAL ;
    SHAPE ABUTMENT ;
    PORT
      LAYER M2 ;
      RECT 45.711 85.590 45.729 85.860 ;
    END
  END r0_rd_out[335]
  PIN r0_rd_out[336]
    DIRECTION OUTPUT ;
    USE SIGNAL ;
    SHAPE ABUTMENT ;
    PORT
      LAYER M2 ;
      RECT 46.287 85.590 46.305 85.860 ;
    END
  END r0_rd_out[336]
  PIN r0_rd_out[337]
    DIRECTION OUTPUT ;
    USE SIGNAL ;
    SHAPE ABUTMENT ;
    PORT
      LAYER M2 ;
      RECT 46.863 85.590 46.881 85.860 ;
    END
  END r0_rd_out[337]
  PIN r0_rd_out[338]
    DIRECTION OUTPUT ;
    USE SIGNAL ;
    SHAPE ABUTMENT ;
    PORT
      LAYER M2 ;
      RECT 47.439 85.590 47.457 85.860 ;
    END
  END r0_rd_out[338]
  PIN r0_rd_out[339]
    DIRECTION OUTPUT ;
    USE SIGNAL ;
    SHAPE ABUTMENT ;
    PORT
      LAYER M2 ;
      RECT 48.015 85.590 48.033 85.860 ;
    END
  END r0_rd_out[339]
  PIN r0_rd_out[340]
    DIRECTION OUTPUT ;
    USE SIGNAL ;
    SHAPE ABUTMENT ;
    PORT
      LAYER M2 ;
      RECT 48.591 85.590 48.609 85.860 ;
    END
  END r0_rd_out[340]
  PIN r0_rd_out[341]
    DIRECTION OUTPUT ;
    USE SIGNAL ;
    SHAPE ABUTMENT ;
    PORT
      LAYER M2 ;
      RECT 49.167 85.590 49.185 85.860 ;
    END
  END r0_rd_out[341]
  PIN r0_rd_out[342]
    DIRECTION OUTPUT ;
    USE SIGNAL ;
    SHAPE ABUTMENT ;
    PORT
      LAYER M2 ;
      RECT 49.743 85.590 49.761 85.860 ;
    END
  END r0_rd_out[342]
  PIN r0_rd_out[343]
    DIRECTION OUTPUT ;
    USE SIGNAL ;
    SHAPE ABUTMENT ;
    PORT
      LAYER M2 ;
      RECT 50.319 85.590 50.337 85.860 ;
    END
  END r0_rd_out[343]
  PIN r0_rd_out[344]
    DIRECTION OUTPUT ;
    USE SIGNAL ;
    SHAPE ABUTMENT ;
    PORT
      LAYER M2 ;
      RECT 50.895 85.590 50.913 85.860 ;
    END
  END r0_rd_out[344]
  PIN r0_rd_out[345]
    DIRECTION OUTPUT ;
    USE SIGNAL ;
    SHAPE ABUTMENT ;
    PORT
      LAYER M2 ;
      RECT 51.471 85.590 51.489 85.860 ;
    END
  END r0_rd_out[345]
  PIN r0_rd_out[346]
    DIRECTION OUTPUT ;
    USE SIGNAL ;
    SHAPE ABUTMENT ;
    PORT
      LAYER M2 ;
      RECT 52.047 85.590 52.065 85.860 ;
    END
  END r0_rd_out[346]
  PIN r0_rd_out[347]
    DIRECTION OUTPUT ;
    USE SIGNAL ;
    SHAPE ABUTMENT ;
    PORT
      LAYER M2 ;
      RECT 52.623 85.590 52.641 85.860 ;
    END
  END r0_rd_out[347]
  PIN r0_rd_out[348]
    DIRECTION OUTPUT ;
    USE SIGNAL ;
    SHAPE ABUTMENT ;
    PORT
      LAYER M2 ;
      RECT 53.199 85.590 53.217 85.860 ;
    END
  END r0_rd_out[348]
  PIN r0_rd_out[349]
    DIRECTION OUTPUT ;
    USE SIGNAL ;
    SHAPE ABUTMENT ;
    PORT
      LAYER M2 ;
      RECT 53.775 85.590 53.793 85.860 ;
    END
  END r0_rd_out[349]
  PIN r0_rd_out[350]
    DIRECTION OUTPUT ;
    USE SIGNAL ;
    SHAPE ABUTMENT ;
    PORT
      LAYER M2 ;
      RECT 54.351 85.590 54.369 85.860 ;
    END
  END r0_rd_out[350]
  PIN r0_rd_out[351]
    DIRECTION OUTPUT ;
    USE SIGNAL ;
    SHAPE ABUTMENT ;
    PORT
      LAYER M2 ;
      RECT 54.927 85.590 54.945 85.860 ;
    END
  END r0_rd_out[351]
  PIN r0_rd_out[352]
    DIRECTION OUTPUT ;
    USE SIGNAL ;
    SHAPE ABUTMENT ;
    PORT
      LAYER M2 ;
      RECT 55.503 85.590 55.521 85.860 ;
    END
  END r0_rd_out[352]
  PIN r0_rd_out[353]
    DIRECTION OUTPUT ;
    USE SIGNAL ;
    SHAPE ABUTMENT ;
    PORT
      LAYER M2 ;
      RECT 56.079 85.590 56.097 85.860 ;
    END
  END r0_rd_out[353]
  PIN r0_rd_out[354]
    DIRECTION OUTPUT ;
    USE SIGNAL ;
    SHAPE ABUTMENT ;
    PORT
      LAYER M2 ;
      RECT 56.655 85.590 56.673 85.860 ;
    END
  END r0_rd_out[354]
  PIN r0_rd_out[355]
    DIRECTION OUTPUT ;
    USE SIGNAL ;
    SHAPE ABUTMENT ;
    PORT
      LAYER M2 ;
      RECT 57.231 85.590 57.249 85.860 ;
    END
  END r0_rd_out[355]
  PIN r0_rd_out[356]
    DIRECTION OUTPUT ;
    USE SIGNAL ;
    SHAPE ABUTMENT ;
    PORT
      LAYER M2 ;
      RECT 57.807 85.590 57.825 85.860 ;
    END
  END r0_rd_out[356]
  PIN r0_rd_out[357]
    DIRECTION OUTPUT ;
    USE SIGNAL ;
    SHAPE ABUTMENT ;
    PORT
      LAYER M2 ;
      RECT 58.383 85.590 58.401 85.860 ;
    END
  END r0_rd_out[357]
  PIN r0_rd_out[358]
    DIRECTION OUTPUT ;
    USE SIGNAL ;
    SHAPE ABUTMENT ;
    PORT
      LAYER M2 ;
      RECT 58.959 85.590 58.977 85.860 ;
    END
  END r0_rd_out[358]
  PIN r0_rd_out[359]
    DIRECTION OUTPUT ;
    USE SIGNAL ;
    SHAPE ABUTMENT ;
    PORT
      LAYER M2 ;
      RECT 59.535 85.590 59.553 85.860 ;
    END
  END r0_rd_out[359]
  PIN r0_rd_out[360]
    DIRECTION OUTPUT ;
    USE SIGNAL ;
    SHAPE ABUTMENT ;
    PORT
      LAYER M2 ;
      RECT 60.111 85.590 60.129 85.860 ;
    END
  END r0_rd_out[360]
  PIN r0_rd_out[361]
    DIRECTION OUTPUT ;
    USE SIGNAL ;
    SHAPE ABUTMENT ;
    PORT
      LAYER M2 ;
      RECT 60.687 85.590 60.705 85.860 ;
    END
  END r0_rd_out[361]
  PIN r0_rd_out[362]
    DIRECTION OUTPUT ;
    USE SIGNAL ;
    SHAPE ABUTMENT ;
    PORT
      LAYER M2 ;
      RECT 61.263 85.590 61.281 85.860 ;
    END
  END r0_rd_out[362]
  PIN r0_rd_out[363]
    DIRECTION OUTPUT ;
    USE SIGNAL ;
    SHAPE ABUTMENT ;
    PORT
      LAYER M2 ;
      RECT 61.839 85.590 61.857 85.860 ;
    END
  END r0_rd_out[363]
  PIN r0_rd_out[364]
    DIRECTION OUTPUT ;
    USE SIGNAL ;
    SHAPE ABUTMENT ;
    PORT
      LAYER M2 ;
      RECT 62.415 85.590 62.433 85.860 ;
    END
  END r0_rd_out[364]
  PIN r0_rd_out[365]
    DIRECTION OUTPUT ;
    USE SIGNAL ;
    SHAPE ABUTMENT ;
    PORT
      LAYER M2 ;
      RECT 62.991 85.590 63.009 85.860 ;
    END
  END r0_rd_out[365]
  PIN r0_rd_out[366]
    DIRECTION OUTPUT ;
    USE SIGNAL ;
    SHAPE ABUTMENT ;
    PORT
      LAYER M2 ;
      RECT 63.567 85.590 63.585 85.860 ;
    END
  END r0_rd_out[366]
  PIN r0_rd_out[367]
    DIRECTION OUTPUT ;
    USE SIGNAL ;
    SHAPE ABUTMENT ;
    PORT
      LAYER M2 ;
      RECT 64.143 85.590 64.161 85.860 ;
    END
  END r0_rd_out[367]
  PIN r0_rd_out[368]
    DIRECTION OUTPUT ;
    USE SIGNAL ;
    SHAPE ABUTMENT ;
    PORT
      LAYER M2 ;
      RECT 64.719 85.590 64.737 85.860 ;
    END
  END r0_rd_out[368]
  PIN r0_rd_out[369]
    DIRECTION OUTPUT ;
    USE SIGNAL ;
    SHAPE ABUTMENT ;
    PORT
      LAYER M2 ;
      RECT 65.295 85.590 65.313 85.860 ;
    END
  END r0_rd_out[369]
  PIN r0_rd_out[370]
    DIRECTION OUTPUT ;
    USE SIGNAL ;
    SHAPE ABUTMENT ;
    PORT
      LAYER M2 ;
      RECT 65.871 85.590 65.889 85.860 ;
    END
  END r0_rd_out[370]
  PIN r0_rd_out[371]
    DIRECTION OUTPUT ;
    USE SIGNAL ;
    SHAPE ABUTMENT ;
    PORT
      LAYER M2 ;
      RECT 66.447 85.590 66.465 85.860 ;
    END
  END r0_rd_out[371]
  PIN r0_rd_out[372]
    DIRECTION OUTPUT ;
    USE SIGNAL ;
    SHAPE ABUTMENT ;
    PORT
      LAYER M2 ;
      RECT 67.023 85.590 67.041 85.860 ;
    END
  END r0_rd_out[372]
  PIN r0_rd_out[373]
    DIRECTION OUTPUT ;
    USE SIGNAL ;
    SHAPE ABUTMENT ;
    PORT
      LAYER M2 ;
      RECT 67.599 85.590 67.617 85.860 ;
    END
  END r0_rd_out[373]
  PIN r0_rd_out[374]
    DIRECTION OUTPUT ;
    USE SIGNAL ;
    SHAPE ABUTMENT ;
    PORT
      LAYER M2 ;
      RECT 68.175 85.590 68.193 85.860 ;
    END
  END r0_rd_out[374]
  PIN r0_rd_out[375]
    DIRECTION OUTPUT ;
    USE SIGNAL ;
    SHAPE ABUTMENT ;
    PORT
      LAYER M2 ;
      RECT 68.751 85.590 68.769 85.860 ;
    END
  END r0_rd_out[375]
  PIN r0_rd_out[376]
    DIRECTION OUTPUT ;
    USE SIGNAL ;
    SHAPE ABUTMENT ;
    PORT
      LAYER M2 ;
      RECT 69.327 85.590 69.345 85.860 ;
    END
  END r0_rd_out[376]
  PIN r0_rd_out[377]
    DIRECTION OUTPUT ;
    USE SIGNAL ;
    SHAPE ABUTMENT ;
    PORT
      LAYER M2 ;
      RECT 69.903 85.590 69.921 85.860 ;
    END
  END r0_rd_out[377]
  PIN r0_rd_out[378]
    DIRECTION OUTPUT ;
    USE SIGNAL ;
    SHAPE ABUTMENT ;
    PORT
      LAYER M2 ;
      RECT 70.479 85.590 70.497 85.860 ;
    END
  END r0_rd_out[378]
  PIN r0_rd_out[379]
    DIRECTION OUTPUT ;
    USE SIGNAL ;
    SHAPE ABUTMENT ;
    PORT
      LAYER M2 ;
      RECT 71.055 85.590 71.073 85.860 ;
    END
  END r0_rd_out[379]
  PIN r0_rd_out[380]
    DIRECTION OUTPUT ;
    USE SIGNAL ;
    SHAPE ABUTMENT ;
    PORT
      LAYER M2 ;
      RECT 71.631 85.590 71.649 85.860 ;
    END
  END r0_rd_out[380]
  PIN r0_rd_out[381]
    DIRECTION OUTPUT ;
    USE SIGNAL ;
    SHAPE ABUTMENT ;
    PORT
      LAYER M2 ;
      RECT 72.207 85.590 72.225 85.860 ;
    END
  END r0_rd_out[381]
  PIN r0_rd_out[382]
    DIRECTION OUTPUT ;
    USE SIGNAL ;
    SHAPE ABUTMENT ;
    PORT
      LAYER M2 ;
      RECT 72.783 85.590 72.801 85.860 ;
    END
  END r0_rd_out[382]
  PIN r0_rd_out[383]
    DIRECTION OUTPUT ;
    USE SIGNAL ;
    SHAPE ABUTMENT ;
    PORT
      LAYER M2 ;
      RECT 73.359 85.590 73.377 85.860 ;
    END
  END r0_rd_out[383]
  PIN r0_rd_out[384]
    DIRECTION OUTPUT ;
    USE SIGNAL ;
    SHAPE ABUTMENT ;
    PORT
      LAYER M2 ;
      RECT 73.935 85.590 73.953 85.860 ;
    END
  END r0_rd_out[384]
  PIN r0_rd_out[385]
    DIRECTION OUTPUT ;
    USE SIGNAL ;
    SHAPE ABUTMENT ;
    PORT
      LAYER M2 ;
      RECT 74.511 85.590 74.529 85.860 ;
    END
  END r0_rd_out[385]
  PIN r0_rd_out[386]
    DIRECTION OUTPUT ;
    USE SIGNAL ;
    SHAPE ABUTMENT ;
    PORT
      LAYER M2 ;
      RECT 75.087 85.590 75.105 85.860 ;
    END
  END r0_rd_out[386]
  PIN r0_rd_out[387]
    DIRECTION OUTPUT ;
    USE SIGNAL ;
    SHAPE ABUTMENT ;
    PORT
      LAYER M2 ;
      RECT 75.663 85.590 75.681 85.860 ;
    END
  END r0_rd_out[387]
  PIN r0_rd_out[388]
    DIRECTION OUTPUT ;
    USE SIGNAL ;
    SHAPE ABUTMENT ;
    PORT
      LAYER M2 ;
      RECT 76.239 85.590 76.257 85.860 ;
    END
  END r0_rd_out[388]
  PIN r0_rd_out[389]
    DIRECTION OUTPUT ;
    USE SIGNAL ;
    SHAPE ABUTMENT ;
    PORT
      LAYER M2 ;
      RECT 76.815 85.590 76.833 85.860 ;
    END
  END r0_rd_out[389]
  PIN r0_rd_out[390]
    DIRECTION OUTPUT ;
    USE SIGNAL ;
    SHAPE ABUTMENT ;
    PORT
      LAYER M2 ;
      RECT 77.391 85.590 77.409 85.860 ;
    END
  END r0_rd_out[390]
  PIN r0_rd_out[391]
    DIRECTION OUTPUT ;
    USE SIGNAL ;
    SHAPE ABUTMENT ;
    PORT
      LAYER M2 ;
      RECT 77.967 85.590 77.985 85.860 ;
    END
  END r0_rd_out[391]
  PIN r0_rd_out[392]
    DIRECTION OUTPUT ;
    USE SIGNAL ;
    SHAPE ABUTMENT ;
    PORT
      LAYER M2 ;
      RECT 78.543 85.590 78.561 85.860 ;
    END
  END r0_rd_out[392]
  PIN r0_rd_out[393]
    DIRECTION OUTPUT ;
    USE SIGNAL ;
    SHAPE ABUTMENT ;
    PORT
      LAYER M2 ;
      RECT 79.119 85.590 79.137 85.860 ;
    END
  END r0_rd_out[393]
  PIN r0_rd_out[394]
    DIRECTION OUTPUT ;
    USE SIGNAL ;
    SHAPE ABUTMENT ;
    PORT
      LAYER M2 ;
      RECT 79.695 85.590 79.713 85.860 ;
    END
  END r0_rd_out[394]
  PIN r0_rd_out[395]
    DIRECTION OUTPUT ;
    USE SIGNAL ;
    SHAPE ABUTMENT ;
    PORT
      LAYER M2 ;
      RECT 80.271 85.590 80.289 85.860 ;
    END
  END r0_rd_out[395]
  PIN r0_rd_out[396]
    DIRECTION OUTPUT ;
    USE SIGNAL ;
    SHAPE ABUTMENT ;
    PORT
      LAYER M2 ;
      RECT 80.847 85.590 80.865 85.860 ;
    END
  END r0_rd_out[396]
  PIN r0_rd_out[397]
    DIRECTION OUTPUT ;
    USE SIGNAL ;
    SHAPE ABUTMENT ;
    PORT
      LAYER M2 ;
      RECT 81.423 85.590 81.441 85.860 ;
    END
  END r0_rd_out[397]
  PIN r0_rd_out[398]
    DIRECTION OUTPUT ;
    USE SIGNAL ;
    SHAPE ABUTMENT ;
    PORT
      LAYER M2 ;
      RECT 81.999 85.590 82.017 85.860 ;
    END
  END r0_rd_out[398]
  PIN r0_rd_out[399]
    DIRECTION OUTPUT ;
    USE SIGNAL ;
    SHAPE ABUTMENT ;
    PORT
      LAYER M2 ;
      RECT 82.575 85.590 82.593 85.860 ;
    END
  END r0_rd_out[399]
  PIN r0_rd_out[400]
    DIRECTION OUTPUT ;
    USE SIGNAL ;
    SHAPE ABUTMENT ;
    PORT
      LAYER M2 ;
      RECT 83.151 85.590 83.169 85.860 ;
    END
  END r0_rd_out[400]
  PIN r0_rd_out[401]
    DIRECTION OUTPUT ;
    USE SIGNAL ;
    SHAPE ABUTMENT ;
    PORT
      LAYER M2 ;
      RECT 83.727 85.590 83.745 85.860 ;
    END
  END r0_rd_out[401]
  PIN r0_rd_out[402]
    DIRECTION OUTPUT ;
    USE SIGNAL ;
    SHAPE ABUTMENT ;
    PORT
      LAYER M2 ;
      RECT 84.303 85.590 84.321 85.860 ;
    END
  END r0_rd_out[402]
  PIN r0_rd_out[403]
    DIRECTION OUTPUT ;
    USE SIGNAL ;
    SHAPE ABUTMENT ;
    PORT
      LAYER M2 ;
      RECT 84.879 85.590 84.897 85.860 ;
    END
  END r0_rd_out[403]
  PIN r0_rd_out[404]
    DIRECTION OUTPUT ;
    USE SIGNAL ;
    SHAPE ABUTMENT ;
    PORT
      LAYER M2 ;
      RECT 85.455 85.590 85.473 85.860 ;
    END
  END r0_rd_out[404]
  PIN r0_rd_out[405]
    DIRECTION OUTPUT ;
    USE SIGNAL ;
    SHAPE ABUTMENT ;
    PORT
      LAYER M2 ;
      RECT 86.031 85.590 86.049 85.860 ;
    END
  END r0_rd_out[405]
  PIN r0_rd_out[406]
    DIRECTION OUTPUT ;
    USE SIGNAL ;
    SHAPE ABUTMENT ;
    PORT
      LAYER M2 ;
      RECT 86.607 85.590 86.625 85.860 ;
    END
  END r0_rd_out[406]
  PIN r0_rd_out[407]
    DIRECTION OUTPUT ;
    USE SIGNAL ;
    SHAPE ABUTMENT ;
    PORT
      LAYER M2 ;
      RECT 87.183 85.590 87.201 85.860 ;
    END
  END r0_rd_out[407]
  PIN r0_rd_out[408]
    DIRECTION OUTPUT ;
    USE SIGNAL ;
    SHAPE ABUTMENT ;
    PORT
      LAYER M2 ;
      RECT 87.759 85.590 87.777 85.860 ;
    END
  END r0_rd_out[408]
  PIN r0_rd_out[409]
    DIRECTION OUTPUT ;
    USE SIGNAL ;
    SHAPE ABUTMENT ;
    PORT
      LAYER M2 ;
      RECT 88.335 85.590 88.353 85.860 ;
    END
  END r0_rd_out[409]
  PIN r0_rd_out[410]
    DIRECTION OUTPUT ;
    USE SIGNAL ;
    SHAPE ABUTMENT ;
    PORT
      LAYER M2 ;
      RECT 88.911 85.590 88.929 85.860 ;
    END
  END r0_rd_out[410]
  PIN r0_rd_out[411]
    DIRECTION OUTPUT ;
    USE SIGNAL ;
    SHAPE ABUTMENT ;
    PORT
      LAYER M2 ;
      RECT 89.487 85.590 89.505 85.860 ;
    END
  END r0_rd_out[411]
  PIN r0_rd_out[412]
    DIRECTION OUTPUT ;
    USE SIGNAL ;
    SHAPE ABUTMENT ;
    PORT
      LAYER M2 ;
      RECT 90.063 85.590 90.081 85.860 ;
    END
  END r0_rd_out[412]
  PIN r0_rd_out[413]
    DIRECTION OUTPUT ;
    USE SIGNAL ;
    SHAPE ABUTMENT ;
    PORT
      LAYER M2 ;
      RECT 90.639 85.590 90.657 85.860 ;
    END
  END r0_rd_out[413]
  PIN r0_rd_out[414]
    DIRECTION OUTPUT ;
    USE SIGNAL ;
    SHAPE ABUTMENT ;
    PORT
      LAYER M2 ;
      RECT 91.215 85.590 91.233 85.860 ;
    END
  END r0_rd_out[414]
  PIN r0_rd_out[415]
    DIRECTION OUTPUT ;
    USE SIGNAL ;
    SHAPE ABUTMENT ;
    PORT
      LAYER M2 ;
      RECT 91.791 85.590 91.809 85.860 ;
    END
  END r0_rd_out[415]
  PIN r0_rd_out[416]
    DIRECTION OUTPUT ;
    USE SIGNAL ;
    SHAPE ABUTMENT ;
    PORT
      LAYER M2 ;
      RECT 92.367 85.590 92.385 85.860 ;
    END
  END r0_rd_out[416]
  PIN r0_rd_out[417]
    DIRECTION OUTPUT ;
    USE SIGNAL ;
    SHAPE ABUTMENT ;
    PORT
      LAYER M2 ;
      RECT 92.943 85.590 92.961 85.860 ;
    END
  END r0_rd_out[417]
  PIN r0_rd_out[418]
    DIRECTION OUTPUT ;
    USE SIGNAL ;
    SHAPE ABUTMENT ;
    PORT
      LAYER M2 ;
      RECT 93.519 85.590 93.537 85.860 ;
    END
  END r0_rd_out[418]
  PIN r0_rd_out[419]
    DIRECTION OUTPUT ;
    USE SIGNAL ;
    SHAPE ABUTMENT ;
    PORT
      LAYER M2 ;
      RECT 94.095 85.590 94.113 85.860 ;
    END
  END r0_rd_out[419]
  PIN r0_rd_out[420]
    DIRECTION OUTPUT ;
    USE SIGNAL ;
    SHAPE ABUTMENT ;
    PORT
      LAYER M2 ;
      RECT 94.671 85.590 94.689 85.860 ;
    END
  END r0_rd_out[420]
  PIN r0_rd_out[421]
    DIRECTION OUTPUT ;
    USE SIGNAL ;
    SHAPE ABUTMENT ;
    PORT
      LAYER M2 ;
      RECT 95.247 85.590 95.265 85.860 ;
    END
  END r0_rd_out[421]
  PIN r0_rd_out[422]
    DIRECTION OUTPUT ;
    USE SIGNAL ;
    SHAPE ABUTMENT ;
    PORT
      LAYER M2 ;
      RECT 95.823 85.590 95.841 85.860 ;
    END
  END r0_rd_out[422]
  PIN r0_rd_out[423]
    DIRECTION OUTPUT ;
    USE SIGNAL ;
    SHAPE ABUTMENT ;
    PORT
      LAYER M2 ;
      RECT 96.399 85.590 96.417 85.860 ;
    END
  END r0_rd_out[423]
  PIN r0_rd_out[424]
    DIRECTION OUTPUT ;
    USE SIGNAL ;
    SHAPE ABUTMENT ;
    PORT
      LAYER M2 ;
      RECT 96.975 85.590 96.993 85.860 ;
    END
  END r0_rd_out[424]
  PIN r0_rd_out[425]
    DIRECTION OUTPUT ;
    USE SIGNAL ;
    SHAPE ABUTMENT ;
    PORT
      LAYER M2 ;
      RECT 97.551 85.590 97.569 85.860 ;
    END
  END r0_rd_out[425]
  PIN r0_rd_out[426]
    DIRECTION OUTPUT ;
    USE SIGNAL ;
    SHAPE ABUTMENT ;
    PORT
      LAYER M2 ;
      RECT 98.127 85.590 98.145 85.860 ;
    END
  END r0_rd_out[426]
  PIN r0_rd_out[427]
    DIRECTION OUTPUT ;
    USE SIGNAL ;
    SHAPE ABUTMENT ;
    PORT
      LAYER M2 ;
      RECT 98.703 85.590 98.721 85.860 ;
    END
  END r0_rd_out[427]
  PIN r0_rd_out[428]
    DIRECTION OUTPUT ;
    USE SIGNAL ;
    SHAPE ABUTMENT ;
    PORT
      LAYER M2 ;
      RECT 99.279 85.590 99.297 85.860 ;
    END
  END r0_rd_out[428]
  PIN r0_rd_out[429]
    DIRECTION OUTPUT ;
    USE SIGNAL ;
    SHAPE ABUTMENT ;
    PORT
      LAYER M2 ;
      RECT 99.855 85.590 99.873 85.860 ;
    END
  END r0_rd_out[429]
  PIN r0_rd_out[430]
    DIRECTION OUTPUT ;
    USE SIGNAL ;
    SHAPE ABUTMENT ;
    PORT
      LAYER M2 ;
      RECT 100.431 85.590 100.449 85.860 ;
    END
  END r0_rd_out[430]
  PIN r0_rd_out[431]
    DIRECTION OUTPUT ;
    USE SIGNAL ;
    SHAPE ABUTMENT ;
    PORT
      LAYER M2 ;
      RECT 101.007 85.590 101.025 85.860 ;
    END
  END r0_rd_out[431]
  PIN r0_rd_out[432]
    DIRECTION OUTPUT ;
    USE SIGNAL ;
    SHAPE ABUTMENT ;
    PORT
      LAYER M2 ;
      RECT 101.583 85.590 101.601 85.860 ;
    END
  END r0_rd_out[432]
  PIN r0_rd_out[433]
    DIRECTION OUTPUT ;
    USE SIGNAL ;
    SHAPE ABUTMENT ;
    PORT
      LAYER M2 ;
      RECT 102.159 85.590 102.177 85.860 ;
    END
  END r0_rd_out[433]
  PIN r0_rd_out[434]
    DIRECTION OUTPUT ;
    USE SIGNAL ;
    SHAPE ABUTMENT ;
    PORT
      LAYER M2 ;
      RECT 102.735 85.590 102.753 85.860 ;
    END
  END r0_rd_out[434]
  PIN r0_rd_out[435]
    DIRECTION OUTPUT ;
    USE SIGNAL ;
    SHAPE ABUTMENT ;
    PORT
      LAYER M2 ;
      RECT 103.311 85.590 103.329 85.860 ;
    END
  END r0_rd_out[435]
  PIN r0_rd_out[436]
    DIRECTION OUTPUT ;
    USE SIGNAL ;
    SHAPE ABUTMENT ;
    PORT
      LAYER M2 ;
      RECT 103.887 85.590 103.905 85.860 ;
    END
  END r0_rd_out[436]
  PIN r0_rd_out[437]
    DIRECTION OUTPUT ;
    USE SIGNAL ;
    SHAPE ABUTMENT ;
    PORT
      LAYER M2 ;
      RECT 104.463 85.590 104.481 85.860 ;
    END
  END r0_rd_out[437]
  PIN r0_rd_out[438]
    DIRECTION OUTPUT ;
    USE SIGNAL ;
    SHAPE ABUTMENT ;
    PORT
      LAYER M2 ;
      RECT 105.039 85.590 105.057 85.860 ;
    END
  END r0_rd_out[438]
  PIN r0_rd_out[439]
    DIRECTION OUTPUT ;
    USE SIGNAL ;
    SHAPE ABUTMENT ;
    PORT
      LAYER M2 ;
      RECT 105.615 85.590 105.633 85.860 ;
    END
  END r0_rd_out[439]
  PIN r0_rd_out[440]
    DIRECTION OUTPUT ;
    USE SIGNAL ;
    SHAPE ABUTMENT ;
    PORT
      LAYER M2 ;
      RECT 106.191 85.590 106.209 85.860 ;
    END
  END r0_rd_out[440]
  PIN r0_rd_out[441]
    DIRECTION OUTPUT ;
    USE SIGNAL ;
    SHAPE ABUTMENT ;
    PORT
      LAYER M2 ;
      RECT 106.767 85.590 106.785 85.860 ;
    END
  END r0_rd_out[441]
  PIN r0_rd_out[442]
    DIRECTION OUTPUT ;
    USE SIGNAL ;
    SHAPE ABUTMENT ;
    PORT
      LAYER M2 ;
      RECT 107.343 85.590 107.361 85.860 ;
    END
  END r0_rd_out[442]
  PIN r0_rd_out[443]
    DIRECTION OUTPUT ;
    USE SIGNAL ;
    SHAPE ABUTMENT ;
    PORT
      LAYER M2 ;
      RECT 107.919 85.590 107.937 85.860 ;
    END
  END r0_rd_out[443]
  PIN r0_rd_out[444]
    DIRECTION OUTPUT ;
    USE SIGNAL ;
    SHAPE ABUTMENT ;
    PORT
      LAYER M2 ;
      RECT 108.495 85.590 108.513 85.860 ;
    END
  END r0_rd_out[444]
  PIN r0_rd_out[445]
    DIRECTION OUTPUT ;
    USE SIGNAL ;
    SHAPE ABUTMENT ;
    PORT
      LAYER M2 ;
      RECT 109.071 85.590 109.089 85.860 ;
    END
  END r0_rd_out[445]
  PIN r0_rd_out[446]
    DIRECTION OUTPUT ;
    USE SIGNAL ;
    SHAPE ABUTMENT ;
    PORT
      LAYER M2 ;
      RECT 109.647 85.590 109.665 85.860 ;
    END
  END r0_rd_out[446]
  PIN r0_rd_out[447]
    DIRECTION OUTPUT ;
    USE SIGNAL ;
    SHAPE ABUTMENT ;
    PORT
      LAYER M2 ;
      RECT 110.223 85.590 110.241 85.860 ;
    END
  END r0_rd_out[447]
  PIN r0_rd_out[448]
    DIRECTION OUTPUT ;
    USE SIGNAL ;
    SHAPE ABUTMENT ;
    PORT
      LAYER M2 ;
      RECT 110.799 85.590 110.817 85.860 ;
    END
  END r0_rd_out[448]
  PIN r0_rd_out[449]
    DIRECTION OUTPUT ;
    USE SIGNAL ;
    SHAPE ABUTMENT ;
    PORT
      LAYER M2 ;
      RECT 111.375 85.590 111.393 85.860 ;
    END
  END r0_rd_out[449]
  PIN r0_rd_out[450]
    DIRECTION OUTPUT ;
    USE SIGNAL ;
    SHAPE ABUTMENT ;
    PORT
      LAYER M2 ;
      RECT 111.951 85.590 111.969 85.860 ;
    END
  END r0_rd_out[450]
  PIN r0_rd_out[451]
    DIRECTION OUTPUT ;
    USE SIGNAL ;
    SHAPE ABUTMENT ;
    PORT
      LAYER M2 ;
      RECT 112.527 85.590 112.545 85.860 ;
    END
  END r0_rd_out[451]
  PIN r0_rd_out[452]
    DIRECTION OUTPUT ;
    USE SIGNAL ;
    SHAPE ABUTMENT ;
    PORT
      LAYER M2 ;
      RECT 113.103 85.590 113.121 85.860 ;
    END
  END r0_rd_out[452]
  PIN r0_rd_out[453]
    DIRECTION OUTPUT ;
    USE SIGNAL ;
    SHAPE ABUTMENT ;
    PORT
      LAYER M2 ;
      RECT 113.679 85.590 113.697 85.860 ;
    END
  END r0_rd_out[453]
  PIN r0_rd_out[454]
    DIRECTION OUTPUT ;
    USE SIGNAL ;
    SHAPE ABUTMENT ;
    PORT
      LAYER M2 ;
      RECT 114.255 85.590 114.273 85.860 ;
    END
  END r0_rd_out[454]
  PIN r0_rd_out[455]
    DIRECTION OUTPUT ;
    USE SIGNAL ;
    SHAPE ABUTMENT ;
    PORT
      LAYER M2 ;
      RECT 114.831 85.590 114.849 85.860 ;
    END
  END r0_rd_out[455]
  PIN r0_rd_out[456]
    DIRECTION OUTPUT ;
    USE SIGNAL ;
    SHAPE ABUTMENT ;
    PORT
      LAYER M2 ;
      RECT 115.407 85.590 115.425 85.860 ;
    END
  END r0_rd_out[456]
  PIN r0_rd_out[457]
    DIRECTION OUTPUT ;
    USE SIGNAL ;
    SHAPE ABUTMENT ;
    PORT
      LAYER M2 ;
      RECT 115.983 85.590 116.001 85.860 ;
    END
  END r0_rd_out[457]
  PIN r0_rd_out[458]
    DIRECTION OUTPUT ;
    USE SIGNAL ;
    SHAPE ABUTMENT ;
    PORT
      LAYER M2 ;
      RECT 116.559 85.590 116.577 85.860 ;
    END
  END r0_rd_out[458]
  PIN r0_rd_out[459]
    DIRECTION OUTPUT ;
    USE SIGNAL ;
    SHAPE ABUTMENT ;
    PORT
      LAYER M2 ;
      RECT 117.135 85.590 117.153 85.860 ;
    END
  END r0_rd_out[459]
  PIN r0_rd_out[460]
    DIRECTION OUTPUT ;
    USE SIGNAL ;
    SHAPE ABUTMENT ;
    PORT
      LAYER M2 ;
      RECT 117.711 85.590 117.729 85.860 ;
    END
  END r0_rd_out[460]
  PIN r0_rd_out[461]
    DIRECTION OUTPUT ;
    USE SIGNAL ;
    SHAPE ABUTMENT ;
    PORT
      LAYER M2 ;
      RECT 118.287 85.590 118.305 85.860 ;
    END
  END r0_rd_out[461]
  PIN r0_rd_out[462]
    DIRECTION OUTPUT ;
    USE SIGNAL ;
    SHAPE ABUTMENT ;
    PORT
      LAYER M2 ;
      RECT 118.863 85.590 118.881 85.860 ;
    END
  END r0_rd_out[462]
  PIN r0_rd_out[463]
    DIRECTION OUTPUT ;
    USE SIGNAL ;
    SHAPE ABUTMENT ;
    PORT
      LAYER M2 ;
      RECT 119.439 85.590 119.457 85.860 ;
    END
  END r0_rd_out[463]
  PIN r0_rd_out[464]
    DIRECTION OUTPUT ;
    USE SIGNAL ;
    SHAPE ABUTMENT ;
    PORT
      LAYER M2 ;
      RECT 120.015 85.590 120.033 85.860 ;
    END
  END r0_rd_out[464]
  PIN r0_rd_out[465]
    DIRECTION OUTPUT ;
    USE SIGNAL ;
    SHAPE ABUTMENT ;
    PORT
      LAYER M2 ;
      RECT 120.591 85.590 120.609 85.860 ;
    END
  END r0_rd_out[465]
  PIN r0_rd_out[466]
    DIRECTION OUTPUT ;
    USE SIGNAL ;
    SHAPE ABUTMENT ;
    PORT
      LAYER M2 ;
      RECT 121.167 85.590 121.185 85.860 ;
    END
  END r0_rd_out[466]
  PIN r0_rd_out[467]
    DIRECTION OUTPUT ;
    USE SIGNAL ;
    SHAPE ABUTMENT ;
    PORT
      LAYER M2 ;
      RECT 121.743 85.590 121.761 85.860 ;
    END
  END r0_rd_out[467]
  PIN r0_rd_out[468]
    DIRECTION OUTPUT ;
    USE SIGNAL ;
    SHAPE ABUTMENT ;
    PORT
      LAYER M2 ;
      RECT 122.319 85.590 122.337 85.860 ;
    END
  END r0_rd_out[468]
  PIN r0_rd_out[469]
    DIRECTION OUTPUT ;
    USE SIGNAL ;
    SHAPE ABUTMENT ;
    PORT
      LAYER M2 ;
      RECT 122.895 85.590 122.913 85.860 ;
    END
  END r0_rd_out[469]
  PIN r0_rd_out[470]
    DIRECTION OUTPUT ;
    USE SIGNAL ;
    SHAPE ABUTMENT ;
    PORT
      LAYER M2 ;
      RECT 123.471 85.590 123.489 85.860 ;
    END
  END r0_rd_out[470]
  PIN r0_rd_out[471]
    DIRECTION OUTPUT ;
    USE SIGNAL ;
    SHAPE ABUTMENT ;
    PORT
      LAYER M2 ;
      RECT 124.047 85.590 124.065 85.860 ;
    END
  END r0_rd_out[471]
  PIN r0_rd_out[472]
    DIRECTION OUTPUT ;
    USE SIGNAL ;
    SHAPE ABUTMENT ;
    PORT
      LAYER M2 ;
      RECT 124.623 85.590 124.641 85.860 ;
    END
  END r0_rd_out[472]
  PIN r0_rd_out[473]
    DIRECTION OUTPUT ;
    USE SIGNAL ;
    SHAPE ABUTMENT ;
    PORT
      LAYER M2 ;
      RECT 125.199 85.590 125.217 85.860 ;
    END
  END r0_rd_out[473]
  PIN r0_rd_out[474]
    DIRECTION OUTPUT ;
    USE SIGNAL ;
    SHAPE ABUTMENT ;
    PORT
      LAYER M2 ;
      RECT 125.775 85.590 125.793 85.860 ;
    END
  END r0_rd_out[474]
  PIN r0_rd_out[475]
    DIRECTION OUTPUT ;
    USE SIGNAL ;
    SHAPE ABUTMENT ;
    PORT
      LAYER M2 ;
      RECT 126.351 85.590 126.369 85.860 ;
    END
  END r0_rd_out[475]
  PIN r0_rd_out[476]
    DIRECTION OUTPUT ;
    USE SIGNAL ;
    SHAPE ABUTMENT ;
    PORT
      LAYER M2 ;
      RECT 126.927 85.590 126.945 85.860 ;
    END
  END r0_rd_out[476]
  PIN r0_rd_out[477]
    DIRECTION OUTPUT ;
    USE SIGNAL ;
    SHAPE ABUTMENT ;
    PORT
      LAYER M2 ;
      RECT 127.503 85.590 127.521 85.860 ;
    END
  END r0_rd_out[477]
  PIN r0_rd_out[478]
    DIRECTION OUTPUT ;
    USE SIGNAL ;
    SHAPE ABUTMENT ;
    PORT
      LAYER M2 ;
      RECT 128.079 85.590 128.097 85.860 ;
    END
  END r0_rd_out[478]
  PIN r0_rd_out[479]
    DIRECTION OUTPUT ;
    USE SIGNAL ;
    SHAPE ABUTMENT ;
    PORT
      LAYER M2 ;
      RECT 128.655 85.590 128.673 85.860 ;
    END
  END r0_rd_out[479]
  PIN r0_rd_out[480]
    DIRECTION OUTPUT ;
    USE SIGNAL ;
    SHAPE ABUTMENT ;
    PORT
      LAYER M2 ;
      RECT 129.231 85.590 129.249 85.860 ;
    END
  END r0_rd_out[480]
  PIN r0_rd_out[481]
    DIRECTION OUTPUT ;
    USE SIGNAL ;
    SHAPE ABUTMENT ;
    PORT
      LAYER M2 ;
      RECT 129.807 85.590 129.825 85.860 ;
    END
  END r0_rd_out[481]
  PIN r0_rd_out[482]
    DIRECTION OUTPUT ;
    USE SIGNAL ;
    SHAPE ABUTMENT ;
    PORT
      LAYER M2 ;
      RECT 130.383 85.590 130.401 85.860 ;
    END
  END r0_rd_out[482]
  PIN r0_rd_out[483]
    DIRECTION OUTPUT ;
    USE SIGNAL ;
    SHAPE ABUTMENT ;
    PORT
      LAYER M2 ;
      RECT 130.959 85.590 130.977 85.860 ;
    END
  END r0_rd_out[483]
  PIN r0_rd_out[484]
    DIRECTION OUTPUT ;
    USE SIGNAL ;
    SHAPE ABUTMENT ;
    PORT
      LAYER M2 ;
      RECT 131.535 85.590 131.553 85.860 ;
    END
  END r0_rd_out[484]
  PIN r0_rd_out[485]
    DIRECTION OUTPUT ;
    USE SIGNAL ;
    SHAPE ABUTMENT ;
    PORT
      LAYER M2 ;
      RECT 132.111 85.590 132.129 85.860 ;
    END
  END r0_rd_out[485]
  PIN r0_rd_out[486]
    DIRECTION OUTPUT ;
    USE SIGNAL ;
    SHAPE ABUTMENT ;
    PORT
      LAYER M2 ;
      RECT 132.687 85.590 132.705 85.860 ;
    END
  END r0_rd_out[486]
  PIN r0_rd_out[487]
    DIRECTION OUTPUT ;
    USE SIGNAL ;
    SHAPE ABUTMENT ;
    PORT
      LAYER M2 ;
      RECT 133.263 85.590 133.281 85.860 ;
    END
  END r0_rd_out[487]
  PIN r0_rd_out[488]
    DIRECTION OUTPUT ;
    USE SIGNAL ;
    SHAPE ABUTMENT ;
    PORT
      LAYER M2 ;
      RECT 133.839 85.590 133.857 85.860 ;
    END
  END r0_rd_out[488]
  PIN r0_rd_out[489]
    DIRECTION OUTPUT ;
    USE SIGNAL ;
    SHAPE ABUTMENT ;
    PORT
      LAYER M2 ;
      RECT 134.415 85.590 134.433 85.860 ;
    END
  END r0_rd_out[489]
  PIN r0_rd_out[490]
    DIRECTION OUTPUT ;
    USE SIGNAL ;
    SHAPE ABUTMENT ;
    PORT
      LAYER M2 ;
      RECT 134.991 85.590 135.009 85.860 ;
    END
  END r0_rd_out[490]
  PIN r0_rd_out[491]
    DIRECTION OUTPUT ;
    USE SIGNAL ;
    SHAPE ABUTMENT ;
    PORT
      LAYER M2 ;
      RECT 135.567 85.590 135.585 85.860 ;
    END
  END r0_rd_out[491]
  PIN r0_rd_out[492]
    DIRECTION OUTPUT ;
    USE SIGNAL ;
    SHAPE ABUTMENT ;
    PORT
      LAYER M2 ;
      RECT 136.143 85.590 136.161 85.860 ;
    END
  END r0_rd_out[492]
  PIN r0_rd_out[493]
    DIRECTION OUTPUT ;
    USE SIGNAL ;
    SHAPE ABUTMENT ;
    PORT
      LAYER M2 ;
      RECT 136.719 85.590 136.737 85.860 ;
    END
  END r0_rd_out[493]
  PIN r0_rd_out[494]
    DIRECTION OUTPUT ;
    USE SIGNAL ;
    SHAPE ABUTMENT ;
    PORT
      LAYER M2 ;
      RECT 137.295 85.590 137.313 85.860 ;
    END
  END r0_rd_out[494]
  PIN r0_rd_out[495]
    DIRECTION OUTPUT ;
    USE SIGNAL ;
    SHAPE ABUTMENT ;
    PORT
      LAYER M2 ;
      RECT 137.871 85.590 137.889 85.860 ;
    END
  END r0_rd_out[495]
  PIN r0_rd_out[496]
    DIRECTION OUTPUT ;
    USE SIGNAL ;
    SHAPE ABUTMENT ;
    PORT
      LAYER M2 ;
      RECT 138.447 85.590 138.465 85.860 ;
    END
  END r0_rd_out[496]
  PIN r0_rd_out[497]
    DIRECTION OUTPUT ;
    USE SIGNAL ;
    SHAPE ABUTMENT ;
    PORT
      LAYER M2 ;
      RECT 139.023 85.590 139.041 85.860 ;
    END
  END r0_rd_out[497]
  PIN r0_rd_out[498]
    DIRECTION OUTPUT ;
    USE SIGNAL ;
    SHAPE ABUTMENT ;
    PORT
      LAYER M2 ;
      RECT 139.599 85.590 139.617 85.860 ;
    END
  END r0_rd_out[498]
  PIN r0_rd_out[499]
    DIRECTION OUTPUT ;
    USE SIGNAL ;
    SHAPE ABUTMENT ;
    PORT
      LAYER M2 ;
      RECT 140.175 85.590 140.193 85.860 ;
    END
  END r0_rd_out[499]
  PIN r0_rd_out[500]
    DIRECTION OUTPUT ;
    USE SIGNAL ;
    SHAPE ABUTMENT ;
    PORT
      LAYER M2 ;
      RECT 140.751 85.590 140.769 85.860 ;
    END
  END r0_rd_out[500]
  PIN r0_rd_out[501]
    DIRECTION OUTPUT ;
    USE SIGNAL ;
    SHAPE ABUTMENT ;
    PORT
      LAYER M2 ;
      RECT 141.327 85.590 141.345 85.860 ;
    END
  END r0_rd_out[501]
  PIN r0_rd_out[502]
    DIRECTION OUTPUT ;
    USE SIGNAL ;
    SHAPE ABUTMENT ;
    PORT
      LAYER M2 ;
      RECT 141.903 85.590 141.921 85.860 ;
    END
  END r0_rd_out[502]
  PIN r0_rd_out[503]
    DIRECTION OUTPUT ;
    USE SIGNAL ;
    SHAPE ABUTMENT ;
    PORT
      LAYER M2 ;
      RECT 142.479 85.590 142.497 85.860 ;
    END
  END r0_rd_out[503]
  PIN r0_rd_out[504]
    DIRECTION OUTPUT ;
    USE SIGNAL ;
    SHAPE ABUTMENT ;
    PORT
      LAYER M2 ;
      RECT 143.055 85.590 143.073 85.860 ;
    END
  END r0_rd_out[504]
  PIN r0_rd_out[505]
    DIRECTION OUTPUT ;
    USE SIGNAL ;
    SHAPE ABUTMENT ;
    PORT
      LAYER M2 ;
      RECT 143.631 85.590 143.649 85.860 ;
    END
  END r0_rd_out[505]
  PIN r0_rd_out[506]
    DIRECTION OUTPUT ;
    USE SIGNAL ;
    SHAPE ABUTMENT ;
    PORT
      LAYER M2 ;
      RECT 144.207 85.590 144.225 85.860 ;
    END
  END r0_rd_out[506]
  PIN r0_rd_out[507]
    DIRECTION OUTPUT ;
    USE SIGNAL ;
    SHAPE ABUTMENT ;
    PORT
      LAYER M2 ;
      RECT 144.783 85.590 144.801 85.860 ;
    END
  END r0_rd_out[507]
  PIN r0_rd_out[508]
    DIRECTION OUTPUT ;
    USE SIGNAL ;
    SHAPE ABUTMENT ;
    PORT
      LAYER M2 ;
      RECT 145.359 85.590 145.377 85.860 ;
    END
  END r0_rd_out[508]
  PIN r0_rd_out[509]
    DIRECTION OUTPUT ;
    USE SIGNAL ;
    SHAPE ABUTMENT ;
    PORT
      LAYER M2 ;
      RECT 145.935 85.590 145.953 85.860 ;
    END
  END r0_rd_out[509]
  PIN r0_rd_out[510]
    DIRECTION OUTPUT ;
    USE SIGNAL ;
    SHAPE ABUTMENT ;
    PORT
      LAYER M2 ;
      RECT 146.511 85.590 146.529 85.860 ;
    END
  END r0_rd_out[510]
  PIN r0_rd_out[511]
    DIRECTION OUTPUT ;
    USE SIGNAL ;
    SHAPE ABUTMENT ;
    PORT
      LAYER M2 ;
      RECT 147.087 85.590 147.105 85.860 ;
    END
  END r0_rd_out[511]
  PIN w0_addr_in[0]
    DIRECTION INPUT ;
    USE SIGNAL ;
    SHAPE ABUTMENT ;
    PORT
      LAYER M3 ;
      RECT 0.000 80.148 0.072 80.172 ;
    END
  END w0_addr_in[0]
  PIN w0_addr_in[1]
    DIRECTION INPUT ;
    USE SIGNAL ;
    SHAPE ABUTMENT ;
    PORT
      LAYER M3 ;
      RECT 0.000 80.772 0.072 80.796 ;
    END
  END w0_addr_in[1]
  PIN w0_addr_in[2]
    DIRECTION INPUT ;
    USE SIGNAL ;
    SHAPE ABUTMENT ;
    PORT
      LAYER M3 ;
      RECT 0.000 81.396 0.072 81.420 ;
    END
  END w0_addr_in[2]
  PIN w0_addr_in[3]
    DIRECTION INPUT ;
    USE SIGNAL ;
    SHAPE ABUTMENT ;
    PORT
      LAYER M3 ;
      RECT 0.000 82.020 0.072 82.044 ;
    END
  END w0_addr_in[3]
  PIN w0_addr_in[4]
    DIRECTION INPUT ;
    USE SIGNAL ;
    SHAPE ABUTMENT ;
    PORT
      LAYER M3 ;
      RECT 154.224 80.148 154.296 80.172 ;
    END
  END w0_addr_in[4]
  PIN w0_addr_in[5]
    DIRECTION INPUT ;
    USE SIGNAL ;
    SHAPE ABUTMENT ;
    PORT
      LAYER M3 ;
      RECT 154.224 80.772 154.296 80.796 ;
    END
  END w0_addr_in[5]
  PIN w0_addr_in[6]
    DIRECTION INPUT ;
    USE SIGNAL ;
    SHAPE ABUTMENT ;
    PORT
      LAYER M3 ;
      RECT 154.224 81.396 154.296 81.420 ;
    END
  END w0_addr_in[6]
  PIN w0_addr_in[7]
    DIRECTION INPUT ;
    USE SIGNAL ;
    SHAPE ABUTMENT ;
    PORT
      LAYER M3 ;
      RECT 154.224 82.020 154.296 82.044 ;
    END
  END w0_addr_in[7]
  PIN r0_addr_in[0]
    DIRECTION INPUT ;
    USE SIGNAL ;
    SHAPE ABUTMENT ;
    PORT
      LAYER M3 ;
      RECT 0.000 82.644 0.072 82.668 ;
    END
  END r0_addr_in[0]
  PIN r0_addr_in[1]
    DIRECTION INPUT ;
    USE SIGNAL ;
    SHAPE ABUTMENT ;
    PORT
      LAYER M3 ;
      RECT 0.000 83.268 0.072 83.292 ;
    END
  END r0_addr_in[1]
  PIN r0_addr_in[2]
    DIRECTION INPUT ;
    USE SIGNAL ;
    SHAPE ABUTMENT ;
    PORT
      LAYER M3 ;
      RECT 0.000 83.892 0.072 83.916 ;
    END
  END r0_addr_in[2]
  PIN r0_addr_in[3]
    DIRECTION INPUT ;
    USE SIGNAL ;
    SHAPE ABUTMENT ;
    PORT
      LAYER M3 ;
      RECT 0.000 84.516 0.072 84.540 ;
    END
  END r0_addr_in[3]
  PIN r0_addr_in[4]
    DIRECTION INPUT ;
    USE SIGNAL ;
    SHAPE ABUTMENT ;
    PORT
      LAYER M3 ;
      RECT 154.224 82.644 154.296 82.668 ;
    END
  END r0_addr_in[4]
  PIN r0_addr_in[5]
    DIRECTION INPUT ;
    USE SIGNAL ;
    SHAPE ABUTMENT ;
    PORT
      LAYER M3 ;
      RECT 154.224 83.268 154.296 83.292 ;
    END
  END r0_addr_in[5]
  PIN r0_addr_in[6]
    DIRECTION INPUT ;
    USE SIGNAL ;
    SHAPE ABUTMENT ;
    PORT
      LAYER M3 ;
      RECT 154.224 83.892 154.296 83.916 ;
    END
  END r0_addr_in[6]
  PIN r0_addr_in[7]
    DIRECTION INPUT ;
    USE SIGNAL ;
    SHAPE ABUTMENT ;
    PORT
      LAYER M3 ;
      RECT 154.224 84.516 154.296 84.540 ;
    END
  END r0_addr_in[7]
  PIN w0_we_in
    DIRECTION INPUT ;
    USE SIGNAL ;
    SHAPE ABUTMENT ;
    PORT
      LAYER M2 ;
      RECT 147.663 85.590 147.681 85.860 ;
    END
  END w0_we_in
  PIN w0_ce_in
    DIRECTION INPUT ;
    USE SIGNAL ;
    SHAPE ABUTMENT ;
    PORT
      LAYER M2 ;
      RECT 148.239 85.590 148.257 85.860 ;
    END
  END w0_ce_in
  PIN w0_clk
    DIRECTION INPUT ;
    USE SIGNAL ;
    SHAPE ABUTMENT ;
    PORT
      LAYER M2 ;
      RECT 148.815 85.590 148.833 85.860 ;
    END
  END w0_clk
  PIN r0_ce_in
    DIRECTION INPUT ;
    USE SIGNAL ;
    SHAPE ABUTMENT ;
    PORT
      LAYER M2 ;
      RECT 149.391 85.590 149.409 85.860 ;
    END
  END r0_ce_in
  PIN r0_clk
    DIRECTION INPUT ;
    USE SIGNAL ;
    SHAPE ABUTMENT ;
    PORT
      LAYER M2 ;
      RECT 149.967 85.590 149.985 85.860 ;
    END
  END r0_clk
  PIN VSS
    DIRECTION INOUT ;
    USE GROUND ;
    PORT
      LAYER M4 ;
      RECT 0.216 0.228 154.080 0.348 ;
      RECT 0.216 0.996 154.080 1.116 ;
      RECT 0.216 1.764 154.080 1.884 ;
      RECT 0.216 2.532 154.080 2.652 ;
      RECT 0.216 3.300 154.080 3.420 ;
      RECT 0.216 4.068 154.080 4.188 ;
      RECT 0.216 4.836 154.080 4.956 ;
      RECT 0.216 5.604 154.080 5.724 ;
      RECT 0.216 6.372 154.080 6.492 ;
      RECT 0.216 7.140 154.080 7.260 ;
      RECT 0.216 7.908 154.080 8.028 ;
      RECT 0.216 8.676 154.080 8.796 ;
      RECT 0.216 9.444 154.080 9.564 ;
      RECT 0.216 10.212 154.080 10.332 ;
      RECT 0.216 10.980 154.080 11.100 ;
      RECT 0.216 11.748 154.080 11.868 ;
      RECT 0.216 12.516 154.080 12.636 ;
      RECT 0.216 13.284 154.080 13.404 ;
      RECT 0.216 14.052 154.080 14.172 ;
      RECT 0.216 14.820 154.080 14.940 ;
      RECT 0.216 15.588 154.080 15.708 ;
      RECT 0.216 16.356 154.080 16.476 ;
      RECT 0.216 17.124 154.080 17.244 ;
      RECT 0.216 17.892 154.080 18.012 ;
      RECT 0.216 18.660 154.080 18.780 ;
      RECT 0.216 19.428 154.080 19.548 ;
      RECT 0.216 20.196 154.080 20.316 ;
      RECT 0.216 20.964 154.080 21.084 ;
      RECT 0.216 21.732 154.080 21.852 ;
      RECT 0.216 22.500 154.080 22.620 ;
      RECT 0.216 23.268 154.080 23.388 ;
      RECT 0.216 24.036 154.080 24.156 ;
      RECT 0.216 24.804 154.080 24.924 ;
      RECT 0.216 25.572 154.080 25.692 ;
      RECT 0.216 26.340 154.080 26.460 ;
      RECT 0.216 27.108 154.080 27.228 ;
      RECT 0.216 27.876 154.080 27.996 ;
      RECT 0.216 28.644 154.080 28.764 ;
      RECT 0.216 29.412 154.080 29.532 ;
      RECT 0.216 30.180 154.080 30.300 ;
      RECT 0.216 30.948 154.080 31.068 ;
      RECT 0.216 31.716 154.080 31.836 ;
      RECT 0.216 32.484 154.080 32.604 ;
      RECT 0.216 33.252 154.080 33.372 ;
      RECT 0.216 34.020 154.080 34.140 ;
      RECT 0.216 34.788 154.080 34.908 ;
      RECT 0.216 35.556 154.080 35.676 ;
      RECT 0.216 36.324 154.080 36.444 ;
      RECT 0.216 37.092 154.080 37.212 ;
      RECT 0.216 37.860 154.080 37.980 ;
      RECT 0.216 38.628 154.080 38.748 ;
      RECT 0.216 39.396 154.080 39.516 ;
      RECT 0.216 40.164 154.080 40.284 ;
      RECT 0.216 40.932 154.080 41.052 ;
      RECT 0.216 41.700 154.080 41.820 ;
      RECT 0.216 42.468 154.080 42.588 ;
      RECT 0.216 43.236 154.080 43.356 ;
      RECT 0.216 44.004 154.080 44.124 ;
      RECT 0.216 44.772 154.080 44.892 ;
      RECT 0.216 45.540 154.080 45.660 ;
      RECT 0.216 46.308 154.080 46.428 ;
      RECT 0.216 47.076 154.080 47.196 ;
      RECT 0.216 47.844 154.080 47.964 ;
      RECT 0.216 48.612 154.080 48.732 ;
      RECT 0.216 49.380 154.080 49.500 ;
      RECT 0.216 50.148 154.080 50.268 ;
      RECT 0.216 50.916 154.080 51.036 ;
      RECT 0.216 51.684 154.080 51.804 ;
      RECT 0.216 52.452 154.080 52.572 ;
      RECT 0.216 53.220 154.080 53.340 ;
      RECT 0.216 53.988 154.080 54.108 ;
      RECT 0.216 54.756 154.080 54.876 ;
      RECT 0.216 55.524 154.080 55.644 ;
      RECT 0.216 56.292 154.080 56.412 ;
      RECT 0.216 57.060 154.080 57.180 ;
      RECT 0.216 57.828 154.080 57.948 ;
      RECT 0.216 58.596 154.080 58.716 ;
      RECT 0.216 59.364 154.080 59.484 ;
      RECT 0.216 60.132 154.080 60.252 ;
      RECT 0.216 60.900 154.080 61.020 ;
      RECT 0.216 61.668 154.080 61.788 ;
      RECT 0.216 62.436 154.080 62.556 ;
      RECT 0.216 63.204 154.080 63.324 ;
      RECT 0.216 63.972 154.080 64.092 ;
      RECT 0.216 64.740 154.080 64.860 ;
      RECT 0.216 65.508 154.080 65.628 ;
      RECT 0.216 66.276 154.080 66.396 ;
      RECT 0.216 67.044 154.080 67.164 ;
      RECT 0.216 67.812 154.080 67.932 ;
      RECT 0.216 68.580 154.080 68.700 ;
      RECT 0.216 69.348 154.080 69.468 ;
      RECT 0.216 70.116 154.080 70.236 ;
      RECT 0.216 70.884 154.080 71.004 ;
      RECT 0.216 71.652 154.080 71.772 ;
      RECT 0.216 72.420 154.080 72.540 ;
      RECT 0.216 73.188 154.080 73.308 ;
      RECT 0.216 73.956 154.080 74.076 ;
      RECT 0.216 74.724 154.080 74.844 ;
      RECT 0.216 75.492 154.080 75.612 ;
      RECT 0.216 76.260 154.080 76.380 ;
      RECT 0.216 77.028 154.080 77.148 ;
      RECT 0.216 77.796 154.080 77.916 ;
      RECT 0.216 78.564 154.080 78.684 ;
      RECT 0.216 79.332 154.080 79.452 ;
      RECT 0.216 80.100 154.080 80.220 ;
      RECT 0.216 80.868 154.080 80.988 ;
      RECT 0.216 81.636 154.080 81.756 ;
      RECT 0.216 82.404 154.080 82.524 ;
      RECT 0.216 83.172 154.080 83.292 ;
      RECT 0.216 83.940 154.080 84.060 ;
      RECT 0.216 84.708 154.080 84.828 ;
      RECT 0.216 85.476 154.080 85.596 ;
    END
  END VSS
  PIN VDD
    DIRECTION INOUT ;
    USE POWER ;
    PORT
      LAYER M4 ;
      RECT 0.216 0.612 154.080 0.732 ;
      RECT 0.216 1.380 154.080 1.500 ;
      RECT 0.216 2.148 154.080 2.268 ;
      RECT 0.216 2.916 154.080 3.036 ;
      RECT 0.216 3.684 154.080 3.804 ;
      RECT 0.216 4.452 154.080 4.572 ;
      RECT 0.216 5.220 154.080 5.340 ;
      RECT 0.216 5.988 154.080 6.108 ;
      RECT 0.216 6.756 154.080 6.876 ;
      RECT 0.216 7.524 154.080 7.644 ;
      RECT 0.216 8.292 154.080 8.412 ;
      RECT 0.216 9.060 154.080 9.180 ;
      RECT 0.216 9.828 154.080 9.948 ;
      RECT 0.216 10.596 154.080 10.716 ;
      RECT 0.216 11.364 154.080 11.484 ;
      RECT 0.216 12.132 154.080 12.252 ;
      RECT 0.216 12.900 154.080 13.020 ;
      RECT 0.216 13.668 154.080 13.788 ;
      RECT 0.216 14.436 154.080 14.556 ;
      RECT 0.216 15.204 154.080 15.324 ;
      RECT 0.216 15.972 154.080 16.092 ;
      RECT 0.216 16.740 154.080 16.860 ;
      RECT 0.216 17.508 154.080 17.628 ;
      RECT 0.216 18.276 154.080 18.396 ;
      RECT 0.216 19.044 154.080 19.164 ;
      RECT 0.216 19.812 154.080 19.932 ;
      RECT 0.216 20.580 154.080 20.700 ;
      RECT 0.216 21.348 154.080 21.468 ;
      RECT 0.216 22.116 154.080 22.236 ;
      RECT 0.216 22.884 154.080 23.004 ;
      RECT 0.216 23.652 154.080 23.772 ;
      RECT 0.216 24.420 154.080 24.540 ;
      RECT 0.216 25.188 154.080 25.308 ;
      RECT 0.216 25.956 154.080 26.076 ;
      RECT 0.216 26.724 154.080 26.844 ;
      RECT 0.216 27.492 154.080 27.612 ;
      RECT 0.216 28.260 154.080 28.380 ;
      RECT 0.216 29.028 154.080 29.148 ;
      RECT 0.216 29.796 154.080 29.916 ;
      RECT 0.216 30.564 154.080 30.684 ;
      RECT 0.216 31.332 154.080 31.452 ;
      RECT 0.216 32.100 154.080 32.220 ;
      RECT 0.216 32.868 154.080 32.988 ;
      RECT 0.216 33.636 154.080 33.756 ;
      RECT 0.216 34.404 154.080 34.524 ;
      RECT 0.216 35.172 154.080 35.292 ;
      RECT 0.216 35.940 154.080 36.060 ;
      RECT 0.216 36.708 154.080 36.828 ;
      RECT 0.216 37.476 154.080 37.596 ;
      RECT 0.216 38.244 154.080 38.364 ;
      RECT 0.216 39.012 154.080 39.132 ;
      RECT 0.216 39.780 154.080 39.900 ;
      RECT 0.216 40.548 154.080 40.668 ;
      RECT 0.216 41.316 154.080 41.436 ;
      RECT 0.216 42.084 154.080 42.204 ;
      RECT 0.216 42.852 154.080 42.972 ;
      RECT 0.216 43.620 154.080 43.740 ;
      RECT 0.216 44.388 154.080 44.508 ;
      RECT 0.216 45.156 154.080 45.276 ;
      RECT 0.216 45.924 154.080 46.044 ;
      RECT 0.216 46.692 154.080 46.812 ;
      RECT 0.216 47.460 154.080 47.580 ;
      RECT 0.216 48.228 154.080 48.348 ;
      RECT 0.216 48.996 154.080 49.116 ;
      RECT 0.216 49.764 154.080 49.884 ;
      RECT 0.216 50.532 154.080 50.652 ;
      RECT 0.216 51.300 154.080 51.420 ;
      RECT 0.216 52.068 154.080 52.188 ;
      RECT 0.216 52.836 154.080 52.956 ;
      RECT 0.216 53.604 154.080 53.724 ;
      RECT 0.216 54.372 154.080 54.492 ;
      RECT 0.216 55.140 154.080 55.260 ;
      RECT 0.216 55.908 154.080 56.028 ;
      RECT 0.216 56.676 154.080 56.796 ;
      RECT 0.216 57.444 154.080 57.564 ;
      RECT 0.216 58.212 154.080 58.332 ;
      RECT 0.216 58.980 154.080 59.100 ;
      RECT 0.216 59.748 154.080 59.868 ;
      RECT 0.216 60.516 154.080 60.636 ;
      RECT 0.216 61.284 154.080 61.404 ;
      RECT 0.216 62.052 154.080 62.172 ;
      RECT 0.216 62.820 154.080 62.940 ;
      RECT 0.216 63.588 154.080 63.708 ;
      RECT 0.216 64.356 154.080 64.476 ;
      RECT 0.216 65.124 154.080 65.244 ;
      RECT 0.216 65.892 154.080 66.012 ;
      RECT 0.216 66.660 154.080 66.780 ;
      RECT 0.216 67.428 154.080 67.548 ;
      RECT 0.216 68.196 154.080 68.316 ;
      RECT 0.216 68.964 154.080 69.084 ;
      RECT 0.216 69.732 154.080 69.852 ;
      RECT 0.216 70.500 154.080 70.620 ;
      RECT 0.216 71.268 154.080 71.388 ;
      RECT 0.216 72.036 154.080 72.156 ;
      RECT 0.216 72.804 154.080 72.924 ;
      RECT 0.216 73.572 154.080 73.692 ;
      RECT 0.216 74.340 154.080 74.460 ;
      RECT 0.216 75.108 154.080 75.228 ;
      RECT 0.216 75.876 154.080 75.996 ;
      RECT 0.216 76.644 154.080 76.764 ;
      RECT 0.216 77.412 154.080 77.532 ;
      RECT 0.216 78.180 154.080 78.300 ;
      RECT 0.216 78.948 154.080 79.068 ;
      RECT 0.216 79.716 154.080 79.836 ;
      RECT 0.216 80.484 154.080 80.604 ;
      RECT 0.216 81.252 154.080 81.372 ;
      RECT 0.216 82.020 154.080 82.140 ;
      RECT 0.216 82.788 154.080 82.908 ;
      RECT 0.216 83.556 154.080 83.676 ;
      RECT 0.216 84.324 154.080 84.444 ;
      RECT 0.216 85.092 154.080 85.212 ;
    END
  END VDD
  OBS
    LAYER M1 ;
    RECT 0 0 154.296 85.860 ;
    LAYER M2 ;
    RECT 0 0 154.296 85.860 ;
    LAYER M3 ;
    RECT 0 0 154.296 85.860 ;
    LAYER M4 ;
    RECT 0 0 154.296 85.860 ;
  END
END ht_asap7_nyuzi_256x512

END LIBRARY
